VERSION 5.8 ;
BUSBITCHARS "[]" ;
DIVIDERCHAR "/" ;
UNITS
    DATABASE MICRONS 1000 ;
END UNITS

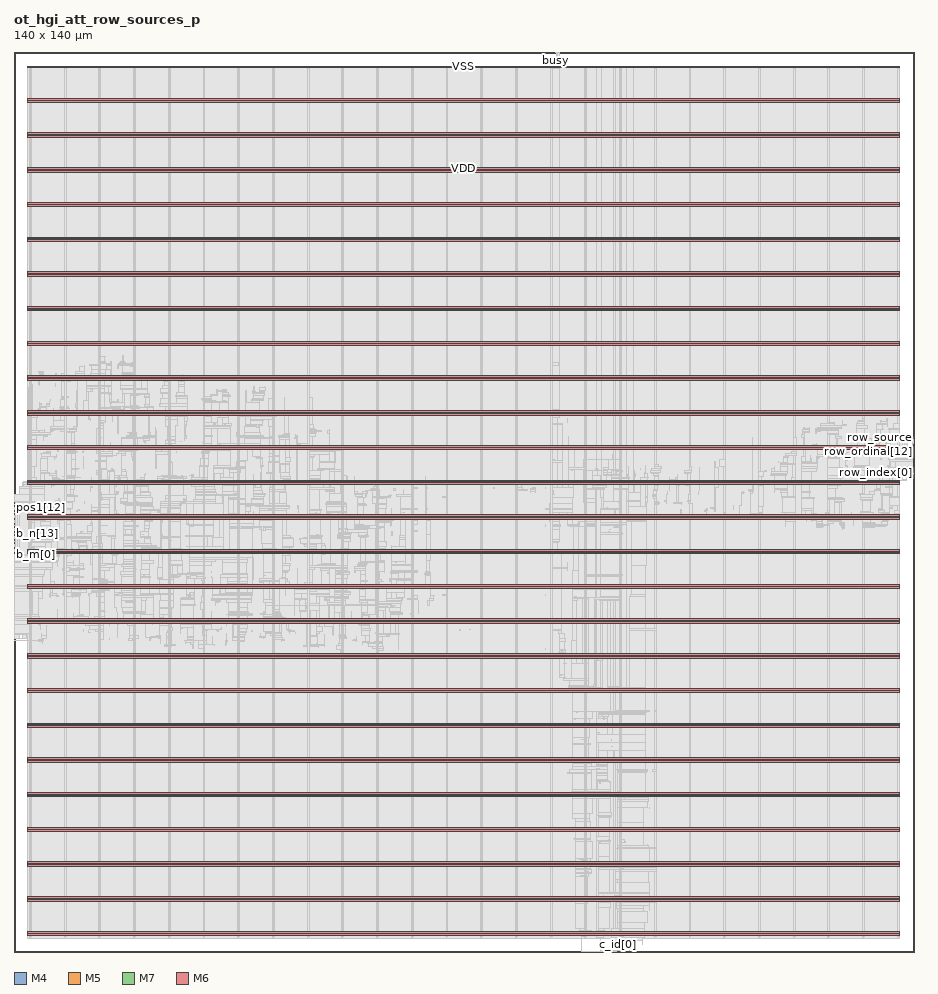
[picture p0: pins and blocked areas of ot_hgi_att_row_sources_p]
MACRO ot_hgi_att_row_sources_p
  FOREIGN ot_hgi_att_row_sources_p 0 0 ;
  CLASS BLOCK ;
  SIZE 140 BY 140 ;
  PIN b_m[0]
    DIRECTION INPUT ;
    USE SIGNAL ;
    PORT
      LAYER M4 ;
        RECT  0 61.776 0.084 61.8 ;
    END
  END b_m[0]
  PIN b_m[10]
    DIRECTION INPUT ;
    USE SIGNAL ;
    PORT
      LAYER M4 ;
        RECT  0 62.736 0.084 62.76 ;
    END
  END b_m[10]
  PIN b_m[11]
    DIRECTION INPUT ;
    USE SIGNAL ;
    PORT
      LAYER M4 ;
        RECT  0 62.832 0.084 62.856 ;
    END
  END b_m[11]
  PIN b_m[12]
    DIRECTION INPUT ;
    USE SIGNAL ;
    PORT
      LAYER M4 ;
        RECT  0 62.928 0.084 62.952 ;
    END
  END b_m[12]
  PIN b_m[13]
    DIRECTION INPUT ;
    USE SIGNAL ;
    PORT
      LAYER M4 ;
        RECT  0 63.024 0.084 63.048 ;
    END
  END b_m[13]
  PIN b_m[14]
    DIRECTION INPUT ;
    USE SIGNAL ;
    PORT
      LAYER M4 ;
        RECT  0 63.12 0.084 63.144 ;
    END
  END b_m[14]
  PIN b_m[15]
    DIRECTION INPUT ;
    USE SIGNAL ;
    PORT
      LAYER M4 ;
        RECT  0 63.216 0.084 63.24 ;
    END
  END b_m[15]
  PIN b_m[16]
    DIRECTION INPUT ;
    USE SIGNAL ;
    PORT
      LAYER M4 ;
        RECT  0 63.312 0.084 63.336 ;
    END
  END b_m[16]
  PIN b_m[17]
    DIRECTION INPUT ;
    USE SIGNAL ;
    PORT
      LAYER M4 ;
        RECT  0 63.408 0.084 63.432 ;
    END
  END b_m[17]
  PIN b_m[18]
    DIRECTION INPUT ;
    USE SIGNAL ;
    PORT
      LAYER M4 ;
        RECT  0 63.504 0.084 63.528 ;
    END
  END b_m[18]
  PIN b_m[19]
    DIRECTION INPUT ;
    USE SIGNAL ;
    PORT
      LAYER M4 ;
        RECT  0 63.6 0.084 63.624 ;
    END
  END b_m[19]
  PIN b_m[1]
    DIRECTION INPUT ;
    USE SIGNAL ;
    PORT
      LAYER M4 ;
        RECT  0 61.872 0.084 61.896 ;
    END
  END b_m[1]
  PIN b_m[20]
    DIRECTION INPUT ;
    USE SIGNAL ;
    PORT
      LAYER M4 ;
        RECT  0 63.696 0.084 63.72 ;
    END
  END b_m[20]
  PIN b_m[2]
    DIRECTION INPUT ;
    USE SIGNAL ;
    PORT
      LAYER M4 ;
        RECT  0 61.968 0.084 61.992 ;
    END
  END b_m[2]
  PIN b_m[3]
    DIRECTION INPUT ;
    USE SIGNAL ;
    PORT
      LAYER M4 ;
        RECT  0 62.064 0.084 62.088 ;
    END
  END b_m[3]
  PIN b_m[4]
    DIRECTION INPUT ;
    USE SIGNAL ;
    PORT
      LAYER M4 ;
        RECT  0 62.16 0.084 62.184 ;
    END
  END b_m[4]
  PIN b_m[5]
    DIRECTION INPUT ;
    USE SIGNAL ;
    PORT
      LAYER M4 ;
        RECT  0 62.256 0.084 62.28 ;
    END
  END b_m[5]
  PIN b_m[6]
    DIRECTION INPUT ;
    USE SIGNAL ;
    PORT
      LAYER M4 ;
        RECT  0 62.352 0.084 62.376 ;
    END
  END b_m[6]
  PIN b_m[7]
    DIRECTION INPUT ;
    USE SIGNAL ;
    PORT
      LAYER M4 ;
        RECT  0 62.448 0.084 62.472 ;
    END
  END b_m[7]
  PIN b_m[8]
    DIRECTION INPUT ;
    USE SIGNAL ;
    PORT
      LAYER M4 ;
        RECT  0 62.544 0.084 62.568 ;
    END
  END b_m[8]
  PIN b_m[9]
    DIRECTION INPUT ;
    USE SIGNAL ;
    PORT
      LAYER M4 ;
        RECT  0 62.64 0.084 62.664 ;
    END
  END b_m[9]
  PIN b_n[0]
    DIRECTION INPUT ;
    USE SIGNAL ;
    PORT
      LAYER M4 ;
        RECT  0 63.792 0.084 63.816 ;
    END
  END b_n[0]
  PIN b_n[10]
    DIRECTION INPUT ;
    USE SIGNAL ;
    PORT
      LAYER M4 ;
        RECT  0 64.752 0.084 64.776 ;
    END
  END b_n[10]
  PIN b_n[11]
    DIRECTION INPUT ;
    USE SIGNAL ;
    PORT
      LAYER M4 ;
        RECT  0 64.848 0.084 64.872 ;
    END
  END b_n[11]
  PIN b_n[12]
    DIRECTION INPUT ;
    USE SIGNAL ;
    PORT
      LAYER M4 ;
        RECT  0 64.944 0.084 64.968 ;
    END
  END b_n[12]
  PIN b_n[13]
    DIRECTION INPUT ;
    USE SIGNAL ;
    PORT
      LAYER M4 ;
        RECT  0 65.04 0.084 65.064 ;
    END
  END b_n[13]
  PIN b_n[14]
    DIRECTION INPUT ;
    USE SIGNAL ;
    PORT
      LAYER M4 ;
        RECT  0 65.136 0.084 65.16 ;
    END
  END b_n[14]
  PIN b_n[15]
    DIRECTION INPUT ;
    USE SIGNAL ;
    PORT
      LAYER M4 ;
        RECT  0 65.232 0.084 65.256 ;
    END
  END b_n[15]
  PIN b_n[16]
    DIRECTION INPUT ;
    USE SIGNAL ;
    PORT
      LAYER M4 ;
        RECT  0 65.328 0.084 65.352 ;
    END
  END b_n[16]
  PIN b_n[17]
    DIRECTION INPUT ;
    USE SIGNAL ;
    PORT
      LAYER M4 ;
        RECT  0 65.424 0.084 65.448 ;
    END
  END b_n[17]
  PIN b_n[18]
    DIRECTION INPUT ;
    USE SIGNAL ;
    PORT
      LAYER M4 ;
        RECT  0 65.52 0.084 65.544 ;
    END
  END b_n[18]
  PIN b_n[19]
    DIRECTION INPUT ;
    USE SIGNAL ;
    PORT
      LAYER M4 ;
        RECT  0 65.616 0.084 65.64 ;
    END
  END b_n[19]
  PIN b_n[1]
    DIRECTION INPUT ;
    USE SIGNAL ;
    PORT
      LAYER M4 ;
        RECT  0 63.888 0.084 63.912 ;
    END
  END b_n[1]
  PIN b_n[20]
    DIRECTION INPUT ;
    USE SIGNAL ;
    PORT
      LAYER M4 ;
        RECT  0 65.712 0.084 65.736 ;
    END
  END b_n[20]
  PIN b_n[2]
    DIRECTION INPUT ;
    USE SIGNAL ;
    PORT
      LAYER M4 ;
        RECT  0 63.984 0.084 64.008 ;
    END
  END b_n[2]
  PIN b_n[3]
    DIRECTION INPUT ;
    USE SIGNAL ;
    PORT
      LAYER M4 ;
        RECT  0 64.08 0.084 64.104 ;
    END
  END b_n[3]
  PIN b_n[4]
    DIRECTION INPUT ;
    USE SIGNAL ;
    PORT
      LAYER M4 ;
        RECT  0 64.176 0.084 64.2 ;
    END
  END b_n[4]
  PIN b_n[5]
    DIRECTION INPUT ;
    USE SIGNAL ;
    PORT
      LAYER M4 ;
        RECT  0 64.272 0.084 64.296 ;
    END
  END b_n[5]
  PIN b_n[6]
    DIRECTION INPUT ;
    USE SIGNAL ;
    PORT
      LAYER M4 ;
        RECT  0 64.368 0.084 64.392 ;
    END
  END b_n[6]
  PIN b_n[7]
    DIRECTION INPUT ;
    USE SIGNAL ;
    PORT
      LAYER M4 ;
        RECT  0 64.464 0.084 64.488 ;
    END
  END b_n[7]
  PIN b_n[8]
    DIRECTION INPUT ;
    USE SIGNAL ;
    PORT
      LAYER M4 ;
        RECT  0 64.56 0.084 64.584 ;
    END
  END b_n[8]
  PIN b_n[9]
    DIRECTION INPUT ;
    USE SIGNAL ;
    PORT
      LAYER M4 ;
        RECT  0 64.656 0.084 64.68 ;
    END
  END b_n[9]
  PIN busy
    DIRECTION OUTPUT ;
    USE SIGNAL ;
    PORT
      LAYER M5 ;
        RECT  84.24 139.916 84.264 140 ;
    END
  END busy
  PIN c_id[0]
    DIRECTION INPUT ;
    USE SIGNAL ;
    PORT
      LAYER M7 ;
        RECT  93.888 0 93.92 0.069 ;
    END
  END c_id[0]
  PIN c_id[10]
    DIRECTION INPUT ;
    USE SIGNAL ;
    PORT
      LAYER M7 ;
        RECT  95.168 0 95.2 0.069 ;
    END
  END c_id[10]
  PIN c_id[11]
    DIRECTION INPUT ;
    USE SIGNAL ;
    PORT
      LAYER M7 ;
        RECT  95.296 0 95.328 0.069 ;
    END
  END c_id[11]
  PIN c_id[12]
    DIRECTION INPUT ;
    USE SIGNAL ;
    PORT
      LAYER M7 ;
        RECT  95.424 0 95.456 0.069 ;
    END
  END c_id[12]
  PIN c_id[13]
    DIRECTION INPUT ;
    USE SIGNAL ;
    PORT
      LAYER M7 ;
        RECT  95.552 0 95.584 0.069 ;
    END
  END c_id[13]
  PIN c_id[14]
    DIRECTION INPUT ;
    USE SIGNAL ;
    PORT
      LAYER M7 ;
        RECT  95.68 0 95.712 0.069 ;
    END
  END c_id[14]
  PIN c_id[15]
    DIRECTION INPUT ;
    USE SIGNAL ;
    PORT
      LAYER M7 ;
        RECT  95.808 0 95.84 0.069 ;
    END
  END c_id[15]
  PIN c_id[16]
    DIRECTION INPUT ;
    USE SIGNAL ;
    PORT
      LAYER M7 ;
        RECT  95.936 0 95.968 0.069 ;
    END
  END c_id[16]
  PIN c_id[17]
    DIRECTION INPUT ;
    USE SIGNAL ;
    PORT
      LAYER M7 ;
        RECT  96.064 0 96.096 0.069 ;
    END
  END c_id[17]
  PIN c_id[18]
    DIRECTION INPUT ;
    USE SIGNAL ;
    PORT
      LAYER M7 ;
        RECT  96.192 0 96.224 0.069 ;
    END
  END c_id[18]
  PIN c_id[19]
    DIRECTION INPUT ;
    USE SIGNAL ;
    PORT
      LAYER M7 ;
        RECT  96.32 0 96.352 0.069 ;
    END
  END c_id[19]
  PIN c_id[1]
    DIRECTION INPUT ;
    USE SIGNAL ;
    PORT
      LAYER M7 ;
        RECT  94.016 0 94.048 0.069 ;
    END
  END c_id[1]
  PIN c_id[20]
    DIRECTION INPUT ;
    USE SIGNAL ;
    PORT
      LAYER M7 ;
        RECT  96.448 0 96.48 0.069 ;
    END
  END c_id[20]
  PIN c_id[21]
    DIRECTION INPUT ;
    USE SIGNAL ;
    PORT
      LAYER M7 ;
        RECT  96.576 0 96.608 0.069 ;
    END
  END c_id[21]
  PIN c_id[22]
    DIRECTION INPUT ;
    USE SIGNAL ;
    PORT
      LAYER M7 ;
        RECT  96.704 0 96.736 0.069 ;
    END
  END c_id[22]
  PIN c_id[23]
    DIRECTION INPUT ;
    USE SIGNAL ;
    PORT
      LAYER M7 ;
        RECT  96.832 0 96.864 0.069 ;
    END
  END c_id[23]
  PIN c_id[24]
    DIRECTION INPUT ;
    USE SIGNAL ;
    PORT
      LAYER M7 ;
        RECT  96.96 0 96.992 0.069 ;
    END
  END c_id[24]
  PIN c_id[25]
    DIRECTION INPUT ;
    USE SIGNAL ;
    PORT
      LAYER M7 ;
        RECT  97.088 0 97.12 0.069 ;
    END
  END c_id[25]
  PIN c_id[26]
    DIRECTION INPUT ;
    USE SIGNAL ;
    PORT
      LAYER M7 ;
        RECT  97.216 0 97.248 0.069 ;
    END
  END c_id[26]
  PIN c_id[27]
    DIRECTION INPUT ;
    USE SIGNAL ;
    PORT
      LAYER M7 ;
        RECT  97.344 0 97.376 0.069 ;
    END
  END c_id[27]
  PIN c_id[28]
    DIRECTION INPUT ;
    USE SIGNAL ;
    PORT
      LAYER M7 ;
        RECT  97.472 0 97.504 0.069 ;
    END
  END c_id[28]
  PIN c_id[29]
    DIRECTION INPUT ;
    USE SIGNAL ;
    PORT
      LAYER M7 ;
        RECT  97.6 0 97.632 0.069 ;
    END
  END c_id[29]
  PIN c_id[2]
    DIRECTION INPUT ;
    USE SIGNAL ;
    PORT
      LAYER M7 ;
        RECT  94.144 0 94.176 0.069 ;
    END
  END c_id[2]
  PIN c_id[30]
    DIRECTION INPUT ;
    USE SIGNAL ;
    PORT
      LAYER M7 ;
        RECT  97.728 0 97.76 0.069 ;
    END
  END c_id[30]
  PIN c_id[31]
    DIRECTION INPUT ;
    USE SIGNAL ;
    PORT
      LAYER M7 ;
        RECT  97.856 0 97.888 0.069 ;
    END
  END c_id[31]
  PIN c_id[3]
    DIRECTION INPUT ;
    USE SIGNAL ;
    PORT
      LAYER M7 ;
        RECT  94.272 0 94.304 0.069 ;
    END
  END c_id[3]
  PIN c_id[4]
    DIRECTION INPUT ;
    USE SIGNAL ;
    PORT
      LAYER M7 ;
        RECT  94.4 0 94.432 0.069 ;
    END
  END c_id[4]
  PIN c_id[5]
    DIRECTION INPUT ;
    USE SIGNAL ;
    PORT
      LAYER M7 ;
        RECT  94.528 0 94.56 0.069 ;
    END
  END c_id[5]
  PIN c_id[6]
    DIRECTION INPUT ;
    USE SIGNAL ;
    PORT
      LAYER M7 ;
        RECT  94.656 0 94.688 0.069 ;
    END
  END c_id[6]
  PIN c_id[7]
    DIRECTION INPUT ;
    USE SIGNAL ;
    PORT
      LAYER M7 ;
        RECT  94.784 0 94.816 0.069 ;
    END
  END c_id[7]
  PIN c_id[8]
    DIRECTION INPUT ;
    USE SIGNAL ;
    PORT
      LAYER M7 ;
        RECT  94.912 0 94.944 0.069 ;
    END
  END c_id[8]
  PIN c_id[9]
    DIRECTION INPUT ;
    USE SIGNAL ;
    PORT
      LAYER M7 ;
        RECT  95.04 0 95.072 0.069 ;
    END
  END c_id[9]
  PIN c_id_r
    DIRECTION OUTPUT ;
    USE SIGNAL ;
    PORT
      LAYER M7 ;
        RECT  97.984 0 98.016 0.069 ;
    END
  END c_id_r
  PIN c_id_v
    DIRECTION INPUT ;
    USE SIGNAL ;
    PORT
      LAYER M7 ;
        RECT  98.112 0 98.144 0.069 ;
    END
  END c_id_v
  PIN c_n[0]
    DIRECTION INPUT ;
    USE SIGNAL ;
    PORT
      LAYER M4 ;
        RECT  0 65.808 0.084 65.832 ;
    END
  END c_n[0]
  PIN c_n[10]
    DIRECTION INPUT ;
    USE SIGNAL ;
    PORT
      LAYER M4 ;
        RECT  0 66.768 0.084 66.792 ;
    END
  END c_n[10]
  PIN c_n[11]
    DIRECTION INPUT ;
    USE SIGNAL ;
    PORT
      LAYER M4 ;
        RECT  0 66.864 0.084 66.888 ;
    END
  END c_n[11]
  PIN c_n[12]
    DIRECTION INPUT ;
    USE SIGNAL ;
    PORT
      LAYER M4 ;
        RECT  0 66.96 0.084 66.984 ;
    END
  END c_n[12]
  PIN c_n[13]
    DIRECTION INPUT ;
    USE SIGNAL ;
    PORT
      LAYER M4 ;
        RECT  0 67.056 0.084 67.08 ;
    END
  END c_n[13]
  PIN c_n[14]
    DIRECTION INPUT ;
    USE SIGNAL ;
    PORT
      LAYER M4 ;
        RECT  0 67.152 0.084 67.176 ;
    END
  END c_n[14]
  PIN c_n[15]
    DIRECTION INPUT ;
    USE SIGNAL ;
    PORT
      LAYER M4 ;
        RECT  0 67.248 0.084 67.272 ;
    END
  END c_n[15]
  PIN c_n[16]
    DIRECTION INPUT ;
    USE SIGNAL ;
    PORT
      LAYER M4 ;
        RECT  0 67.344 0.084 67.368 ;
    END
  END c_n[16]
  PIN c_n[17]
    DIRECTION INPUT ;
    USE SIGNAL ;
    PORT
      LAYER M4 ;
        RECT  0 67.44 0.084 67.464 ;
    END
  END c_n[17]
  PIN c_n[18]
    DIRECTION INPUT ;
    USE SIGNAL ;
    PORT
      LAYER M4 ;
        RECT  0 67.536 0.084 67.56 ;
    END
  END c_n[18]
  PIN c_n[19]
    DIRECTION INPUT ;
    USE SIGNAL ;
    PORT
      LAYER M4 ;
        RECT  0 67.632 0.084 67.656 ;
    END
  END c_n[19]
  PIN c_n[1]
    DIRECTION INPUT ;
    USE SIGNAL ;
    PORT
      LAYER M4 ;
        RECT  0 65.904 0.084 65.928 ;
    END
  END c_n[1]
  PIN c_n[20]
    DIRECTION INPUT ;
    USE SIGNAL ;
    PORT
      LAYER M4 ;
        RECT  0 67.728 0.084 67.752 ;
    END
  END c_n[20]
  PIN c_n[2]
    DIRECTION INPUT ;
    USE SIGNAL ;
    PORT
      LAYER M4 ;
        RECT  0 66 0.084 66.024 ;
    END
  END c_n[2]
  PIN c_n[3]
    DIRECTION INPUT ;
    USE SIGNAL ;
    PORT
      LAYER M4 ;
        RECT  0 66.096 0.084 66.12 ;
    END
  END c_n[3]
  PIN c_n[4]
    DIRECTION INPUT ;
    USE SIGNAL ;
    PORT
      LAYER M4 ;
        RECT  0 66.192 0.084 66.216 ;
    END
  END c_n[4]
  PIN c_n[5]
    DIRECTION INPUT ;
    USE SIGNAL ;
    PORT
      LAYER M4 ;
        RECT  0 66.288 0.084 66.312 ;
    END
  END c_n[5]
  PIN c_n[6]
    DIRECTION INPUT ;
    USE SIGNAL ;
    PORT
      LAYER M4 ;
        RECT  0 66.384 0.084 66.408 ;
    END
  END c_n[6]
  PIN c_n[7]
    DIRECTION INPUT ;
    USE SIGNAL ;
    PORT
      LAYER M4 ;
        RECT  0 66.48 0.084 66.504 ;
    END
  END c_n[7]
  PIN c_n[8]
    DIRECTION INPUT ;
    USE SIGNAL ;
    PORT
      LAYER M4 ;
        RECT  0 66.576 0.084 66.6 ;
    END
  END c_n[8]
  PIN c_n[9]
    DIRECTION INPUT ;
    USE SIGNAL ;
    PORT
      LAYER M4 ;
        RECT  0 66.672 0.084 66.696 ;
    END
  END c_n[9]
  PIN clk
    DIRECTION INPUT ;
    USE SIGNAL ;
    PORT
      LAYER M5 ;
        RECT  84.336 139.916 84.36 140 ;
    END
  END clk
  PIN cmd_r
    DIRECTION OUTPUT ;
    USE SIGNAL ;
    PORT
      LAYER M4 ;
        RECT  0 67.824 0.084 67.848 ;
    END
  END cmd_r
  PIN cmd_v
    DIRECTION INPUT ;
    USE SIGNAL ;
    PORT
      LAYER M4 ;
        RECT  0 67.92 0.084 67.944 ;
    END
  END cmd_v
  PIN done
    DIRECTION OUTPUT ;
    USE SIGNAL ;
    PORT
      LAYER M5 ;
        RECT  84.432 139.916 84.456 140 ;
    END
  END done
  PIN fault
    DIRECTION OUTPUT ;
    USE SIGNAL ;
    PORT
      LAYER M5 ;
        RECT  84.528 139.916 84.552 140 ;
    END
  END fault
  PIN pos1[0]
    DIRECTION INPUT ;
    USE SIGNAL ;
    PORT
      LAYER M4 ;
        RECT  0 68.016 0.084 68.04 ;
    END
  END pos1[0]
  PIN pos1[10]
    DIRECTION INPUT ;
    USE SIGNAL ;
    PORT
      LAYER M4 ;
        RECT  0 68.976 0.084 69 ;
    END
  END pos1[10]
  PIN pos1[11]
    DIRECTION INPUT ;
    USE SIGNAL ;
    PORT
      LAYER M4 ;
        RECT  0 69.072 0.084 69.096 ;
    END
  END pos1[11]
  PIN pos1[12]
    DIRECTION INPUT ;
    USE SIGNAL ;
    PORT
      LAYER M4 ;
        RECT  0 69.168 0.084 69.192 ;
    END
  END pos1[12]
  PIN pos1[13]
    DIRECTION INPUT ;
    USE SIGNAL ;
    PORT
      LAYER M4 ;
        RECT  0 69.264 0.084 69.288 ;
    END
  END pos1[13]
  PIN pos1[14]
    DIRECTION INPUT ;
    USE SIGNAL ;
    PORT
      LAYER M4 ;
        RECT  0 69.36 0.084 69.384 ;
    END
  END pos1[14]
  PIN pos1[15]
    DIRECTION INPUT ;
    USE SIGNAL ;
    PORT
      LAYER M4 ;
        RECT  0 69.456 0.084 69.48 ;
    END
  END pos1[15]
  PIN pos1[16]
    DIRECTION INPUT ;
    USE SIGNAL ;
    PORT
      LAYER M4 ;
        RECT  0 69.552 0.084 69.576 ;
    END
  END pos1[16]
  PIN pos1[17]
    DIRECTION INPUT ;
    USE SIGNAL ;
    PORT
      LAYER M4 ;
        RECT  0 69.648 0.084 69.672 ;
    END
  END pos1[17]
  PIN pos1[18]
    DIRECTION INPUT ;
    USE SIGNAL ;
    PORT
      LAYER M4 ;
        RECT  0 69.744 0.084 69.768 ;
    END
  END pos1[18]
  PIN pos1[19]
    DIRECTION INPUT ;
    USE SIGNAL ;
    PORT
      LAYER M4 ;
        RECT  0 69.84 0.084 69.864 ;
    END
  END pos1[19]
  PIN pos1[1]
    DIRECTION INPUT ;
    USE SIGNAL ;
    PORT
      LAYER M4 ;
        RECT  0 68.112 0.084 68.136 ;
    END
  END pos1[1]
  PIN pos1[20]
    DIRECTION INPUT ;
    USE SIGNAL ;
    PORT
      LAYER M4 ;
        RECT  0 69.936 0.084 69.96 ;
    END
  END pos1[20]
  PIN pos1[2]
    DIRECTION INPUT ;
    USE SIGNAL ;
    PORT
      LAYER M4 ;
        RECT  0 68.208 0.084 68.232 ;
    END
  END pos1[2]
  PIN pos1[3]
    DIRECTION INPUT ;
    USE SIGNAL ;
    PORT
      LAYER M4 ;
        RECT  0 68.304 0.084 68.328 ;
    END
  END pos1[3]
  PIN pos1[4]
    DIRECTION INPUT ;
    USE SIGNAL ;
    PORT
      LAYER M4 ;
        RECT  0 68.4 0.084 68.424 ;
    END
  END pos1[4]
  PIN pos1[5]
    DIRECTION INPUT ;
    USE SIGNAL ;
    PORT
      LAYER M4 ;
        RECT  0 68.496 0.084 68.52 ;
    END
  END pos1[5]
  PIN pos1[6]
    DIRECTION INPUT ;
    USE SIGNAL ;
    PORT
      LAYER M4 ;
        RECT  0 68.592 0.084 68.616 ;
    END
  END pos1[6]
  PIN pos1[7]
    DIRECTION INPUT ;
    USE SIGNAL ;
    PORT
      LAYER M4 ;
        RECT  0 68.688 0.084 68.712 ;
    END
  END pos1[7]
  PIN pos1[8]
    DIRECTION INPUT ;
    USE SIGNAL ;
    PORT
      LAYER M4 ;
        RECT  0 68.784 0.084 68.808 ;
    END
  END pos1[8]
  PIN pos1[9]
    DIRECTION INPUT ;
    USE SIGNAL ;
    PORT
      LAYER M4 ;
        RECT  0 68.88 0.084 68.904 ;
    END
  END pos1[9]
  PIN ring
    DIRECTION INPUT ;
    USE SIGNAL ;
    PORT
      LAYER M4 ;
        RECT  0 70.032 0.084 70.056 ;
    END
  END ring
  PIN row_index[0]
    DIRECTION OUTPUT ;
    USE SIGNAL ;
    PORT
      LAYER M4 ;
        RECT  139.916 74.64 140 74.664 ;
    END
  END row_index[0]
  PIN row_index[10]
    DIRECTION OUTPUT ;
    USE SIGNAL ;
    PORT
      LAYER M4 ;
        RECT  139.916 75.6 140 75.624 ;
    END
  END row_index[10]
  PIN row_index[11]
    DIRECTION OUTPUT ;
    USE SIGNAL ;
    PORT
      LAYER M4 ;
        RECT  139.916 75.696 140 75.72 ;
    END
  END row_index[11]
  PIN row_index[12]
    DIRECTION OUTPUT ;
    USE SIGNAL ;
    PORT
      LAYER M4 ;
        RECT  139.916 75.792 140 75.816 ;
    END
  END row_index[12]
  PIN row_index[13]
    DIRECTION OUTPUT ;
    USE SIGNAL ;
    PORT
      LAYER M4 ;
        RECT  139.916 75.888 140 75.912 ;
    END
  END row_index[13]
  PIN row_index[14]
    DIRECTION OUTPUT ;
    USE SIGNAL ;
    PORT
      LAYER M4 ;
        RECT  139.916 75.984 140 76.008 ;
    END
  END row_index[14]
  PIN row_index[15]
    DIRECTION OUTPUT ;
    USE SIGNAL ;
    PORT
      LAYER M4 ;
        RECT  139.916 76.08 140 76.104 ;
    END
  END row_index[15]
  PIN row_index[16]
    DIRECTION OUTPUT ;
    USE SIGNAL ;
    PORT
      LAYER M4 ;
        RECT  139.916 76.176 140 76.2 ;
    END
  END row_index[16]
  PIN row_index[17]
    DIRECTION OUTPUT ;
    USE SIGNAL ;
    PORT
      LAYER M4 ;
        RECT  139.916 76.272 140 76.296 ;
    END
  END row_index[17]
  PIN row_index[18]
    DIRECTION OUTPUT ;
    USE SIGNAL ;
    PORT
      LAYER M4 ;
        RECT  139.916 76.368 140 76.392 ;
    END
  END row_index[18]
  PIN row_index[19]
    DIRECTION OUTPUT ;
    USE SIGNAL ;
    PORT
      LAYER M4 ;
        RECT  139.916 76.464 140 76.488 ;
    END
  END row_index[19]
  PIN row_index[1]
    DIRECTION OUTPUT ;
    USE SIGNAL ;
    PORT
      LAYER M4 ;
        RECT  139.916 74.736 140 74.76 ;
    END
  END row_index[1]
  PIN row_index[2]
    DIRECTION OUTPUT ;
    USE SIGNAL ;
    PORT
      LAYER M4 ;
        RECT  139.916 74.832 140 74.856 ;
    END
  END row_index[2]
  PIN row_index[3]
    DIRECTION OUTPUT ;
    USE SIGNAL ;
    PORT
      LAYER M4 ;
        RECT  139.916 74.928 140 74.952 ;
    END
  END row_index[3]
  PIN row_index[4]
    DIRECTION OUTPUT ;
    USE SIGNAL ;
    PORT
      LAYER M4 ;
        RECT  139.916 75.024 140 75.048 ;
    END
  END row_index[4]
  PIN row_index[5]
    DIRECTION OUTPUT ;
    USE SIGNAL ;
    PORT
      LAYER M4 ;
        RECT  139.916 75.12 140 75.144 ;
    END
  END row_index[5]
  PIN row_index[6]
    DIRECTION OUTPUT ;
    USE SIGNAL ;
    PORT
      LAYER M4 ;
        RECT  139.916 75.216 140 75.24 ;
    END
  END row_index[6]
  PIN row_index[7]
    DIRECTION OUTPUT ;
    USE SIGNAL ;
    PORT
      LAYER M4 ;
        RECT  139.916 75.312 140 75.336 ;
    END
  END row_index[7]
  PIN row_index[8]
    DIRECTION OUTPUT ;
    USE SIGNAL ;
    PORT
      LAYER M4 ;
        RECT  139.916 75.408 140 75.432 ;
    END
  END row_index[8]
  PIN row_index[9]
    DIRECTION OUTPUT ;
    USE SIGNAL ;
    PORT
      LAYER M4 ;
        RECT  139.916 75.504 140 75.528 ;
    END
  END row_index[9]
  PIN row_last
    DIRECTION OUTPUT ;
    USE SIGNAL ;
    PORT
      LAYER M4 ;
        RECT  139.916 76.56 140 76.584 ;
    END
  END row_last
  PIN row_ordinal[0]
    DIRECTION OUTPUT ;
    USE SIGNAL ;
    PORT
      LAYER M4 ;
        RECT  139.916 76.656 140 76.68 ;
    END
  END row_ordinal[0]
  PIN row_ordinal[10]
    DIRECTION OUTPUT ;
    USE SIGNAL ;
    PORT
      LAYER M4 ;
        RECT  139.916 77.616 140 77.64 ;
    END
  END row_ordinal[10]
  PIN row_ordinal[11]
    DIRECTION OUTPUT ;
    USE SIGNAL ;
    PORT
      LAYER M4 ;
        RECT  139.916 77.712 140 77.736 ;
    END
  END row_ordinal[11]
  PIN row_ordinal[12]
    DIRECTION OUTPUT ;
    USE SIGNAL ;
    PORT
      LAYER M4 ;
        RECT  139.916 77.808 140 77.832 ;
    END
  END row_ordinal[12]
  PIN row_ordinal[13]
    DIRECTION OUTPUT ;
    USE SIGNAL ;
    PORT
      LAYER M4 ;
        RECT  139.916 77.904 140 77.928 ;
    END
  END row_ordinal[13]
  PIN row_ordinal[14]
    DIRECTION OUTPUT ;
    USE SIGNAL ;
    PORT
      LAYER M4 ;
        RECT  139.916 78 140 78.024 ;
    END
  END row_ordinal[14]
  PIN row_ordinal[15]
    DIRECTION OUTPUT ;
    USE SIGNAL ;
    PORT
      LAYER M4 ;
        RECT  139.916 78.096 140 78.12 ;
    END
  END row_ordinal[15]
  PIN row_ordinal[16]
    DIRECTION OUTPUT ;
    USE SIGNAL ;
    PORT
      LAYER M4 ;
        RECT  139.916 78.192 140 78.216 ;
    END
  END row_ordinal[16]
  PIN row_ordinal[17]
    DIRECTION OUTPUT ;
    USE SIGNAL ;
    PORT
      LAYER M4 ;
        RECT  139.916 78.288 140 78.312 ;
    END
  END row_ordinal[17]
  PIN row_ordinal[18]
    DIRECTION OUTPUT ;
    USE SIGNAL ;
    PORT
      LAYER M4 ;
        RECT  139.916 78.384 140 78.408 ;
    END
  END row_ordinal[18]
  PIN row_ordinal[19]
    DIRECTION OUTPUT ;
    USE SIGNAL ;
    PORT
      LAYER M4 ;
        RECT  139.916 78.48 140 78.504 ;
    END
  END row_ordinal[19]
  PIN row_ordinal[1]
    DIRECTION OUTPUT ;
    USE SIGNAL ;
    PORT
      LAYER M4 ;
        RECT  139.916 76.752 140 76.776 ;
    END
  END row_ordinal[1]
  PIN row_ordinal[20]
    DIRECTION OUTPUT ;
    USE SIGNAL ;
    PORT
      LAYER M4 ;
        RECT  139.916 78.576 140 78.6 ;
    END
  END row_ordinal[20]
  PIN row_ordinal[2]
    DIRECTION OUTPUT ;
    USE SIGNAL ;
    PORT
      LAYER M4 ;
        RECT  139.916 76.848 140 76.872 ;
    END
  END row_ordinal[2]
  PIN row_ordinal[3]
    DIRECTION OUTPUT ;
    USE SIGNAL ;
    PORT
      LAYER M4 ;
        RECT  139.916 76.944 140 76.968 ;
    END
  END row_ordinal[3]
  PIN row_ordinal[4]
    DIRECTION OUTPUT ;
    USE SIGNAL ;
    PORT
      LAYER M4 ;
        RECT  139.916 77.04 140 77.064 ;
    END
  END row_ordinal[4]
  PIN row_ordinal[5]
    DIRECTION OUTPUT ;
    USE SIGNAL ;
    PORT
      LAYER M4 ;
        RECT  139.916 77.136 140 77.16 ;
    END
  END row_ordinal[5]
  PIN row_ordinal[6]
    DIRECTION OUTPUT ;
    USE SIGNAL ;
    PORT
      LAYER M4 ;
        RECT  139.916 77.232 140 77.256 ;
    END
  END row_ordinal[6]
  PIN row_ordinal[7]
    DIRECTION OUTPUT ;
    USE SIGNAL ;
    PORT
      LAYER M4 ;
        RECT  139.916 77.328 140 77.352 ;
    END
  END row_ordinal[7]
  PIN row_ordinal[8]
    DIRECTION OUTPUT ;
    USE SIGNAL ;
    PORT
      LAYER M4 ;
        RECT  139.916 77.424 140 77.448 ;
    END
  END row_ordinal[8]
  PIN row_ordinal[9]
    DIRECTION OUTPUT ;
    USE SIGNAL ;
    PORT
      LAYER M4 ;
        RECT  139.916 77.52 140 77.544 ;
    END
  END row_ordinal[9]
  PIN row_r
    DIRECTION INPUT ;
    USE SIGNAL ;
    PORT
      LAYER M4 ;
        RECT  139.916 78.672 140 78.696 ;
    END
  END row_r
  PIN row_source
    DIRECTION OUTPUT ;
    USE SIGNAL ;
    PORT
      LAYER M4 ;
        RECT  139.916 78.768 140 78.792 ;
    END
  END row_source
  PIN row_v
    DIRECTION OUTPUT ;
    USE SIGNAL ;
    PORT
      LAYER M4 ;
        RECT  139.916 78.864 140 78.888 ;
    END
  END row_v
  PIN rst_n
    DIRECTION INPUT ;
    USE SIGNAL ;
    PORT
      LAYER M5 ;
        RECT  84.624 139.916 84.648 140 ;
    END
  END rst_n
  PIN VDD
    DIRECTION INOUT ;
    USE POWER ;
    PORT
      LAYER M6 ;
        RECT  2.16 132.513 137.808 132.801 ;
        RECT  2.16 127.113 137.808 127.401 ;
        RECT  2.16 121.713 137.808 122.001 ;
        RECT  2.16 116.313 137.808 116.601 ;
        RECT  2.16 110.913 137.808 111.201 ;
        RECT  2.16 105.513 137.808 105.801 ;
        RECT  2.16 100.113 137.808 100.401 ;
        RECT  2.16 94.713 137.808 95.001 ;
        RECT  2.16 89.313 137.808 89.601 ;
        RECT  2.16 83.913 137.808 84.201 ;
        RECT  2.16 78.513 137.808 78.801 ;
        RECT  2.16 73.113 137.808 73.401 ;
        RECT  2.16 67.713 137.808 68.001 ;
        RECT  2.16 62.313 137.808 62.601 ;
        RECT  2.16 56.913 137.808 57.201 ;
        RECT  2.16 51.513 137.808 51.801 ;
        RECT  2.16 46.113 137.808 46.401 ;
        RECT  2.16 40.713 137.808 41.001 ;
        RECT  2.16 35.313 137.808 35.601 ;
        RECT  2.16 29.913 137.808 30.201 ;
        RECT  2.16 24.513 137.808 24.801 ;
        RECT  2.16 19.113 137.808 19.401 ;
        RECT  2.16 13.713 137.808 14.001 ;
        RECT  2.16 8.313 137.808 8.601 ;
        RECT  2.16 2.913 137.808 3.201 ;
    END
  END VDD
  PIN VSS
    DIRECTION INOUT ;
    USE GROUND ;
    PORT
      LAYER M6 ;
        RECT  2.16 137.529 137.808 137.817 ;
        RECT  2.16 132.129 137.808 132.417 ;
        RECT  2.16 126.729 137.808 127.017 ;
        RECT  2.16 121.329 137.808 121.617 ;
        RECT  2.16 115.929 137.808 116.217 ;
        RECT  2.16 110.529 137.808 110.817 ;
        RECT  2.16 105.129 137.808 105.417 ;
        RECT  2.16 99.729 137.808 100.017 ;
        RECT  2.16 94.329 137.808 94.617 ;
        RECT  2.16 88.929 137.808 89.217 ;
        RECT  2.16 83.529 137.808 83.817 ;
        RECT  2.16 78.129 137.808 78.417 ;
        RECT  2.16 72.729 137.808 73.017 ;
        RECT  2.16 67.329 137.808 67.617 ;
        RECT  2.16 61.929 137.808 62.217 ;
        RECT  2.16 56.529 137.808 56.817 ;
        RECT  2.16 51.129 137.808 51.417 ;
        RECT  2.16 45.729 137.808 46.017 ;
        RECT  2.16 40.329 137.808 40.617 ;
        RECT  2.16 34.929 137.808 35.217 ;
        RECT  2.16 29.529 137.808 29.817 ;
        RECT  2.16 24.129 137.808 24.417 ;
        RECT  2.16 18.729 137.808 19.017 ;
        RECT  2.16 13.329 137.808 13.617 ;
        RECT  2.16 7.929 137.808 8.217 ;
        RECT  2.16 2.529 137.808 2.817 ;
    END
  END VSS
  OBS
    LAYER RVTN ;
     RECT  2.16 2.16 137.808 2.295 ;
     RECT  2.16 2.565 137.808 2.835 ;
     RECT  2.16 3.105 137.808 3.375 ;
     RECT  2.16 3.645 137.808 3.915 ;
     RECT  2.16 4.185 137.808 4.455 ;
     RECT  2.16 4.725 137.808 4.995 ;
     RECT  2.16 5.265 137.808 5.535 ;
     RECT  2.16 5.805 137.808 6.075 ;
     RECT  2.16 6.345 137.808 6.615 ;
     RECT  2.16 6.885 137.808 7.155 ;
     RECT  2.16 7.425 137.808 7.695 ;
     RECT  2.16 7.965 137.808 8.235 ;
     RECT  2.16 8.505 137.808 8.775 ;
     RECT  2.16 9.045 137.808 9.315 ;
     RECT  2.16 9.585 137.808 9.855 ;
     RECT  2.16 10.125 137.808 10.395 ;
     RECT  2.16 10.665 137.808 10.935 ;
     RECT  2.16 11.205 137.808 11.475 ;
     RECT  2.16 11.745 137.808 12.015 ;
     RECT  2.16 12.285 137.808 12.555 ;
     RECT  2.16 12.825 137.808 13.095 ;
     RECT  2.16 13.365 137.808 13.635 ;
     RECT  2.16 13.905 137.808 14.175 ;
     RECT  2.16 14.445 137.808 14.715 ;
     RECT  2.16 14.985 137.808 15.255 ;
     RECT  2.16 15.525 137.808 15.795 ;
     RECT  2.16 16.065 137.808 16.335 ;
     RECT  2.16 16.605 137.808 16.875 ;
     RECT  2.16 17.145 137.808 17.415 ;
     RECT  2.16 17.685 137.808 17.955 ;
     RECT  2.16 18.225 137.808 18.495 ;
     RECT  2.16 18.765 137.808 19.035 ;
     RECT  2.16 19.305 137.808 19.575 ;
     RECT  2.16 19.845 137.808 20.115 ;
     RECT  2.16 20.385 137.808 20.655 ;
     RECT  2.16 20.925 137.808 21.195 ;
     RECT  2.16 21.465 137.808 21.735 ;
     RECT  2.16 22.005 137.808 22.275 ;
     RECT  2.16 22.545 137.808 22.815 ;
     RECT  2.16 23.085 137.808 23.355 ;
     RECT  2.16 23.625 137.808 23.895 ;
     RECT  2.16 24.165 137.808 24.435 ;
     RECT  2.16 24.705 137.808 24.975 ;
     RECT  2.16 25.245 137.808 25.515 ;
     RECT  2.16 25.785 137.808 26.055 ;
     RECT  2.16 26.325 137.808 26.595 ;
     RECT  2.16 26.865 137.808 27.135 ;
     RECT  2.16 27.405 137.808 27.675 ;
     RECT  2.16 27.945 137.808 28.215 ;
     RECT  2.16 28.485 137.808 28.755 ;
     RECT  2.16 29.025 137.808 29.295 ;
     RECT  2.16 29.565 137.808 29.835 ;
     RECT  2.16 30.105 137.808 30.375 ;
     RECT  2.16 30.645 137.808 30.915 ;
     RECT  2.16 31.185 137.808 31.455 ;
     RECT  2.16 31.725 137.808 31.995 ;
     RECT  2.16 32.265 137.808 32.535 ;
     RECT  2.16 32.805 137.808 33.075 ;
     RECT  2.16 33.345 137.808 33.615 ;
     RECT  2.16 33.885 137.808 34.155 ;
     RECT  2.16 34.425 137.808 34.695 ;
     RECT  2.16 34.965 137.808 35.235 ;
     RECT  2.16 35.505 137.808 35.775 ;
     RECT  2.16 36.045 137.808 36.315 ;
     RECT  2.16 36.585 137.808 36.855 ;
     RECT  2.16 37.125 137.808 37.395 ;
     RECT  2.16 37.665 137.808 37.935 ;
     RECT  2.16 38.205 137.808 38.475 ;
     RECT  2.16 38.745 137.808 39.015 ;
     RECT  2.16 39.285 137.808 39.555 ;
     RECT  2.16 39.825 137.808 40.095 ;
     RECT  2.16 40.365 137.808 40.635 ;
     RECT  2.16 40.905 137.808 41.175 ;
     RECT  2.16 41.445 137.808 41.715 ;
     RECT  2.16 41.985 137.808 42.255 ;
     RECT  2.16 42.525 137.808 42.795 ;
     RECT  2.16 43.065 137.808 43.335 ;
     RECT  2.16 43.605 137.808 43.875 ;
     RECT  2.16 44.145 137.808 44.415 ;
     RECT  2.16 44.685 137.808 44.955 ;
     RECT  2.16 45.225 137.808 45.495 ;
     RECT  2.16 45.765 137.808 46.035 ;
     RECT  2.16 46.305 137.808 46.575 ;
     RECT  2.16 46.845 137.808 47.115 ;
     RECT  2.16 47.385 137.808 47.655 ;
     RECT  2.16 47.925 137.808 48.195 ;
     RECT  2.16 48.465 137.808 48.735 ;
     RECT  2.16 49.005 137.808 49.275 ;
     RECT  2.16 49.545 137.808 49.815 ;
     RECT  2.16 50.085 137.808 50.355 ;
     RECT  2.16 50.625 137.808 50.895 ;
     RECT  2.16 51.165 137.808 51.435 ;
     RECT  2.16 51.705 137.808 51.975 ;
     RECT  2.16 52.245 137.808 52.515 ;
     RECT  2.16 52.785 137.808 53.055 ;
     RECT  2.16 53.325 137.808 53.595 ;
     RECT  2.16 53.865 137.808 54.135 ;
     RECT  2.16 54.405 137.808 54.675 ;
     RECT  2.16 54.945 137.808 55.215 ;
     RECT  2.16 55.485 137.808 55.755 ;
     RECT  2.16 56.025 137.808 56.295 ;
     RECT  2.16 56.565 137.808 56.835 ;
     RECT  2.16 57.105 137.808 57.375 ;
     RECT  2.16 57.645 137.808 57.915 ;
     RECT  2.16 58.185 137.808 58.455 ;
     RECT  2.16 58.725 137.808 58.995 ;
     RECT  2.16 59.265 137.808 59.535 ;
     RECT  2.16 59.805 137.808 60.075 ;
     RECT  2.16 60.345 137.808 60.615 ;
     RECT  2.16 60.885 137.808 61.155 ;
     RECT  2.16 61.425 137.808 61.695 ;
     RECT  2.16 61.965 137.808 62.235 ;
     RECT  2.16 62.505 137.808 62.775 ;
     RECT  2.16 63.045 137.808 63.315 ;
     RECT  2.16 63.585 137.808 63.855 ;
     RECT  2.16 64.125 137.808 64.395 ;
     RECT  2.16 64.665 137.808 64.935 ;
     RECT  2.16 65.205 137.808 65.475 ;
     RECT  2.16 65.745 137.808 66.015 ;
     RECT  2.16 66.285 137.808 66.555 ;
     RECT  2.16 66.825 137.808 67.095 ;
     RECT  2.16 67.365 137.808 67.635 ;
     RECT  2.16 67.905 137.808 68.175 ;
     RECT  2.16 68.445 137.808 68.715 ;
     RECT  2.16 68.985 137.808 69.255 ;
     RECT  2.16 69.525 137.808 69.795 ;
     RECT  2.16 70.065 137.808 70.335 ;
     RECT  2.16 70.605 137.808 70.875 ;
     RECT  2.16 71.145 137.808 71.415 ;
     RECT  2.16 71.685 137.808 71.955 ;
     RECT  2.16 72.225 137.808 72.495 ;
     RECT  2.16 72.765 137.808 73.035 ;
     RECT  2.16 73.305 137.808 73.575 ;
     RECT  2.16 73.845 137.808 74.115 ;
     RECT  2.16 74.385 137.808 74.655 ;
     RECT  2.16 74.925 137.808 75.195 ;
     RECT  2.16 75.465 137.808 75.735 ;
     RECT  2.16 76.005 137.808 76.275 ;
     RECT  2.16 76.545 137.808 76.815 ;
     RECT  2.16 77.085 137.808 77.355 ;
     RECT  2.16 77.625 137.808 77.895 ;
     RECT  2.16 78.165 137.808 78.435 ;
     RECT  2.16 78.705 137.808 78.975 ;
     RECT  2.16 79.245 137.808 79.515 ;
     RECT  2.16 79.785 137.808 80.055 ;
     RECT  2.16 80.325 137.808 80.595 ;
     RECT  2.16 80.865 137.808 81.135 ;
     RECT  2.16 81.405 137.808 81.675 ;
     RECT  2.16 81.945 137.808 82.215 ;
     RECT  2.16 82.485 137.808 82.755 ;
     RECT  2.16 83.025 137.808 83.295 ;
     RECT  2.16 83.565 137.808 83.835 ;
     RECT  2.16 84.105 137.808 84.375 ;
     RECT  2.16 84.645 137.808 84.915 ;
     RECT  2.16 85.185 137.808 85.455 ;
     RECT  2.16 85.725 137.808 85.995 ;
     RECT  2.16 86.265 137.808 86.535 ;
     RECT  2.16 86.805 137.808 87.075 ;
     RECT  2.16 87.345 137.808 87.615 ;
     RECT  2.16 87.885 137.808 88.155 ;
     RECT  2.16 88.425 137.808 88.695 ;
     RECT  2.16 88.965 137.808 89.235 ;
     RECT  2.16 89.505 137.808 89.775 ;
     RECT  2.16 90.045 137.808 90.315 ;
     RECT  2.16 90.585 137.808 90.855 ;
     RECT  2.16 91.125 137.808 91.395 ;
     RECT  2.16 91.665 137.808 91.935 ;
     RECT  2.16 92.205 137.808 92.475 ;
     RECT  2.16 92.745 137.808 93.015 ;
     RECT  2.16 93.285 137.808 93.555 ;
     RECT  2.16 93.825 137.808 94.095 ;
     RECT  2.16 94.365 137.808 94.635 ;
     RECT  2.16 94.905 137.808 95.175 ;
     RECT  2.16 95.445 137.808 95.715 ;
     RECT  2.16 95.985 137.808 96.255 ;
     RECT  2.16 96.525 137.808 96.795 ;
     RECT  2.16 97.065 137.808 97.335 ;
     RECT  2.16 97.605 137.808 97.875 ;
     RECT  2.16 98.145 137.808 98.415 ;
     RECT  2.16 98.685 137.808 98.955 ;
     RECT  2.16 99.225 137.808 99.495 ;
     RECT  2.16 99.765 137.808 100.035 ;
     RECT  2.16 100.305 137.808 100.575 ;
     RECT  2.16 100.845 137.808 101.115 ;
     RECT  2.16 101.385 137.808 101.655 ;
     RECT  2.16 101.925 137.808 102.195 ;
     RECT  2.16 102.465 137.808 102.735 ;
     RECT  2.16 103.005 137.808 103.275 ;
     RECT  2.16 103.545 137.808 103.815 ;
     RECT  2.16 104.085 137.808 104.355 ;
     RECT  2.16 104.625 137.808 104.895 ;
     RECT  2.16 105.165 137.808 105.435 ;
     RECT  2.16 105.705 137.808 105.975 ;
     RECT  2.16 106.245 137.808 106.515 ;
     RECT  2.16 106.785 137.808 107.055 ;
     RECT  2.16 107.325 137.808 107.595 ;
     RECT  2.16 107.865 137.808 108.135 ;
     RECT  2.16 108.405 137.808 108.675 ;
     RECT  2.16 108.945 137.808 109.215 ;
     RECT  2.16 109.485 137.808 109.755 ;
     RECT  2.16 110.025 137.808 110.295 ;
     RECT  2.16 110.565 137.808 110.835 ;
     RECT  2.16 111.105 137.808 111.375 ;
     RECT  2.16 111.645 137.808 111.915 ;
     RECT  2.16 112.185 137.808 112.455 ;
     RECT  2.16 112.725 137.808 112.995 ;
     RECT  2.16 113.265 137.808 113.535 ;
     RECT  2.16 113.805 137.808 114.075 ;
     RECT  2.16 114.345 137.808 114.615 ;
     RECT  2.16 114.885 137.808 115.155 ;
     RECT  2.16 115.425 137.808 115.695 ;
     RECT  2.16 115.965 137.808 116.235 ;
     RECT  2.16 116.505 137.808 116.775 ;
     RECT  2.16 117.045 137.808 117.315 ;
     RECT  2.16 117.585 137.808 117.855 ;
     RECT  2.16 118.125 137.808 118.395 ;
     RECT  2.16 118.665 137.808 118.935 ;
     RECT  2.16 119.205 137.808 119.475 ;
     RECT  2.16 119.745 137.808 120.015 ;
     RECT  2.16 120.285 137.808 120.555 ;
     RECT  2.16 120.825 137.808 121.095 ;
     RECT  2.16 121.365 137.808 121.635 ;
     RECT  2.16 121.905 137.808 122.175 ;
     RECT  2.16 122.445 137.808 122.715 ;
     RECT  2.16 122.985 137.808 123.255 ;
     RECT  2.16 123.525 137.808 123.795 ;
     RECT  2.16 124.065 137.808 124.335 ;
     RECT  2.16 124.605 137.808 124.875 ;
     RECT  2.16 125.145 137.808 125.415 ;
     RECT  2.16 125.685 137.808 125.955 ;
     RECT  2.16 126.225 137.808 126.495 ;
     RECT  2.16 126.765 137.808 127.035 ;
     RECT  2.16 127.305 137.808 127.575 ;
     RECT  2.16 127.845 137.808 128.115 ;
     RECT  2.16 128.385 137.808 128.655 ;
     RECT  2.16 128.925 137.808 129.195 ;
     RECT  2.16 129.465 137.808 129.735 ;
     RECT  2.16 130.005 137.808 130.275 ;
     RECT  2.16 130.545 137.808 130.815 ;
     RECT  2.16 131.085 137.808 131.355 ;
     RECT  2.16 131.625 137.808 131.895 ;
     RECT  2.16 132.165 137.808 132.435 ;
     RECT  2.16 132.705 137.808 132.975 ;
     RECT  2.16 133.245 137.808 133.515 ;
     RECT  2.16 133.785 137.808 134.055 ;
     RECT  2.16 134.325 137.808 134.595 ;
     RECT  2.16 134.865 137.808 135.135 ;
     RECT  2.16 135.405 137.808 135.675 ;
     RECT  2.16 135.945 137.808 136.215 ;
     RECT  2.16 136.485 137.808 136.755 ;
     RECT  2.16 137.025 137.808 137.295 ;
     RECT  2.16 137.565 137.808 137.7 ;
    LAYER RVTP ;
     RECT  2.16 2.295 137.808 2.565 ;
     RECT  2.16 2.835 137.808 3.105 ;
     RECT  2.16 3.375 137.808 3.645 ;
     RECT  2.16 3.915 137.808 4.185 ;
     RECT  2.16 4.455 137.808 4.725 ;
     RECT  2.16 4.995 137.808 5.265 ;
     RECT  2.16 5.535 137.808 5.805 ;
     RECT  2.16 6.075 137.808 6.345 ;
     RECT  2.16 6.615 137.808 6.885 ;
     RECT  2.16 7.155 137.808 7.425 ;
     RECT  2.16 7.695 137.808 7.965 ;
     RECT  2.16 8.235 137.808 8.505 ;
     RECT  2.16 8.775 137.808 9.045 ;
     RECT  2.16 9.315 137.808 9.585 ;
     RECT  2.16 9.855 137.808 10.125 ;
     RECT  2.16 10.395 137.808 10.665 ;
     RECT  2.16 10.935 137.808 11.205 ;
     RECT  2.16 11.475 137.808 11.745 ;
     RECT  2.16 12.015 137.808 12.285 ;
     RECT  2.16 12.555 137.808 12.825 ;
     RECT  2.16 13.095 137.808 13.365 ;
     RECT  2.16 13.635 137.808 13.905 ;
     RECT  2.16 14.175 137.808 14.445 ;
     RECT  2.16 14.715 137.808 14.985 ;
     RECT  2.16 15.255 137.808 15.525 ;
     RECT  2.16 15.795 137.808 16.065 ;
     RECT  2.16 16.335 137.808 16.605 ;
     RECT  2.16 16.875 137.808 17.145 ;
     RECT  2.16 17.415 137.808 17.685 ;
     RECT  2.16 17.955 137.808 18.225 ;
     RECT  2.16 18.495 137.808 18.765 ;
     RECT  2.16 19.035 137.808 19.305 ;
     RECT  2.16 19.575 137.808 19.845 ;
     RECT  2.16 20.115 137.808 20.385 ;
     RECT  2.16 20.655 137.808 20.925 ;
     RECT  2.16 21.195 137.808 21.465 ;
     RECT  2.16 21.735 137.808 22.005 ;
     RECT  2.16 22.275 137.808 22.545 ;
     RECT  2.16 22.815 137.808 23.085 ;
     RECT  2.16 23.355 137.808 23.625 ;
     RECT  2.16 23.895 137.808 24.165 ;
     RECT  2.16 24.435 137.808 24.705 ;
     RECT  2.16 24.975 137.808 25.245 ;
     RECT  2.16 25.515 137.808 25.785 ;
     RECT  2.16 26.055 137.808 26.325 ;
     RECT  2.16 26.595 137.808 26.865 ;
     RECT  2.16 27.135 137.808 27.405 ;
     RECT  2.16 27.675 137.808 27.945 ;
     RECT  2.16 28.215 137.808 28.485 ;
     RECT  2.16 28.755 137.808 29.025 ;
     RECT  2.16 29.295 137.808 29.565 ;
     RECT  2.16 29.835 137.808 30.105 ;
     RECT  2.16 30.375 137.808 30.645 ;
     RECT  2.16 30.915 137.808 31.185 ;
     RECT  2.16 31.455 137.808 31.725 ;
     RECT  2.16 31.995 137.808 32.265 ;
     RECT  2.16 32.535 137.808 32.805 ;
     RECT  2.16 33.075 137.808 33.345 ;
     RECT  2.16 33.615 137.808 33.885 ;
     RECT  2.16 34.155 137.808 34.425 ;
     RECT  2.16 34.695 137.808 34.965 ;
     RECT  2.16 35.235 137.808 35.505 ;
     RECT  2.16 35.775 137.808 36.045 ;
     RECT  2.16 36.315 137.808 36.585 ;
     RECT  2.16 36.855 137.808 37.125 ;
     RECT  2.16 37.395 137.808 37.665 ;
     RECT  2.16 37.935 137.808 38.205 ;
     RECT  2.16 38.475 137.808 38.745 ;
     RECT  2.16 39.015 137.808 39.285 ;
     RECT  2.16 39.555 137.808 39.825 ;
     RECT  2.16 40.095 137.808 40.365 ;
     RECT  2.16 40.635 137.808 40.905 ;
     RECT  2.16 41.175 137.808 41.445 ;
     RECT  2.16 41.715 137.808 41.985 ;
     RECT  2.16 42.255 137.808 42.525 ;
     RECT  2.16 42.795 137.808 43.065 ;
     RECT  2.16 43.335 137.808 43.605 ;
     RECT  2.16 43.875 137.808 44.145 ;
     RECT  2.16 44.415 137.808 44.685 ;
     RECT  2.16 44.955 137.808 45.225 ;
     RECT  2.16 45.495 137.808 45.765 ;
     RECT  2.16 46.035 137.808 46.305 ;
     RECT  2.16 46.575 137.808 46.845 ;
     RECT  2.16 47.115 137.808 47.385 ;
     RECT  2.16 47.655 137.808 47.925 ;
     RECT  2.16 48.195 137.808 48.465 ;
     RECT  2.16 48.735 137.808 49.005 ;
     RECT  2.16 49.275 137.808 49.545 ;
     RECT  2.16 49.815 137.808 50.085 ;
     RECT  2.16 50.355 137.808 50.625 ;
     RECT  2.16 50.895 137.808 51.165 ;
     RECT  2.16 51.435 137.808 51.705 ;
     RECT  2.16 51.975 137.808 52.245 ;
     RECT  2.16 52.515 137.808 52.785 ;
     RECT  2.16 53.055 137.808 53.325 ;
     RECT  2.16 53.595 137.808 53.865 ;
     RECT  2.16 54.135 137.808 54.405 ;
     RECT  2.16 54.675 137.808 54.945 ;
     RECT  2.16 55.215 137.808 55.485 ;
     RECT  2.16 55.755 137.808 56.025 ;
     RECT  2.16 56.295 137.808 56.565 ;
     RECT  2.16 56.835 137.808 57.105 ;
     RECT  2.16 57.375 137.808 57.645 ;
     RECT  2.16 57.915 137.808 58.185 ;
     RECT  2.16 58.455 137.808 58.725 ;
     RECT  2.16 58.995 137.808 59.265 ;
     RECT  2.16 59.535 137.808 59.805 ;
     RECT  2.16 60.075 137.808 60.345 ;
     RECT  2.16 60.615 137.808 60.885 ;
     RECT  2.16 61.155 137.808 61.425 ;
     RECT  2.16 61.695 137.808 61.965 ;
     RECT  2.16 62.235 137.808 62.505 ;
     RECT  2.16 62.775 137.808 63.045 ;
     RECT  2.16 63.315 137.808 63.585 ;
     RECT  2.16 63.855 137.808 64.125 ;
     RECT  2.16 64.395 137.808 64.665 ;
     RECT  2.16 64.935 137.808 65.205 ;
     RECT  2.16 65.475 137.808 65.745 ;
     RECT  2.16 66.015 137.808 66.285 ;
     RECT  2.16 66.555 137.808 66.825 ;
     RECT  2.16 67.095 137.808 67.365 ;
     RECT  2.16 67.635 137.808 67.905 ;
     RECT  2.16 68.175 137.808 68.445 ;
     RECT  2.16 68.715 137.808 68.985 ;
     RECT  2.16 69.255 137.808 69.525 ;
     RECT  2.16 69.795 137.808 70.065 ;
     RECT  2.16 70.335 137.808 70.605 ;
     RECT  2.16 70.875 137.808 71.145 ;
     RECT  2.16 71.415 137.808 71.685 ;
     RECT  2.16 71.955 137.808 72.225 ;
     RECT  2.16 72.495 137.808 72.765 ;
     RECT  2.16 73.035 137.808 73.305 ;
     RECT  2.16 73.575 137.808 73.845 ;
     RECT  2.16 74.115 137.808 74.385 ;
     RECT  2.16 74.655 137.808 74.925 ;
     RECT  2.16 75.195 137.808 75.465 ;
     RECT  2.16 75.735 137.808 76.005 ;
     RECT  2.16 76.275 137.808 76.545 ;
     RECT  2.16 76.815 137.808 77.085 ;
     RECT  2.16 77.355 137.808 77.625 ;
     RECT  2.16 77.895 137.808 78.165 ;
     RECT  2.16 78.435 137.808 78.705 ;
     RECT  2.16 78.975 137.808 79.245 ;
     RECT  2.16 79.515 137.808 79.785 ;
     RECT  2.16 80.055 137.808 80.325 ;
     RECT  2.16 80.595 137.808 80.865 ;
     RECT  2.16 81.135 137.808 81.405 ;
     RECT  2.16 81.675 137.808 81.945 ;
     RECT  2.16 82.215 137.808 82.485 ;
     RECT  2.16 82.755 137.808 83.025 ;
     RECT  2.16 83.295 137.808 83.565 ;
     RECT  2.16 83.835 137.808 84.105 ;
     RECT  2.16 84.375 137.808 84.645 ;
     RECT  2.16 84.915 137.808 85.185 ;
     RECT  2.16 85.455 137.808 85.725 ;
     RECT  2.16 85.995 137.808 86.265 ;
     RECT  2.16 86.535 137.808 86.805 ;
     RECT  2.16 87.075 137.808 87.345 ;
     RECT  2.16 87.615 137.808 87.885 ;
     RECT  2.16 88.155 137.808 88.425 ;
     RECT  2.16 88.695 137.808 88.965 ;
     RECT  2.16 89.235 137.808 89.505 ;
     RECT  2.16 89.775 137.808 90.045 ;
     RECT  2.16 90.315 137.808 90.585 ;
     RECT  2.16 90.855 137.808 91.125 ;
     RECT  2.16 91.395 137.808 91.665 ;
     RECT  2.16 91.935 137.808 92.205 ;
     RECT  2.16 92.475 137.808 92.745 ;
     RECT  2.16 93.015 137.808 93.285 ;
     RECT  2.16 93.555 137.808 93.825 ;
     RECT  2.16 94.095 137.808 94.365 ;
     RECT  2.16 94.635 137.808 94.905 ;
     RECT  2.16 95.175 137.808 95.445 ;
     RECT  2.16 95.715 137.808 95.985 ;
     RECT  2.16 96.255 137.808 96.525 ;
     RECT  2.16 96.795 137.808 97.065 ;
     RECT  2.16 97.335 137.808 97.605 ;
     RECT  2.16 97.875 137.808 98.145 ;
     RECT  2.16 98.415 137.808 98.685 ;
     RECT  2.16 98.955 137.808 99.225 ;
     RECT  2.16 99.495 137.808 99.765 ;
     RECT  2.16 100.035 137.808 100.305 ;
     RECT  2.16 100.575 137.808 100.845 ;
     RECT  2.16 101.115 137.808 101.385 ;
     RECT  2.16 101.655 137.808 101.925 ;
     RECT  2.16 102.195 137.808 102.465 ;
     RECT  2.16 102.735 137.808 103.005 ;
     RECT  2.16 103.275 137.808 103.545 ;
     RECT  2.16 103.815 137.808 104.085 ;
     RECT  2.16 104.355 137.808 104.625 ;
     RECT  2.16 104.895 137.808 105.165 ;
     RECT  2.16 105.435 137.808 105.705 ;
     RECT  2.16 105.975 137.808 106.245 ;
     RECT  2.16 106.515 137.808 106.785 ;
     RECT  2.16 107.055 137.808 107.325 ;
     RECT  2.16 107.595 137.808 107.865 ;
     RECT  2.16 108.135 137.808 108.405 ;
     RECT  2.16 108.675 137.808 108.945 ;
     RECT  2.16 109.215 137.808 109.485 ;
     RECT  2.16 109.755 137.808 110.025 ;
     RECT  2.16 110.295 137.808 110.565 ;
     RECT  2.16 110.835 137.808 111.105 ;
     RECT  2.16 111.375 137.808 111.645 ;
     RECT  2.16 111.915 137.808 112.185 ;
     RECT  2.16 112.455 137.808 112.725 ;
     RECT  2.16 112.995 137.808 113.265 ;
     RECT  2.16 113.535 137.808 113.805 ;
     RECT  2.16 114.075 137.808 114.345 ;
     RECT  2.16 114.615 137.808 114.885 ;
     RECT  2.16 115.155 137.808 115.425 ;
     RECT  2.16 115.695 137.808 115.965 ;
     RECT  2.16 116.235 137.808 116.505 ;
     RECT  2.16 116.775 137.808 117.045 ;
     RECT  2.16 117.315 137.808 117.585 ;
     RECT  2.16 117.855 137.808 118.125 ;
     RECT  2.16 118.395 137.808 118.665 ;
     RECT  2.16 118.935 137.808 119.205 ;
     RECT  2.16 119.475 137.808 119.745 ;
     RECT  2.16 120.015 137.808 120.285 ;
     RECT  2.16 120.555 137.808 120.825 ;
     RECT  2.16 121.095 137.808 121.365 ;
     RECT  2.16 121.635 137.808 121.905 ;
     RECT  2.16 122.175 137.808 122.445 ;
     RECT  2.16 122.715 137.808 122.985 ;
     RECT  2.16 123.255 137.808 123.525 ;
     RECT  2.16 123.795 137.808 124.065 ;
     RECT  2.16 124.335 137.808 124.605 ;
     RECT  2.16 124.875 137.808 125.145 ;
     RECT  2.16 125.415 137.808 125.685 ;
     RECT  2.16 125.955 137.808 126.225 ;
     RECT  2.16 126.495 137.808 126.765 ;
     RECT  2.16 127.035 137.808 127.305 ;
     RECT  2.16 127.575 137.808 127.845 ;
     RECT  2.16 128.115 137.808 128.385 ;
     RECT  2.16 128.655 137.808 128.925 ;
     RECT  2.16 129.195 137.808 129.465 ;
     RECT  2.16 129.735 137.808 130.005 ;
     RECT  2.16 130.275 137.808 130.545 ;
     RECT  2.16 130.815 137.808 131.085 ;
     RECT  2.16 131.355 137.808 131.625 ;
     RECT  2.16 131.895 137.808 132.165 ;
     RECT  2.16 132.435 137.808 132.705 ;
     RECT  2.16 132.975 137.808 133.245 ;
     RECT  2.16 133.515 137.808 133.785 ;
     RECT  2.16 134.055 137.808 134.325 ;
     RECT  2.16 134.595 137.808 134.865 ;
     RECT  2.16 135.135 137.808 135.405 ;
     RECT  2.16 135.675 137.808 135.945 ;
     RECT  2.16 136.215 137.808 136.485 ;
     RECT  2.16 136.755 137.808 137.025 ;
     RECT  2.16 137.295 137.808 137.565 ;
    LAYER M1 ;
     RECT  2.16 2.151 137.808 137.709 ;
    LAYER M2 ;
     RECT  0.031 63.63 0.067 63.648 ;
     RECT  0.031 68.184 0.067 68.202 ;
     RECT  0.067 68.184 0.103 68.778 ;
     RECT  0.031 58.77 0.131 58.788 ;
     RECT  0.067 64.98 0.167 64.998 ;
     RECT  0.103 52.29 0.175 52.308 ;
     RECT  0.175 52.29 0.211 52.578 ;
     RECT  0.139 71.19 0.211 71.208 ;
     RECT  0.103 68.184 0.247 69.318 ;
     RECT  0.211 71.154 0.283 71.208 ;
     RECT  0.211 66.024 0.391 66.042 ;
     RECT  0.283 70.812 0.535 71.208 ;
     RECT  0.067 63.63 0.571 63.882 ;
     RECT  0.391 66.024 0.571 66.159 ;
     RECT  0.247 68.112 0.571 69.318 ;
     RECT  0.535 70.38 0.571 71.208 ;
     RECT  0.139 48.744 0.823 48.762 ;
     RECT  0.823 72 0.895 72.018 ;
     RECT  0.571 63.63 1.147 64.224 ;
     RECT  0.571 65.142 1.147 66.78 ;
     RECT  0.571 68.112 1.147 71.208 ;
     RECT  0.823 48.744 1.399 48.798 ;
     RECT  0.895 72 1.399 72.45 ;
     RECT  1.399 72 1.471 73.062 ;
     RECT  1.147 67.842 1.723 71.208 ;
     RECT  1.399 48.744 1.975 49.338 ;
     RECT  1.723 62.01 2.011 62.028 ;
     RECT  1.147 63.09 2.011 66.78 ;
     RECT  1.723 67.806 2.047 71.208 ;
     RECT  1.471 72 2.047 73.26 ;
     RECT  1.975 48.744 2.16 49.5 ;
     RECT  0.031 50.904 2.16 50.922 ;
     RECT  0.211 51.912 2.16 52.578 ;
     RECT  0.067 54.45 2.16 54.468 ;
     RECT  0.247 57.96 2.16 57.978 ;
     RECT  2.011 62.01 2.16 66.78 ;
     RECT  2.047 67.806 2.16 73.26 ;
     RECT  2.16 2.151 90.607 137.709 ;
     RECT  90.607 2.106 91.319 137.709 ;
     RECT  91.319 2.151 93.235 137.709 ;
     RECT  93.235 2.106 93.631 137.709 ;
     RECT  93.631 2.07 94.379 137.709 ;
     RECT  94.379 2.106 94.523 137.709 ;
     RECT  94.523 2.151 95.323 137.709 ;
     RECT  95.323 2.106 96.431 137.709 ;
     RECT  96.431 2.151 137.808 137.709 ;
     RECT  137.808 73.386 138.227 79.704 ;
     RECT  138.227 74.466 138.551 79.704 ;
     RECT  138.551 74.466 138.623 77.994 ;
     RECT  138.227 73.386 138.803 73.494 ;
     RECT  138.803 73.386 138.875 73.404 ;
     RECT  138.551 78.876 139.055 79.704 ;
     RECT  138.623 74.466 139.127 77.184 ;
     RECT  138.623 77.976 139.127 77.994 ;
     RECT  139.127 75.546 139.163 75.798 ;
     RECT  139.127 76.554 139.199 77.184 ;
     RECT  139.163 75.78 139.235 75.798 ;
     RECT  139.199 77.166 139.271 77.184 ;
     RECT  139.055 79.416 139.847 79.704 ;
     RECT  139.127 74.466 139.855 74.484 ;
     RECT  139.847 79.416 139.919 79.434 ;
     RECT  139.855 74.466 139.955 74.682 ;
    LAYER M3 ;
     RECT  94.176 0.091 94.194 0.139 ;
     RECT  91.188 0.187 91.206 0.523 ;
     RECT  95.724 0.139 95.742 0.571 ;
     RECT  95.292 0.571 95.742 1.147 ;
     RECT  96.552 0.091 96.57 1.147 ;
     RECT  94.104 0.139 94.194 1.723 ;
     RECT  93.168 1.723 93.186 1.771 ;
     RECT  94.104 1.723 94.518 1.771 ;
     RECT  95.292 1.147 96.57 1.771 ;
     RECT  97.812 1.147 97.83 1.771 ;
     RECT  91.188 0.523 91.242 2.101 ;
     RECT  88.308 0.043 88.326 2.143 ;
     RECT  90.612 2.101 91.314 2.191 ;
     RECT  93.168 1.771 97.83 2.191 ;
     RECT  92.88 2.191 97.83 2.263 ;
     RECT  2.415 2.143 2.505 2.413 ;
     RECT  7.815 2.143 7.905 2.413 ;
     RECT  13.215 2.143 13.305 2.413 ;
     RECT  18.615 2.143 18.705 2.413 ;
     RECT  24.015 2.143 24.105 2.413 ;
     RECT  29.415 2.143 29.505 2.413 ;
     RECT  34.815 2.143 34.905 2.413 ;
     RECT  40.215 2.143 40.305 2.413 ;
     RECT  45.615 2.143 45.705 2.413 ;
     RECT  51.015 2.143 51.105 2.413 ;
     RECT  56.415 2.143 56.505 2.413 ;
     RECT  61.815 2.143 61.905 2.413 ;
     RECT  67.215 2.143 67.305 2.413 ;
     RECT  72.615 2.143 72.705 2.413 ;
     RECT  78.015 2.143 78.105 2.413 ;
     RECT  83.415 2.143 83.505 2.413 ;
     RECT  88.308 2.143 88.905 2.413 ;
     RECT  99.615 2.143 99.705 2.413 ;
     RECT  105.015 2.143 105.105 2.413 ;
     RECT  110.415 2.143 110.505 2.413 ;
     RECT  115.815 2.143 115.905 2.413 ;
     RECT  121.215 2.143 121.305 2.413 ;
     RECT  126.615 2.143 126.705 2.413 ;
     RECT  132.015 2.143 132.105 2.413 ;
     RECT  137.415 2.143 137.505 2.413 ;
     RECT  90.612 2.191 91.674 2.569 ;
     RECT  88.308 2.413 89.097 3.037 ;
     RECT  88.056 3.037 89.097 3.109 ;
     RECT  88.056 3.109 89.766 3.299 ;
     RECT  88.056 3.299 89.154 3.335 ;
     RECT  90.612 2.569 91.782 3.371 ;
     RECT  88.056 3.335 89.097 3.379 ;
     RECT  92.88 2.263 98.154 3.605 ;
     RECT  92.88 3.605 92.898 3.641 ;
     RECT  90.9 3.371 91.782 3.685 ;
     RECT  87.984 3.379 89.097 3.721 ;
     RECT  90.9 3.685 92.106 3.721 ;
     RECT  93.924 3.605 98.154 4.531 ;
     RECT  93.924 4.531 98.586 6.305 ;
     RECT  93.924 6.305 97.866 6.691 ;
     RECT  90.9 3.721 92.646 6.853 ;
     RECT  93.672 6.691 97.866 7.231 ;
     RECT  98.784 6.421 98.802 7.231 ;
     RECT  87.3 3.721 89.097 7.591 ;
     RECT  90.9 6.853 92.754 7.763 ;
     RECT  93.672 7.231 98.802 7.771 ;
     RECT  99.615 2.413 99.897 7.771 ;
     RECT  93.672 7.771 99.897 8.311 ;
     RECT  90.936 7.763 92.754 8.437 ;
     RECT  93.6 8.311 99.897 8.437 ;
     RECT  90.936 8.437 99.897 8.501 ;
     RECT  90.936 8.501 98.874 8.537 ;
     RECT  90.936 8.537 98.802 9.085 ;
     RECT  90.9 9.085 98.802 9.239 ;
     RECT  90.9 9.239 92.754 9.275 ;
     RECT  93.492 9.239 98.802 10.859 ;
     RECT  87.3 7.591 89.19 11.713 ;
     RECT  87.3 11.713 89.37 12.217 ;
     RECT  87.3 12.217 89.838 12.317 ;
     RECT  93.492 10.859 98.73 12.475 ;
     RECT  99.615 8.501 99.897 12.475 ;
     RECT  87.3 12.317 89.766 12.785 ;
     RECT  90.9 9.275 92.646 12.901 ;
     RECT  93.492 12.475 99.897 12.901 ;
     RECT  87.3 12.785 89.694 12.929 ;
     RECT  90.9 12.901 99.897 13.127 ;
     RECT  93.492 13.127 99.897 13.937 ;
     RECT  93.924 13.937 99.897 13.973 ;
     RECT  87.3 12.929 89.658 14.521 ;
     RECT  90.9 13.127 92.646 14.909 ;
     RECT  93.924 13.973 98.802 16.123 ;
     RECT  93.744 16.123 98.802 16.141 ;
     RECT  99.615 13.973 99.897 16.141 ;
     RECT  93.744 16.141 99.897 16.169 ;
     RECT  93.924 16.169 99.897 16.259 ;
     RECT  93.924 16.259 98.766 16.295 ;
     RECT  93.924 16.295 98.658 16.565 ;
     RECT  93.924 16.565 98.622 16.637 ;
     RECT  98.604 16.637 98.622 16.673 ;
     RECT  90.936 14.909 92.646 16.951 ;
     RECT  87.3 14.521 90.054 17.213 ;
     RECT  90.9 16.951 92.646 17.221 ;
     RECT  87.3 17.213 89.802 17.249 ;
     RECT  90.9 17.221 92.718 17.311 ;
     RECT  90.612 17.311 92.718 17.339 ;
     RECT  87.3 17.249 89.622 17.491 ;
     RECT  87.192 17.491 89.622 17.581 ;
     RECT  87.048 17.581 89.622 17.645 ;
     RECT  90.612 17.339 92.646 17.915 ;
     RECT  93.924 16.637 97.866 20.191 ;
     RECT  87.3 17.645 89.622 20.345 ;
     RECT  87.3 20.345 89.586 20.731 ;
     RECT  90.9 17.915 92.646 20.965 ;
     RECT  90.9 20.965 92.718 21.001 ;
     RECT  90.9 21.001 92.898 21.211 ;
     RECT  90.864 21.211 92.898 21.263 ;
     RECT  86.904 20.731 89.586 21.469 ;
     RECT  90.936 21.263 92.898 21.659 ;
     RECT  98.82 22.351 98.838 22.469 ;
     RECT  93.816 20.191 97.866 22.477 ;
     RECT  93.816 22.477 98.514 23.359 ;
     RECT  93.816 23.359 98.622 23.431 ;
     RECT  93.816 23.431 98.73 23.666 ;
     RECT  86.904 21.469 90.054 23.827 ;
     RECT  90.936 21.659 92.718 23.827 ;
     RECT  93.816 23.666 98.694 24.089 ;
     RECT  86.904 23.827 92.718 24.169 ;
     RECT  93.816 24.089 98.478 24.503 ;
     RECT  85.968 24.205 85.986 24.511 ;
     RECT  86.904 24.169 92.79 24.511 ;
     RECT  85.968 24.511 92.79 24.539 ;
     RECT  86.652 24.539 92.79 24.935 ;
     RECT  86.904 24.935 92.79 25.277 ;
     RECT  90.756 25.277 92.79 26.519 ;
     RECT  90.756 26.519 92.43 26.627 ;
     RECT  90.756 26.627 92.394 26.797 ;
     RECT  90.648 26.797 92.394 27.481 ;
     RECT  90.576 27.481 92.394 27.707 ;
     RECT  86.904 25.277 89.766 27.751 ;
     RECT  86.328 27.751 89.766 27.835 ;
     RECT  86.184 27.835 89.766 27.875 ;
     RECT  93.816 24.503 98.262 27.877 ;
     RECT  93.816 27.877 98.334 27.979 ;
     RECT  90.576 27.707 92.358 27.985 ;
     RECT  93.816 27.979 98.37 28.021 ;
     RECT  99.615 16.259 99.897 28.021 ;
     RECT  93.816 28.021 98.586 28.211 ;
     RECT  93.816 28.211 98.514 28.363 ;
     RECT  93.744 28.363 98.514 28.409 ;
     RECT  99.324 28.021 99.897 28.409 ;
     RECT  86.436 27.875 89.766 28.417 ;
     RECT  90.54 27.985 92.358 28.417 ;
     RECT  86.436 28.417 92.358 28.445 ;
     RECT  93.924 28.409 98.37 28.445 ;
     RECT  86.904 28.445 92.358 28.859 ;
     RECT  90.648 28.859 92.358 28.949 ;
     RECT  90.684 28.949 92.358 29.057 ;
     RECT  90.684 29.057 92.322 29.219 ;
     RECT  86.904 28.859 89.766 29.327 ;
     RECT  93.924 28.445 98.262 29.461 ;
     RECT  90.972 29.219 92.322 31.351 ;
     RECT  93.384 29.461 98.262 31.351 ;
     RECT  86.904 29.327 89.37 32.233 ;
     RECT  86.904 32.233 89.406 32.305 ;
     RECT  86.904 32.305 89.586 32.341 ;
     RECT  86.904 32.341 89.658 32.459 ;
     RECT  86.904 32.459 89.586 32.495 ;
     RECT  90.972 31.351 98.262 32.539 ;
     RECT  86.904 32.495 89.442 33.349 ;
     RECT  90.648 32.539 98.262 33.809 ;
     RECT  90.648 33.809 92.322 36.275 ;
     RECT  86.904 33.349 89.478 36.391 ;
     RECT  90.936 36.275 92.322 36.661 ;
     RECT  90.936 36.661 92.43 36.931 ;
     RECT  93.168 33.809 98.262 36.931 ;
     RECT  90.936 36.931 98.262 37.129 ;
     RECT  90.936 37.129 98.298 37.201 ;
     RECT  86.904 36.391 90.054 37.363 ;
     RECT  90.936 37.201 98.406 37.363 ;
     RECT  86.904 37.363 98.406 37.391 ;
     RECT  93.528 37.391 98.406 37.435 ;
     RECT  99.615 28.409 99.897 37.471 ;
     RECT  93.528 37.435 98.802 37.589 ;
     RECT  99.576 37.471 99.897 37.589 ;
     RECT  93.528 37.589 98.658 37.625 ;
     RECT  93.528 37.625 98.262 40.441 ;
     RECT  86.904 37.391 92.79 40.559 ;
     RECT  93.528 40.441 98.298 40.631 ;
     RECT  92.304 40.559 92.79 40.711 ;
     RECT  93.528 40.631 98.262 40.711 ;
     RECT  86.904 40.559 91.566 41.135 ;
     RECT  92.304 40.711 98.262 41.135 ;
     RECT  86.904 41.135 90.378 41.143 ;
     RECT  92.304 41.135 94.662 41.213 ;
     RECT  86.328 41.143 90.378 41.215 ;
     RECT  86.256 41.215 90.378 41.369 ;
     RECT  92.304 41.213 94.554 41.369 ;
     RECT  86.256 41.369 89.406 41.441 ;
     RECT  90.144 41.369 90.378 41.549 ;
     RECT  85.5 42.223 85.518 42.295 ;
     RECT  86.364 41.441 89.406 42.295 ;
     RECT  85.5 42.295 89.406 42.521 ;
     RECT  85.5 42.521 85.842 42.715 ;
     RECT  84.852 42.715 85.842 42.719 ;
     RECT  84.852 42.719 85.698 42.755 ;
     RECT  84.888 42.755 85.698 43.133 ;
     RECT  86.796 42.521 89.406 44.879 ;
     RECT  90.36 41.549 90.378 45.355 ;
     RECT  91.188 41.135 91.566 45.355 ;
     RECT  90.36 45.355 91.566 45.689 ;
     RECT  51.015 2.413 51.297 46.471 ;
     RECT  84.888 43.133 85.662 46.501 ;
     RECT  50.904 46.471 51.297 46.645 ;
     RECT  84.816 46.501 85.662 46.651 ;
     RECT  84.816 46.651 85.77 46.849 ;
     RECT  56.415 2.413 56.697 46.921 ;
     RECT  84.816 46.849 85.842 47.039 ;
     RECT  50.76 46.645 51.297 47.047 ;
     RECT  29.415 2.413 29.697 47.191 ;
     RECT  56.415 46.921 57.474 47.191 ;
     RECT  82.656 47.047 82.674 47.219 ;
     RECT  45.615 2.413 45.897 47.461 ;
     RECT  47.34 47.419 47.358 47.461 ;
     RECT  55.836 47.191 57.474 47.461 ;
     RECT  45.615 47.461 46.026 47.515 ;
     RECT  47.016 47.461 47.43 47.551 ;
     RECT  55.152 47.461 57.474 47.579 ;
     RECT  24.015 2.413 24.297 47.587 ;
     RECT  45.072 47.515 46.026 47.587 ;
     RECT  46.8 47.551 47.43 47.587 ;
     RECT  45.072 47.587 47.43 47.615 ;
     RECT  50.184 47.047 51.297 47.615 ;
     RECT  45.504 47.615 47.43 47.659 ;
     RECT  48.276 47.461 48.294 47.659 ;
     RECT  23.364 47.587 24.426 47.731 ;
     RECT  45.504 47.659 48.294 47.759 ;
     RECT  32.94 47.731 32.958 47.821 ;
     RECT  28.692 47.191 29.697 47.834 ;
     RECT  31.176 47.695 31.194 47.848 ;
     RECT  23.364 47.731 25.146 47.849 ;
     RECT  31.032 47.848 31.194 47.849 ;
     RECT  27.756 47.191 27.954 47.857 ;
     RECT  23.688 47.849 25.146 47.885 ;
     RECT  31.032 47.849 31.05 47.885 ;
     RECT  45.504 47.759 47.286 47.885 ;
     RECT  27.648 47.857 27.954 47.893 ;
     RECT  47.016 47.885 47.286 47.957 ;
     RECT  45.504 47.885 46.098 47.981 ;
     RECT  50.472 47.615 51.297 47.993 ;
     RECT  32.94 47.821 33.066 48.001 ;
     RECT  55.152 47.579 57.366 48.001 ;
     RECT  47.196 47.957 47.286 48.029 ;
     RECT  55.008 48.001 57.366 48.119 ;
     RECT  26.676 47.965 26.694 48.127 ;
     RECT  27.468 47.893 27.954 48.127 ;
     RECT  54.144 47.893 54.162 48.199 ;
     RECT  55.008 48.119 55.242 48.199 ;
     RECT  54.144 48.199 55.242 48.227 ;
     RECT  56.016 48.119 57.294 48.227 ;
     RECT  34.815 2.413 35.097 48.235 ;
     RECT  4.428 47.929 4.446 48.271 ;
     RECT  22.824 47.929 22.842 48.299 ;
     RECT  32.94 48.001 33.102 48.361 ;
     RECT  84.816 47.039 85.662 48.361 ;
     RECT  53.244 48.361 53.262 48.379 ;
     RECT  86.796 44.879 87.57 48.389 ;
     RECT  3.852 48.271 4.446 48.397 ;
     RECT  26.676 48.127 27.954 48.397 ;
     RECT  28.692 47.834 29.934 48.397 ;
     RECT  41.58 48.271 41.598 48.397 ;
     RECT  52.74 48.379 53.262 48.425 ;
     RECT  34.056 48.397 34.074 48.433 ;
     RECT  34.815 48.235 35.802 48.433 ;
     RECT  26.496 48.397 29.934 48.461 ;
     RECT  32.94 48.361 33.138 48.461 ;
     RECT  45.504 47.981 46.062 48.469 ;
     RECT  26.496 48.461 27.99 48.497 ;
     RECT  17.784 48.469 17.802 48.505 ;
     RECT  18.615 2.413 18.897 48.505 ;
     RECT  21.06 48.469 21.078 48.505 ;
     RECT  32.94 48.461 33.102 48.533 ;
     RECT  40.215 2.413 40.497 48.541 ;
     RECT  41.58 48.397 42.066 48.541 ;
     RECT  3.852 48.397 4.554 48.659 ;
     RECT  25.704 48.619 25.722 48.659 ;
     RECT  26.964 48.497 27.99 48.659 ;
     RECT  40.215 48.541 42.066 48.659 ;
     RECT  52.884 48.425 53.262 48.659 ;
     RECT  13.215 2.413 13.497 48.667 ;
     RECT  17.784 48.505 18.897 48.695 ;
     RECT  84.816 48.361 85.734 48.695 ;
     RECT  22.788 48.469 22.806 48.731 ;
     RECT  50.616 47.993 51.297 48.739 ;
     RECT  0.144 48.739 0.162 48.775 ;
     RECT  4.32 48.659 4.554 48.811 ;
     RECT  18 48.695 18.897 48.811 ;
     RECT  21.06 48.505 21.294 48.811 ;
     RECT  14.832 48.541 14.85 48.839 ;
     RECT  38.772 48.703 38.79 48.901 ;
     RECT  26.964 48.659 27.918 48.929 ;
     RECT  40.215 48.659 41.778 48.929 ;
     RECT  50.616 48.739 51.786 48.929 ;
     RECT  21.06 48.811 21.366 48.937 ;
     RECT  34.056 48.433 35.802 48.937 ;
     RECT  38.376 48.901 39.186 48.937 ;
     RECT  20.988 48.937 21.474 48.973 ;
     RECT  22.536 48.811 22.734 48.973 ;
     RECT  20.448 48.973 22.734 48.989 ;
     RECT  26.964 48.929 27.882 49.001 ;
     RECT  30.888 48.001 30.906 49.001 ;
     RECT  50.616 48.929 51.75 49.001 ;
     RECT  53.244 48.659 53.262 49.001 ;
     RECT  20.448 48.989 20.466 49.009 ;
     RECT  23.688 47.885 24.426 49.009 ;
     RECT  50.616 49.001 51.642 49.009 ;
     RECT  21.276 48.989 22.734 49.037 ;
     RECT  38.16 48.937 39.186 49.037 ;
     RECT  38.16 49.037 38.394 49.073 ;
     RECT  45.432 48.469 46.062 49.081 ;
     RECT  47.268 48.029 47.286 49.081 ;
     RECT  56.415 48.227 57.294 49.081 ;
     RECT  58.356 49.009 58.374 49.081 ;
     RECT  59.832 47.047 59.85 49.081 ;
     RECT  21.924 49.037 22.734 49.109 ;
     RECT  34.056 48.937 35.874 49.109 ;
     RECT  50.58 49.009 51.642 49.195 ;
     RECT  4.32 48.811 5.13 49.199 ;
     RECT  20.412 49.009 20.466 49.199 ;
     RECT  22.104 49.109 22.734 49.199 ;
     RECT  29.415 48.461 29.934 49.207 ;
     RECT  22.608 49.199 22.734 49.235 ;
     RECT  50.508 49.195 51.642 49.235 ;
     RECT  40.215 48.929 41.598 49.243 ;
     RECT  54.684 48.227 55.242 49.243 ;
     RECT  18 48.811 19.422 49.271 ;
     RECT  45.432 49.081 47.286 49.307 ;
     RECT  0.144 48.775 0.846 49.315 ;
     RECT  56.415 49.081 58.374 49.315 ;
     RECT  48.276 47.759 48.294 49.343 ;
     RECT  50.616 49.235 51.642 49.343 ;
     RECT  49.644 49.279 49.662 49.351 ;
     RECT  56.415 49.315 58.554 49.351 ;
     RECT  59.796 49.081 59.85 49.351 ;
     RECT  34.815 49.109 35.874 49.441 ;
     RECT  4.32 49.199 4.338 49.469 ;
     RECT  49.5 49.351 49.734 49.469 ;
     RECT  56.415 49.351 59.922 49.469 ;
     RECT  0.144 49.315 1.422 49.477 ;
     RECT  2.415 2.413 2.697 49.477 ;
     RECT  38.304 49.073 38.394 49.505 ;
     RECT  47.016 49.307 47.286 49.513 ;
     RECT  38.376 49.505 38.394 49.541 ;
     RECT  84.816 48.695 85.662 49.541 ;
     RECT  39.132 49.037 39.186 49.549 ;
     RECT  39.96 49.243 41.598 49.549 ;
     RECT  33.084 48.533 33.102 49.577 ;
     RECT  59.292 49.469 59.922 49.577 ;
     RECT  56.415 49.469 58.554 49.579 ;
     RECT  56.304 49.579 58.554 49.613 ;
     RECT  84.816 49.541 85.194 49.621 ;
     RECT  23.688 49.009 24.534 49.649 ;
     RECT  56.304 49.613 56.697 49.649 ;
     RECT  34.815 49.441 35.946 49.711 ;
     RECT  39.132 49.549 41.598 49.739 ;
     RECT  43.812 49.621 43.83 49.739 ;
     RECT  39.132 49.739 40.497 49.783 ;
     RECT  42.912 49.621 42.93 49.783 ;
     RECT  42.696 49.783 42.93 49.855 ;
     RECT  13.215 48.667 13.95 49.891 ;
     RECT  23.832 49.649 24.534 49.891 ;
     RECT  34.815 49.711 36.09 49.891 ;
     RECT  47.016 49.513 47.502 49.891 ;
     RECT  54.108 49.243 55.242 49.963 ;
     RECT  95.796 41.135 98.262 49.963 ;
     RECT  99.615 37.589 99.897 49.963 ;
     RECT  29.304 49.207 29.934 49.981 ;
     RECT  23.832 49.891 24.57 50.008 ;
     RECT  22.608 49.235 22.662 50.009 ;
     RECT  37.008 49.783 37.026 50.009 ;
     RECT  42.696 49.855 43.614 50.009 ;
     RECT  31.716 49.855 31.734 50.017 ;
     RECT  42.696 50.009 43.074 50.017 ;
     RECT  11.592 49.627 11.61 50.045 ;
     RECT  23.832 50.008 24.642 50.045 ;
     RECT  84.708 49.621 85.194 50.059 ;
     RECT  10.836 49.891 10.854 50.117 ;
     RECT  12.672 49.891 13.95 50.125 ;
     RECT  42.552 50.017 43.074 50.125 ;
     RECT  83.415 2.413 83.697 50.125 ;
     RECT  84.492 50.059 85.194 50.125 ;
     RECT  42.444 50.125 43.074 50.141 ;
     RECT  69.372 49.981 69.39 50.141 ;
     RECT  42.444 50.141 42.93 50.153 ;
     RECT  70.92 50.107 70.938 50.153 ;
     RECT  29.304 49.981 30.078 50.161 ;
     RECT  31.464 50.017 31.734 50.161 ;
     RECT  29.304 50.161 32.274 50.189 ;
     RECT  42.444 50.153 42.714 50.189 ;
     RECT  54.108 49.963 55.386 50.279 ;
     RECT  32.184 50.189 32.274 50.299 ;
     RECT  32.184 50.299 32.31 50.333 ;
     RECT  95.796 49.963 99.897 50.333 ;
     RECT  32.22 50.333 32.31 50.351 ;
     RECT  34.056 49.109 34.074 50.359 ;
     RECT  34.815 49.891 36.162 50.359 ;
     RECT  25.884 49.621 25.902 50.389 ;
     RECT  25.884 50.389 26.118 50.431 ;
     RECT  26.964 49.001 27.846 50.431 ;
     RECT  32.22 50.351 32.238 50.459 ;
     RECT  24.015 50.045 24.642 50.549 ;
     RECT  47.016 49.891 47.934 50.557 ;
     RECT  49.5 49.469 49.662 50.593 ;
     RECT  47.016 50.557 48.006 50.657 ;
     RECT  48.996 50.593 49.662 50.701 ;
     RECT  54.108 50.279 55.242 50.779 ;
     RECT  34.02 50.359 34.074 50.791 ;
     RECT  56.34 49.649 56.697 50.791 ;
     RECT  5.112 49.199 5.13 50.819 ;
     RECT  50.688 49.343 51.642 50.819 ;
     RECT  11.736 50.125 13.95 50.827 ;
     RECT  18 49.271 18.897 50.827 ;
     RECT  22.644 50.009 22.662 50.827 ;
     RECT  24.015 50.549 24.57 50.827 ;
     RECT  4.068 50.089 4.086 50.863 ;
     RECT  0.144 49.477 2.697 50.899 ;
     RECT  25.884 50.431 27.846 50.899 ;
     RECT  33.948 50.791 34.074 50.899 ;
     RECT  34.815 50.359 36.306 50.899 ;
     RECT  53.712 50.779 55.242 50.899 ;
     RECT  25.884 50.899 28.53 50.923 ;
     RECT  29.304 50.189 30.798 50.923 ;
     RECT  3.96 50.863 4.086 50.935 ;
     RECT  14.868 50.863 14.886 50.963 ;
     RECT  16.092 48.937 16.11 51.019 ;
     RECT  33.948 50.899 36.306 51.061 ;
     RECT  25.884 50.923 30.798 51.089 ;
     RECT  53.568 50.899 55.242 51.089 ;
     RECT  57.492 49.613 58.554 51.089 ;
     RECT  10.224 51.097 10.242 51.133 ;
     RECT  11.052 50.827 13.95 51.133 ;
     RECT  33.084 50.827 33.102 51.133 ;
     RECT  33.912 51.061 36.306 51.133 ;
     RECT  28.8 51.089 29.754 51.161 ;
     RECT  3.816 50.935 4.086 51.205 ;
     RECT  16.092 51.019 16.218 51.241 ;
     RECT  41.328 49.739 41.598 51.241 ;
     RECT  59.292 49.577 59.814 51.241 ;
     RECT  22.644 50.827 24.57 51.269 ;
     RECT  33.084 51.133 36.306 51.269 ;
     RECT  20.448 49.199 20.466 51.331 ;
     RECT  21.564 50.899 21.582 51.331 ;
     RECT  53.568 51.089 54.27 51.359 ;
     RECT  10.224 51.133 13.95 51.367 ;
     RECT  9.648 51.367 13.95 51.431 ;
     RECT  48.276 50.701 49.662 51.431 ;
     RECT  50.688 50.819 51.606 51.431 ;
     RECT  17.712 50.827 18.897 51.439 ;
     RECT  21.564 51.331 21.69 51.439 ;
     RECT  45.432 49.307 46.134 51.439 ;
     RECT  47.016 50.657 47.502 51.439 ;
     RECT  48.528 51.431 49.662 51.439 ;
     RECT  59.292 51.241 59.886 51.439 ;
     RECT  16.092 51.241 16.398 51.451 ;
     RECT  20.448 51.331 20.61 51.475 ;
     RECT  0.036 50.899 2.697 51.511 ;
     RECT  3.816 51.205 4.446 51.511 ;
     RECT  7.815 2.413 8.097 51.511 ;
     RECT  20.448 51.475 20.682 51.511 ;
     RECT  21.456 51.439 21.69 51.511 ;
     RECT  17.712 51.439 18.954 51.539 ;
     RECT  45.036 51.439 47.502 51.539 ;
     RECT  48.528 51.439 49.734 51.539 ;
     RECT  59.292 51.439 59.958 51.539 ;
     RECT  58.536 51.089 58.554 51.601 ;
     RECT  59.292 51.539 59.886 51.601 ;
     RECT  48.528 51.539 49.122 51.629 ;
     RECT  52.776 51.403 52.794 51.629 ;
     RECT  16.056 51.451 16.398 51.637 ;
     RECT  20.448 51.511 21.69 51.637 ;
     RECT  41.328 51.241 41.706 51.637 ;
     RECT  42.444 50.189 42.642 51.637 ;
     RECT  20.268 51.637 21.69 51.673 ;
     RECT  45.036 51.539 46.17 51.673 ;
     RECT  15.984 51.637 16.398 51.677 ;
     RECT  19.656 51.673 21.69 51.691 ;
     RECT  6.84 51.133 6.858 51.701 ;
     RECT  12.348 51.431 13.95 51.701 ;
     RECT  29.304 51.161 29.754 51.701 ;
     RECT  12.528 51.701 13.95 51.709 ;
     RECT  19.656 51.691 21.726 51.737 ;
     RECT  41.328 51.637 42.822 51.737 ;
     RECT  17.712 51.539 18.897 51.745 ;
     RECT  16.056 51.677 16.146 51.773 ;
     RECT  16.056 51.773 16.11 51.809 ;
     RECT  19.656 51.737 21.654 51.809 ;
     RECT  38.772 49.783 40.497 51.871 ;
     RECT  41.328 51.737 42.21 51.871 ;
     RECT  0.036 51.511 4.446 51.899 ;
     RECT  7.815 51.511 8.73 51.899 ;
     RECT  9.648 51.431 11.574 51.943 ;
     RECT  38.772 51.871 42.21 51.971 ;
     RECT  22.644 51.269 23.166 52.051 ;
     RECT  7.815 51.899 8.154 52.079 ;
     RECT  0.036 51.899 3.978 52.169 ;
     RECT  9.18 51.943 11.574 52.169 ;
     RECT  12.528 51.709 14.13 52.169 ;
     RECT  11.592 52.171 11.61 52.211 ;
     RECT  9.18 52.169 10.854 52.241 ;
     RECT  38.772 51.971 41.706 52.241 ;
     RECT  9.936 52.241 10.854 52.313 ;
     RECT  54.108 51.359 54.27 52.321 ;
     RECT  55.08 51.089 55.242 52.321 ;
     RECT  33.336 51.269 36.306 52.411 ;
     RECT  0.036 52.169 3.834 52.439 ;
     RECT  10.152 52.313 10.854 52.439 ;
     RECT  38.772 52.241 41.562 52.445 ;
     RECT  33.336 52.411 37.062 52.447 ;
     RECT  43.596 52.411 43.614 52.447 ;
     RECT  54.108 52.321 55.242 52.447 ;
     RECT  56.34 50.791 56.754 52.447 ;
     RECT  58.536 51.601 59.886 52.447 ;
     RECT  38.772 52.445 41.454 52.483 ;
     RECT  54.108 52.447 56.754 52.493 ;
     RECT  22.644 52.051 23.202 52.519 ;
     RECT  24.015 51.269 24.57 52.519 ;
     RECT  58.536 52.447 60.318 52.519 ;
     RECT  19.728 51.809 21.654 52.547 ;
     RECT  33.084 52.447 37.062 52.547 ;
     RECT  54.108 52.493 55.242 52.547 ;
     RECT  33.408 52.547 37.062 52.583 ;
     RECT  38.376 52.483 41.454 52.583 ;
     RECT  17.1 51.745 18.897 52.591 ;
     RECT  19.728 52.547 20.502 52.591 ;
     RECT  58.536 52.519 60.426 52.591 ;
     RECT  38.52 52.583 41.454 52.619 ;
     RECT  9.18 52.241 9.198 52.709 ;
     RECT  33.408 52.583 36.702 52.709 ;
     RECT  54.108 52.547 55.062 52.744 ;
     RECT  16.056 51.809 16.074 52.745 ;
     RECT  38.772 52.619 41.454 52.745 ;
     RECT  17.1 52.591 20.502 52.753 ;
     RECT  49.86 51.601 49.878 52.753 ;
     RECT  50.688 51.431 51.39 52.753 ;
     RECT  58.536 52.591 60.462 52.753 ;
     RECT  54.036 52.744 55.062 52.781 ;
     RECT  58.5 52.753 60.462 52.781 ;
     RECT  33.408 52.709 36.486 52.853 ;
     RECT  16.812 52.753 20.502 52.889 ;
     RECT  30.78 51.089 30.798 52.889 ;
     RECT  33.408 52.853 36.45 52.889 ;
     RECT  52.452 51.709 52.47 52.889 ;
     RECT  13.176 52.169 14.13 52.939 ;
     RECT  33.408 52.889 36.378 52.979 ;
     RECT  38.772 52.745 41.31 52.979 ;
     RECT  43.596 52.447 43.686 52.979 ;
     RECT  13.176 52.939 14.202 53.015 ;
     RECT  19.836 52.889 20.502 53.015 ;
     RECT  44.568 51.673 46.17 53.023 ;
     RECT  58.5 52.781 60.138 53.023 ;
     RECT  44.46 53.023 46.17 53.051 ;
     RECT  56.232 52.493 56.754 53.059 ;
     RECT  57.492 51.089 57.726 53.059 ;
     RECT  13.176 53.015 14.13 53.095 ;
     RECT  45.288 53.051 46.17 53.131 ;
     RECT  47.016 51.539 47.502 53.131 ;
     RECT  6.804 51.943 6.822 53.249 ;
     RECT  39.168 52.979 41.31 53.285 ;
     RECT  29.304 51.701 29.697 53.293 ;
     RECT  22.644 52.519 24.57 53.401 ;
     RECT  16.812 52.889 18.897 53.527 ;
     RECT  22.644 53.401 24.606 53.599 ;
     RECT  56.232 53.059 57.726 53.599 ;
     RECT  58.464 53.023 60.138 53.599 ;
     RECT  15.948 52.951 15.966 53.635 ;
     RECT  15.624 53.635 15.966 53.663 ;
     RECT  39.168 53.285 40.497 53.851 ;
     RECT  25.884 51.089 27.918 53.905 ;
     RECT  48.996 51.629 49.122 53.941 ;
     RECT  49.86 52.753 51.39 53.941 ;
     RECT  64.62 53.905 64.638 53.941 ;
     RECT  48.744 53.941 49.122 54.043 ;
     RECT  49.86 53.941 51.426 54.043 ;
     RECT  25.884 53.905 28.17 54.059 ;
     RECT  56.232 53.599 60.138 54.139 ;
     RECT  45.288 53.131 47.502 54.239 ;
     RECT  33.408 52.979 36.342 54.301 ;
     RECT  13.104 53.095 14.13 54.329 ;
     RECT  48.744 54.043 51.426 54.329 ;
     RECT  54.108 52.781 55.062 54.337 ;
     RECT  31.356 53.941 31.374 54.373 ;
     RECT  33.408 54.301 36.882 54.373 ;
     RECT  29.088 53.293 29.697 54.401 ;
     RECT  31.356 54.373 31.698 54.409 ;
     RECT  39.06 53.851 40.497 54.409 ;
     RECT  31.356 54.409 31.842 54.481 ;
     RECT  56.232 54.139 60.282 54.571 ;
     RECT  56.232 54.571 60.354 54.599 ;
     RECT  19.836 53.015 20.466 54.607 ;
     RECT  64.332 53.941 64.638 54.643 ;
     RECT  64.332 54.643 65.322 54.679 ;
     RECT  62.964 52.591 62.982 54.707 ;
     RECT  16.776 53.527 18.897 54.715 ;
     RECT  48.744 54.329 49.122 54.715 ;
     RECT  49.86 54.329 51.426 54.715 ;
     RECT  53.748 54.337 55.062 54.715 ;
     RECT  56.232 54.599 56.754 54.715 ;
     RECT  86.868 48.389 87.57 54.715 ;
     RECT  91.188 45.689 91.566 54.715 ;
     RECT  92.304 41.369 92.79 54.715 ;
     RECT  93.528 41.369 94.554 54.715 ;
     RECT  22.644 53.599 24.786 54.743 ;
     RECT  64.26 54.679 65.322 54.749 ;
     RECT  31.356 54.481 32.166 54.751 ;
     RECT  44.46 53.051 44.478 54.751 ;
     RECT  57.96 54.599 60.354 54.751 ;
     RECT  91.152 54.715 91.566 54.751 ;
     RECT  92.304 54.715 94.554 54.751 ;
     RECT  33.084 54.373 36.882 54.841 ;
     RECT  61.815 2.413 62.097 54.841 ;
     RECT  90.36 45.689 90.378 54.841 ;
     RECT  91.152 54.751 94.554 54.841 ;
     RECT  30.744 54.751 32.166 54.877 ;
     RECT  32.904 54.841 36.882 54.877 ;
     RECT  43.596 52.979 43.614 54.877 ;
     RECT  44.46 54.751 44.55 54.877 ;
     RECT  45.288 54.239 45.954 54.877 ;
     RECT  25.884 54.059 28.062 54.905 ;
     RECT  38.844 54.409 40.497 54.905 ;
     RECT  53.748 54.715 56.754 54.905 ;
     RECT  48.348 54.715 49.122 54.907 ;
     RECT  49.86 54.715 51.498 54.913 ;
     RECT  86.868 54.715 87.606 54.913 ;
     RECT  88.416 44.879 89.406 54.913 ;
     RECT  43.596 54.877 45.954 54.941 ;
     RECT  49.86 54.913 52.038 54.949 ;
     RECT  30.672 54.877 36.882 54.977 ;
     RECT  64.584 54.749 65.322 54.977 ;
     RECT  3.816 52.439 3.834 54.985 ;
     RECT  25.956 54.905 28.062 55.013 ;
     RECT  57.96 54.751 60.462 55.013 ;
     RECT  61.236 54.841 62.73 55.013 ;
     RECT  30.852 54.977 36.882 55.049 ;
     RECT  16.74 54.715 18.897 55.111 ;
     RECT  19.836 54.607 20.574 55.111 ;
     RECT  59.544 55.013 60.462 55.111 ;
     RECT  26.1 55.013 28.062 55.139 ;
     RECT  90.36 54.841 94.554 55.139 ;
     RECT  16.74 55.111 20.574 55.147 ;
     RECT  21.636 52.547 21.654 55.147 ;
     RECT  86.868 54.913 89.406 55.147 ;
     RECT  90.36 55.139 90.378 55.147 ;
     RECT  91.152 55.139 94.554 55.175 ;
     RECT  48.276 54.907 49.122 55.183 ;
     RECT  49.86 54.949 52.11 55.183 ;
     RECT  5.688 55.183 5.706 55.243 ;
     RECT  9.108 55.111 9.126 55.243 ;
     RECT  29.16 54.401 29.697 55.247 ;
     RECT  91.224 55.175 94.554 55.247 ;
     RECT  95.796 50.333 98.262 55.247 ;
     RECT  47.016 54.239 47.502 55.255 ;
     RECT  48.276 55.183 52.11 55.255 ;
     RECT  47.016 55.255 52.11 55.283 ;
     RECT  53.748 54.905 54.63 55.283 ;
     RECT  8.928 55.243 9.126 55.291 ;
     RECT  10.152 52.439 10.17 55.291 ;
     RECT  13.215 54.329 14.13 55.339 ;
     RECT  5.544 55.243 5.706 55.381 ;
     RECT  6.66 55.291 6.858 55.381 ;
     RECT  64.728 54.977 65.322 55.381 ;
     RECT  5.544 55.381 6.858 55.409 ;
     RECT  61.815 55.013 62.73 55.409 ;
     RECT  16.74 55.147 21.654 55.417 ;
     RECT  67.215 2.413 67.497 55.417 ;
     RECT  7.815 52.079 8.097 55.453 ;
     RECT  8.928 55.291 10.17 55.453 ;
     RECT  15.624 53.663 15.642 55.483 ;
     RECT  16.416 55.417 21.654 55.483 ;
     RECT  7.815 55.453 10.17 55.489 ;
     RECT  11.772 52.321 11.79 55.489 ;
     RECT  30.924 55.049 36.882 55.489 ;
     RECT  15.624 55.483 21.654 55.517 ;
     RECT  64.728 55.381 65.394 55.517 ;
     RECT  7.815 55.489 10.314 55.525 ;
     RECT  11.628 55.489 11.79 55.525 ;
     RECT  26.784 55.139 28.062 55.553 ;
     RECT  95.904 55.247 98.262 55.553 ;
     RECT  7.74 55.525 10.314 55.561 ;
     RECT  45.615 54.941 45.954 55.561 ;
     RECT  47.016 55.283 49.122 55.561 ;
     RECT  49.86 55.283 52.11 55.561 ;
     RECT  30.924 55.489 37.026 55.589 ;
     RECT  64.728 55.517 64.782 55.589 ;
     RECT  66.708 55.417 67.497 55.589 ;
     RECT  82.656 55.489 82.674 55.589 ;
     RECT  19.728 55.517 21.654 55.651 ;
     RECT  22.716 54.743 24.786 55.651 ;
     RECT  15.624 55.517 18.897 55.679 ;
     RECT  5.544 55.409 6.678 55.715 ;
     RECT  7.488 55.561 10.314 55.715 ;
     RECT  31.896 55.589 37.026 55.715 ;
     RECT  11.556 55.525 11.79 55.723 ;
     RECT  5.544 55.715 6.21 55.751 ;
     RECT  7.74 55.715 10.314 55.751 ;
     RECT  43.596 54.941 44.766 55.759 ;
     RECT  45.615 55.561 49.122 55.759 ;
     RECT  8.82 55.751 10.314 55.787 ;
     RECT  11.556 55.723 12.006 55.823 ;
     RECT  19.728 55.651 24.786 55.823 ;
     RECT  32.904 55.715 37.026 55.831 ;
     RECT  15.66 55.679 18.897 55.859 ;
     RECT  32.904 55.831 37.134 55.859 ;
     RECT  11.988 55.823 12.006 55.921 ;
     RECT  12.78 55.339 14.13 55.921 ;
     RECT  49.86 55.561 52.326 55.921 ;
     RECT  57.96 55.013 58.698 55.921 ;
     RECT  59.544 55.111 60.75 55.921 ;
     RECT  16.488 55.859 18.897 55.949 ;
     RECT  8.928 55.787 10.314 55.957 ;
     RECT  0.036 52.439 2.898 56.065 ;
     RECT  3.816 54.985 4.446 56.065 ;
     RECT  11.988 55.921 14.13 56.129 ;
     RECT  49.86 55.921 52.398 56.129 ;
     RECT  49.86 56.129 51.858 56.219 ;
     RECT  12.204 56.129 14.13 56.227 ;
     RECT  12.204 56.227 14.814 56.255 ;
     RECT  16.668 55.949 18.897 56.291 ;
     RECT  31.896 55.715 32.166 56.291 ;
     RECT  86.868 55.147 90.378 56.327 ;
     RECT  8.928 55.957 11.25 56.363 ;
     RECT  13.215 56.255 14.814 56.363 ;
     RECT  43.596 55.759 49.122 56.381 ;
     RECT  53.748 55.283 53.766 56.461 ;
     RECT  54.612 55.283 54.63 56.461 ;
     RECT  88.524 56.327 90.378 56.461 ;
     RECT  91.26 55.247 94.554 56.461 ;
     RECT  8.928 56.363 10.854 56.489 ;
     RECT  53.748 56.461 54.738 56.489 ;
     RECT  64.728 55.589 64.746 56.497 ;
     RECT  8.928 56.489 10.746 56.561 ;
     RECT  43.596 56.381 46.458 56.561 ;
     RECT  57.96 55.921 60.75 56.561 ;
     RECT  88.524 56.461 94.554 56.561 ;
     RECT  0.036 56.065 4.446 56.605 ;
     RECT  5.652 55.751 6.066 56.605 ;
     RECT  42.264 55.525 42.282 56.605 ;
     RECT  53.964 56.489 54.738 56.633 ;
     RECT  56.232 54.905 56.754 56.641 ;
     RECT  8.928 56.561 10.53 56.759 ;
     RECT  32.904 55.859 36.342 56.759 ;
     RECT  61.815 55.409 62.097 56.767 ;
     RECT  9.288 56.759 10.422 56.795 ;
     RECT  44.136 56.561 46.458 56.795 ;
     RECT  0.036 56.605 6.066 56.875 ;
     RECT  47.268 56.381 49.122 56.939 ;
     RECT  49.86 56.219 51.75 56.939 ;
     RECT  86.868 56.327 87.75 57.001 ;
     RECT  0.036 56.875 6.246 57.029 ;
     RECT  58.68 56.561 60.75 57.101 ;
     RECT  86.652 57.001 87.75 57.101 ;
     RECT  19.728 55.823 21.042 57.145 ;
     RECT  61.815 56.767 62.73 57.173 ;
     RECT  88.524 56.561 90.378 57.173 ;
     RECT  13.215 56.363 14.13 57.271 ;
     RECT  33.156 56.759 36.342 57.379 ;
     RECT  13.215 57.271 14.598 57.451 ;
     RECT  15.66 55.859 15.678 57.451 ;
     RECT  45.18 56.795 46.458 57.479 ;
     RECT  38.844 54.905 38.862 57.541 ;
     RECT  5.652 57.029 6.246 57.569 ;
     RECT  13.215 57.451 15.678 57.569 ;
     RECT  42.264 56.605 42.786 57.569 ;
     RECT  38.196 57.541 38.862 57.577 ;
     RECT  39.672 54.905 40.497 57.577 ;
     RECT  53.964 56.633 54.63 57.577 ;
     RECT  56.232 56.641 56.898 57.577 ;
     RECT  33.156 57.379 36.378 57.605 ;
     RECT  56.232 57.577 57.51 57.629 ;
     RECT  56.232 57.629 57.186 57.649 ;
     RECT  58.68 57.101 58.698 57.649 ;
     RECT  38.196 57.577 40.497 57.685 ;
     RECT  41.292 53.285 41.31 57.685 ;
     RECT  13.215 57.569 14.598 57.721 ;
     RECT  58.464 57.649 58.698 57.721 ;
     RECT  59.544 57.101 60.75 57.811 ;
     RECT  61.815 57.173 62.097 57.811 ;
     RECT  38.196 57.685 41.31 57.839 ;
     RECT  53.964 57.577 54.954 57.839 ;
     RECT  29.304 55.247 29.697 57.847 ;
     RECT  13.176 57.721 14.598 57.875 ;
     RECT  56.196 57.649 57.186 57.875 ;
     RECT  37.116 55.859 37.134 57.883 ;
     RECT  13.176 57.875 14.058 57.911 ;
     RECT  22.572 55.823 24.786 57.919 ;
     RECT  22.536 57.919 24.786 57.947 ;
     RECT  58.428 57.721 58.698 57.955 ;
     RECT  59.544 57.811 62.097 57.955 ;
     RECT  42.264 57.569 42.606 57.983 ;
     RECT  12.204 56.255 12.222 57.991 ;
     RECT  13.176 57.911 14.022 57.991 ;
     RECT  22.536 57.947 23.094 57.991 ;
     RECT  56.232 57.875 57.186 58.019 ;
     RECT  41.292 57.839 41.31 58.081 ;
     RECT  42.264 57.983 42.534 58.081 ;
     RECT  50.04 56.939 51.75 58.081 ;
     RECT  22.428 57.991 23.094 58.123 ;
     RECT  29.124 57.847 29.697 58.123 ;
     RECT  12.204 57.991 14.022 58.145 ;
     RECT  38.196 57.839 40.497 58.145 ;
     RECT  41.292 58.081 42.534 58.145 ;
     RECT  56.232 58.019 56.898 58.145 ;
     RECT  58.428 57.955 62.097 58.145 ;
     RECT  22.392 58.123 23.094 58.171 ;
     RECT  9.288 56.795 10.206 58.189 ;
     RECT  26.856 55.553 28.026 58.189 ;
     RECT  30.924 55.589 30.942 58.189 ;
     RECT  22.284 58.171 23.094 58.217 ;
     RECT  29.124 58.123 29.754 58.219 ;
     RECT  32.148 56.291 32.166 58.225 ;
     RECT  33.156 57.605 36.342 58.225 ;
     RECT  30.78 58.189 30.942 58.253 ;
     RECT  41.544 58.145 42.282 58.253 ;
     RECT  19.728 57.145 21.114 58.261 ;
     RECT  24.012 57.947 24.786 58.261 ;
     RECT  29.124 58.219 29.79 58.289 ;
     RECT  30.78 58.253 30.87 58.289 ;
     RECT  9.288 58.189 10.854 58.379 ;
     RECT  24.012 58.261 25.65 58.387 ;
     RECT  26.856 58.189 28.35 58.387 ;
     RECT  29.124 58.289 29.697 58.387 ;
     RECT  88.668 57.173 90.378 58.387 ;
     RECT  91.26 56.561 94.554 58.387 ;
     RECT  0.036 57.029 4.41 58.423 ;
     RECT  16.776 56.291 18.897 58.423 ;
     RECT  24.012 58.387 25.794 58.423 ;
     RECT  14.832 58.351 14.85 58.451 ;
     RECT  19.728 58.261 21.222 58.451 ;
     RECT  30.78 58.289 30.798 58.451 ;
     RECT  7.74 55.751 8.097 58.495 ;
     RECT  9.288 58.379 10.206 58.495 ;
     RECT  64.008 56.497 64.746 58.495 ;
     RECT  24.012 58.423 25.83 58.531 ;
     RECT  88.668 58.387 94.554 58.621 ;
     RECT  16.776 58.423 18.954 58.649 ;
     RECT  24.012 58.531 25.902 58.649 ;
     RECT  0.036 58.423 4.662 58.657 ;
     RECT  24.012 58.649 24.606 58.685 ;
     RECT  16.776 58.649 18.897 58.693 ;
     RECT  25.38 58.649 25.902 58.693 ;
     RECT  26.856 58.387 29.697 58.693 ;
     RECT  50.04 58.081 51.858 58.693 ;
     RECT  64.008 58.495 64.782 58.693 ;
     RECT  19.728 58.451 21.078 58.702 ;
     RECT  32.148 58.225 36.342 58.721 ;
     RECT  88.668 58.621 94.626 58.721 ;
     RECT  53.964 57.839 54.702 58.757 ;
     RECT  0.036 58.657 4.806 58.793 ;
     RECT  50.04 58.693 51.93 58.795 ;
     RECT  50.04 58.795 52.11 58.801 ;
     RECT  32.4 58.721 36.27 58.829 ;
     RECT  25.38 58.693 29.697 58.919 ;
     RECT  50.04 58.801 52.254 58.919 ;
     RECT  63.828 58.693 64.782 58.919 ;
     RECT  58.68 58.145 59.886 58.927 ;
     RECT  41.724 58.253 42.282 58.963 ;
     RECT  27 58.919 29.697 58.991 ;
     RECT  38.772 58.145 40.497 59.063 ;
     RECT  58.644 58.927 59.886 59.071 ;
     RECT  60.732 58.145 62.097 59.071 ;
     RECT  64.008 58.919 64.782 59.099 ;
     RECT  16.524 58.693 18.897 59.189 ;
     RECT  64.008 59.099 64.566 59.189 ;
     RECT  41.724 58.963 42.534 59.197 ;
     RECT  56.232 58.145 56.79 59.197 ;
     RECT  57.636 59.035 57.654 59.197 ;
     RECT  50.04 58.919 52.146 59.225 ;
     RECT  58.644 59.071 62.802 59.225 ;
     RECT  30.744 59.071 30.762 59.261 ;
     RECT  47.772 56.939 49.122 59.269 ;
     RECT  53.028 59.071 53.118 59.269 ;
     RECT  53.964 58.757 54.63 59.269 ;
     RECT  50.04 59.225 51.93 59.297 ;
     RECT  86.868 57.101 87.75 59.297 ;
     RECT  7.74 58.495 10.206 59.341 ;
     RECT  13.215 58.145 14.022 59.341 ;
     RECT  41.724 59.197 42.714 59.341 ;
     RECT  58.716 59.225 62.802 59.369 ;
     RECT  19.728 58.702 21.042 59.459 ;
     RECT  7.524 59.341 10.206 59.467 ;
     RECT  7.524 59.467 10.926 59.495 ;
     RECT  19.8 59.459 21.042 59.495 ;
     RECT  5.652 57.569 5.67 59.503 ;
     RECT  45.615 57.479 46.458 59.539 ;
     RECT  0.072 58.793 4.806 59.563 ;
     RECT  5.544 59.503 5.67 59.563 ;
     RECT  0.072 59.563 5.67 59.575 ;
     RECT  7.596 59.495 10.926 59.603 ;
     RECT  44.136 56.795 44.154 59.603 ;
     RECT  17.028 59.189 18.897 59.611 ;
     RECT  47.664 59.269 49.122 59.611 ;
     RECT  50.04 59.297 51.858 59.611 ;
     RECT  53.028 59.269 54.63 59.611 ;
     RECT  83.415 50.125 85.194 59.701 ;
     RECT  86.04 59.269 86.058 59.701 ;
     RECT  83.415 59.701 86.058 59.741 ;
     RECT  0.072 59.575 6.03 59.837 ;
     RECT  13.215 59.341 14.85 59.845 ;
     RECT  15.66 57.569 15.678 59.845 ;
     RECT  45.615 59.539 46.818 59.845 ;
     RECT  47.664 59.611 51.858 59.845 ;
     RECT  22.392 58.217 23.094 59.873 ;
     RECT  53.028 59.611 54.702 59.909 ;
     RECT  17.028 59.611 18.954 59.971 ;
     RECT  16.668 59.971 18.954 59.999 ;
     RECT  45.615 59.845 51.858 60.071 ;
     RECT  24.015 58.685 24.606 60.079 ;
     RECT  25.38 58.919 26.19 60.079 ;
     RECT  27.252 58.991 29.697 60.151 ;
     RECT  30.708 60.079 30.726 60.151 ;
     RECT  41.724 59.341 42.786 60.151 ;
     RECT  53.388 59.909 54.702 60.151 ;
     RECT  58.716 59.369 62.097 60.151 ;
     RECT  96.12 55.553 98.262 60.151 ;
     RECT  7.74 59.603 10.854 60.179 ;
     RECT  45.615 60.071 51.822 60.179 ;
     RECT  12.24 58.145 12.258 60.241 ;
     RECT  13.215 59.845 15.678 60.241 ;
     RECT  47.268 60.179 50.022 60.269 ;
     RECT  58.68 60.151 62.097 60.269 ;
     RECT  13.215 60.241 15.93 60.277 ;
     RECT  13.104 60.277 15.93 60.283 ;
     RECT  16.668 59.999 18.897 60.283 ;
     RECT  13.104 60.283 18.897 60.305 ;
     RECT  14.832 60.305 18.897 60.317 ;
     RECT  15.192 60.317 18.897 60.341 ;
     RECT  53.388 60.151 54.882 60.341 ;
     RECT  24.015 60.079 26.19 60.349 ;
     RECT  15.192 60.341 15.93 60.377 ;
     RECT  41.724 60.151 42.966 60.377 ;
     RECT  47.808 60.269 50.022 60.377 ;
     RECT  10.188 60.179 10.854 60.413 ;
     RECT  13.104 60.305 14.058 60.413 ;
     RECT  15.228 60.377 15.93 60.413 ;
     RECT  16.848 60.341 18.897 60.413 ;
     RECT  47.808 60.377 49.302 60.413 ;
     RECT  53.604 60.341 54.882 60.421 ;
     RECT  19.908 59.495 21.042 60.427 ;
     RECT  48.924 60.413 49.302 60.449 ;
     RECT  7.74 60.179 9.306 60.539 ;
     RECT  53.604 60.421 55.062 60.539 ;
     RECT  32.4 58.829 36.234 60.547 ;
     RECT  86.04 59.741 86.058 60.611 ;
     RECT  53.964 60.539 55.062 60.619 ;
     RECT  56.232 59.197 57.654 60.619 ;
     RECT  0.072 59.837 5.958 60.655 ;
     RECT  6.696 60.043 6.714 60.655 ;
     RECT  53.964 60.619 57.654 60.683 ;
     RECT  17.064 60.413 18.897 60.781 ;
     RECT  27.252 60.151 30.726 60.781 ;
     RECT  0.072 60.655 6.714 60.809 ;
     RECT  58.68 60.269 60.858 60.809 ;
     RECT  9.288 60.539 9.306 60.845 ;
     RECT  19.908 60.427 21.654 60.845 ;
     RECT  5.652 60.809 6.714 60.853 ;
     RECT  64.188 59.189 64.566 60.889 ;
     RECT  23.976 60.349 26.19 60.953 ;
     RECT  56.232 60.683 57.654 60.953 ;
     RECT  17.064 60.781 18.954 60.989 ;
     RECT  27.252 60.781 31.374 61.087 ;
     RECT  32.4 60.547 36.27 61.087 ;
     RECT  13.104 60.413 13.806 61.349 ;
     RECT  37.116 57.883 37.242 61.349 ;
     RECT  27.252 61.087 36.27 61.393 ;
     RECT  37.116 61.349 37.134 61.393 ;
     RECT  5.652 60.853 6.858 61.465 ;
     RECT  7.74 60.539 8.097 61.465 ;
     RECT  43.056 60.889 43.074 61.619 ;
     RECT  0.072 60.809 4.914 61.735 ;
     RECT  5.652 61.465 7.002 61.735 ;
     RECT  7.74 61.465 8.37 61.735 ;
     RECT  15.372 60.413 15.93 61.735 ;
     RECT  41.724 60.377 42.282 61.735 ;
     RECT  15.372 61.735 16.002 61.771 ;
     RECT  47.808 60.413 47.898 61.771 ;
     RECT  15.228 61.771 16.002 61.867 ;
     RECT  0.072 61.735 7.002 61.889 ;
     RECT  0.072 61.889 5.922 61.925 ;
     RECT  15.228 61.867 16.182 61.969 ;
     RECT  0.072 61.925 5.814 61.997 ;
     RECT  6.696 61.889 7.002 61.997 ;
     RECT  83.415 59.741 85.194 61.997 ;
     RECT  83.415 61.997 84.906 62.033 ;
     RECT  14.832 61.969 16.182 62.041 ;
     RECT  17.064 60.989 18.897 62.041 ;
     RECT  38.808 59.063 40.497 62.041 ;
     RECT  13.215 61.349 13.806 62.131 ;
     RECT  19.908 60.845 21.042 62.131 ;
     RECT  38.808 62.041 40.77 62.131 ;
     RECT  50.94 60.179 51.822 62.131 ;
     RECT  10.188 60.413 10.242 62.155 ;
     RECT  13.215 62.131 13.878 62.155 ;
     RECT  14.832 62.041 18.897 62.155 ;
     RECT  13.215 62.155 18.897 62.159 ;
     RECT  19.908 62.131 21.294 62.167 ;
     RECT  15.228 62.159 16.182 62.195 ;
     RECT  27.252 61.393 37.134 62.195 ;
     RECT  7.74 61.735 8.982 62.231 ;
     RECT  8.964 62.231 8.982 62.311 ;
     RECT  9.9 62.155 10.242 62.311 ;
     RECT  50.904 62.131 51.822 62.311 ;
     RECT  56.232 60.953 57.078 62.311 ;
     RECT  0.072 61.997 4.95 62.381 ;
     RECT  56.232 62.311 57.186 62.401 ;
     RECT  8.964 62.311 10.242 62.429 ;
     RECT  11.916 60.241 12.258 62.429 ;
     RECT  33.336 62.195 37.134 62.429 ;
     RECT  50.904 62.311 52.002 62.437 ;
     RECT  9.9 62.429 10.242 62.465 ;
     RECT  13.215 62.159 14.49 62.537 ;
     RECT  50.796 62.437 52.002 62.537 ;
     RECT  56.232 62.401 57.654 62.545 ;
     RECT  13.215 62.537 13.914 62.573 ;
     RECT  50.796 62.537 51.966 62.573 ;
     RECT  22.5 59.873 23.094 62.609 ;
     RECT  55.584 62.545 57.654 62.621 ;
     RECT  8.964 62.429 9.126 62.699 ;
     RECT  23.976 60.953 26.118 62.699 ;
     RECT  50.832 62.573 51.966 62.699 ;
     RECT  6.84 61.997 7.002 62.707 ;
     RECT  7.74 62.231 8.097 62.707 ;
     RECT  13.215 62.573 13.698 62.707 ;
     RECT  45.615 60.179 46.458 62.731 ;
     RECT  56.232 62.621 57.654 62.731 ;
     RECT  8.964 62.699 9.018 62.735 ;
     RECT  38.592 62.131 40.77 62.735 ;
     RECT  6.84 62.707 8.097 62.743 ;
     RECT  19.908 62.167 21.366 62.779 ;
     RECT  22.5 62.609 22.878 62.779 ;
     RECT  6.804 62.743 8.097 62.843 ;
     RECT  41.724 61.735 42.858 62.941 ;
     RECT  19.908 62.779 22.878 62.969 ;
     RECT  27.252 62.195 32.562 63.013 ;
     RECT  17.064 62.159 18.897 63.049 ;
     RECT  19.908 62.969 22.122 63.049 ;
     RECT  1.152 62.381 4.95 63.053 ;
     RECT  17.064 63.049 22.122 63.077 ;
     RECT  26.784 63.013 32.562 63.113 ;
     RECT  10.008 62.465 10.242 63.121 ;
     RECT  11.34 62.731 11.502 63.121 ;
     RECT  12.24 62.429 12.258 63.121 ;
     RECT  13.104 62.707 13.698 63.121 ;
     RECT  41.724 62.941 43.362 63.121 ;
     RECT  45.615 62.731 47.034 63.121 ;
     RECT  56.232 62.731 57.762 63.121 ;
     RECT  26.784 63.113 30.114 63.149 ;
     RECT  58.716 60.809 60.858 63.149 ;
     RECT  10.008 63.121 11.502 63.239 ;
     RECT  58.716 63.149 58.734 63.239 ;
     RECT  17.064 63.077 21.978 63.245 ;
     RECT  47.808 61.771 48.438 63.311 ;
     RECT  45.18 63.121 47.034 63.355 ;
     RECT  0.072 62.381 0.414 63.403 ;
     RECT  1.152 63.053 1.17 63.403 ;
     RECT  45 63.355 47.034 63.481 ;
     RECT  12.24 63.121 13.698 63.509 ;
     RECT  17.064 63.245 21.366 63.509 ;
     RECT  12.24 63.509 13.662 63.545 ;
     RECT  17.064 63.509 21.294 63.545 ;
     RECT  38.592 62.735 40.497 63.553 ;
     RECT  44.604 63.481 47.034 63.553 ;
     RECT  47.808 63.311 48.258 63.553 ;
     RECT  44.604 63.553 48.258 63.581 ;
     RECT  0.072 63.403 1.17 63.625 ;
     RECT  2.016 63.053 4.95 63.625 ;
     RECT  5.796 61.997 5.814 63.625 ;
     RECT  83.415 62.033 84.546 63.625 ;
     RECT  10.008 63.239 11.214 63.661 ;
     RECT  56.232 63.121 57.978 63.779 ;
     RECT  56.232 63.779 57.834 63.815 ;
     RECT  8.964 62.735 8.982 63.823 ;
     RECT  9.72 63.661 11.214 63.823 ;
     RECT  2.016 63.625 5.814 63.883 ;
     RECT  50.904 62.699 51.966 63.895 ;
     RECT  83.415 63.625 84.762 63.931 ;
     RECT  8.964 63.823 11.214 64.021 ;
     RECT  11.988 63.625 12.006 64.021 ;
     RECT  17.064 63.545 19.422 64.049 ;
     RECT  83.415 63.931 84.798 64.093 ;
     RECT  2.016 63.883 6.066 64.129 ;
     RECT  6.84 62.843 8.097 64.129 ;
     RECT  44.604 63.581 44.622 64.201 ;
     RECT  59.94 63.149 60.858 64.201 ;
     RECT  2.016 64.129 8.097 64.291 ;
     RECT  8.964 64.021 12.006 64.291 ;
     RECT  50.904 63.895 52.29 64.291 ;
     RECT  22.86 62.969 22.878 64.315 ;
     RECT  15.228 62.195 15.678 64.327 ;
     RECT  44.46 64.201 44.622 64.327 ;
     RECT  45.615 63.581 47.826 64.327 ;
     RECT  41.724 63.121 43.506 64.391 ;
     RECT  44.46 64.327 47.826 64.391 ;
     RECT  20.304 63.545 21.294 64.399 ;
     RECT  22.86 64.315 23.166 64.399 ;
     RECT  30.852 63.113 32.562 64.427 ;
     RECT  41.724 64.391 43.254 64.427 ;
     RECT  20.232 64.399 21.294 64.435 ;
     RECT  45.036 64.391 47.826 64.463 ;
     RECT  22.824 64.399 23.166 64.471 ;
     RECT  23.976 62.699 25.974 64.471 ;
     RECT  50.328 64.291 52.29 64.471 ;
     RECT  53.964 60.683 54.702 64.471 ;
     RECT  2.016 64.291 12.006 64.499 ;
     RECT  59.94 64.201 60.966 64.499 ;
     RECT  15.228 64.327 15.822 64.561 ;
     RECT  53.964 64.471 54.774 64.561 ;
     RECT  2.016 64.499 7.074 64.589 ;
     RECT  7.815 64.499 12.006 64.589 ;
     RECT  22.824 64.471 25.974 64.589 ;
     RECT  50.256 64.471 52.29 64.589 ;
     RECT  0.036 63.625 1.17 64.625 ;
     RECT  2.016 64.589 6.03 64.625 ;
     RECT  6.768 64.589 7.074 64.625 ;
     RECT  12.888 63.545 13.662 64.625 ;
     RECT  50.328 64.589 52.29 64.625 ;
     RECT  22.824 64.589 23.238 64.633 ;
     RECT  27.252 63.149 30.114 64.633 ;
     RECT  30.852 64.427 31.05 64.633 ;
     RECT  19.728 64.435 21.294 64.661 ;
     RECT  22.716 64.633 23.238 64.661 ;
     RECT  15.084 64.561 15.822 64.669 ;
     RECT  45.615 64.463 47.826 64.705 ;
     RECT  2.016 64.625 5.634 64.733 ;
     RECT  6.84 64.625 7.074 64.733 ;
     RECT  22.716 64.661 23.094 64.733 ;
     RECT  26.712 64.633 31.05 64.733 ;
     RECT  59.94 64.499 60.858 64.733 ;
     RECT  13.215 64.625 13.662 64.741 ;
     RECT  14.508 64.669 15.822 64.741 ;
     RECT  53.568 64.561 55.134 64.741 ;
     RECT  41.724 64.427 43.074 64.769 ;
     RECT  53.568 64.741 55.206 64.781 ;
     RECT  2.016 64.733 3.474 64.859 ;
     RECT  17.064 64.049 18.954 64.859 ;
     RECT  45.615 64.705 47.97 64.859 ;
     RECT  50.364 64.625 52.29 64.931 ;
     RECT  17.064 64.859 18.897 64.967 ;
     RECT  22.752 64.733 23.094 64.967 ;
     RECT  64.188 60.889 64.854 64.975 ;
     RECT  91.26 58.721 94.554 64.975 ;
     RECT  50.472 64.931 52.29 65.011 ;
     RECT  50.472 65.011 52.398 65.101 ;
     RECT  9.792 64.589 12.006 65.129 ;
     RECT  9.792 65.129 10.566 65.165 ;
     RECT  50.472 65.101 52.434 65.165 ;
     RECT  58.788 64.741 58.806 65.209 ;
     RECT  91.26 64.975 94.626 65.209 ;
     RECT  50.508 65.165 52.434 65.281 ;
     RECT  53.568 64.781 55.062 65.281 ;
     RECT  58.68 65.209 58.806 65.309 ;
     RECT  91.26 65.209 94.662 65.309 ;
     RECT  11.376 65.129 12.006 65.371 ;
     RECT  10.404 65.165 10.566 65.399 ;
     RECT  58.788 65.309 58.806 65.399 ;
     RECT  61.815 60.269 62.097 65.407 ;
     RECT  19.728 64.661 20.898 65.435 ;
     RECT  10.404 65.399 10.422 65.453 ;
     RECT  2.016 64.859 3.366 65.471 ;
     RECT  0.036 64.625 1.134 65.507 ;
     RECT  61.815 65.407 62.73 65.507 ;
     RECT  50.508 65.281 55.062 65.669 ;
     RECT  22.752 64.967 22.95 65.677 ;
     RECT  38.556 63.553 40.497 65.677 ;
     RECT  50.508 65.669 52.002 65.741 ;
     RECT  17.064 64.967 17.298 65.785 ;
     RECT  18.252 64.967 18.897 65.785 ;
     RECT  22.716 65.677 22.95 65.813 ;
     RECT  4.248 64.733 5.634 65.821 ;
     RECT  20.376 65.435 20.898 65.821 ;
     RECT  22.752 65.813 22.95 65.821 ;
     RECT  128.88 65.785 128.898 65.821 ;
     RECT  53.028 65.669 55.062 65.899 ;
     RECT  33.588 62.429 37.134 65.911 ;
     RECT  50.508 65.741 51.894 65.939 ;
     RECT  33.588 65.911 37.314 65.983 ;
     RECT  38.232 65.677 40.497 65.983 ;
     RECT  128.88 65.821 129.258 66.019 ;
     RECT  128.844 66.019 129.258 66.055 ;
     RECT  132.015 2.413 132.297 66.085 ;
     RECT  53.028 65.899 55.458 66.091 ;
     RECT  56.232 63.815 57.654 66.091 ;
     RECT  124.776 66.043 124.794 66.091 ;
     RECT  132.015 66.085 132.966 66.091 ;
     RECT  33.588 65.983 40.497 66.128 ;
     RECT  17.064 65.785 18.897 66.181 ;
     RECT  83.415 64.093 84.906 66.181 ;
     RECT  87.048 59.297 87.75 66.181 ;
     RECT  88.668 58.721 90.378 66.181 ;
     RECT  38.124 66.128 40.497 66.209 ;
     RECT  86.472 66.181 87.75 66.217 ;
     RECT  88.668 66.181 90.486 66.217 ;
     RECT  132.015 66.091 133.902 66.217 ;
     RECT  53.028 66.091 57.654 66.245 ;
     RECT  124.776 66.091 125.694 66.253 ;
     RECT  128.736 66.055 129.258 66.253 ;
     RECT  132.015 66.217 134.55 66.253 ;
     RECT  135.324 66.181 135.342 66.253 ;
     RECT  11.376 65.371 12.186 66.281 ;
     RECT  17.064 66.181 19.35 66.281 ;
     RECT  20.376 65.821 21.114 66.289 ;
     RECT  58.608 66.181 58.626 66.289 ;
     RECT  91.26 65.309 94.554 66.289 ;
     RECT  124.776 66.253 125.874 66.289 ;
     RECT  126.615 2.413 126.897 66.289 ;
     RECT  128.7 66.253 129.258 66.289 ;
     RECT  83.415 66.181 84.978 66.317 ;
     RECT  4.248 65.821 5.706 66.325 ;
     RECT  86.364 66.217 90.486 66.325 ;
     RECT  132.015 66.253 135.63 66.325 ;
     RECT  53.028 66.245 55.458 66.353 ;
     RECT  27.252 64.733 31.05 66.361 ;
     RECT  55.44 66.353 55.458 66.365 ;
     RECT  0.036 65.507 0.63 66.379 ;
     RECT  17.064 66.281 19.206 66.389 ;
     RECT  86.148 66.325 90.486 66.451 ;
     RECT  91.26 66.289 94.662 66.451 ;
     RECT  7.815 64.589 8.982 66.479 ;
     RECT  53.028 66.353 54.378 66.479 ;
     RECT  132.015 66.325 135.81 66.479 ;
     RECT  27.144 66.361 31.05 66.487 ;
     RECT  61.815 65.507 62.097 66.487 ;
     RECT  53.028 66.479 54.342 66.515 ;
     RECT  86.076 66.451 90.486 66.515 ;
     RECT  128.628 66.289 129.258 66.523 ;
     RECT  26.784 66.487 31.05 66.551 ;
     RECT  82.656 66.181 82.674 66.551 ;
     RECT  83.415 66.317 84.942 66.551 ;
     RECT  124.776 66.289 126.897 66.551 ;
     RECT  124.776 66.551 125.802 66.587 ;
     RECT  132.015 66.479 134.01 66.587 ;
     RECT  7.056 64.733 7.074 66.595 ;
     RECT  128.484 66.523 129.258 66.595 ;
     RECT  11.844 66.281 12.186 66.623 ;
     RECT  87.732 66.515 90.414 66.623 ;
     RECT  26.784 66.551 27.162 66.659 ;
     RECT  0.036 66.379 0.954 66.667 ;
     RECT  33.588 66.128 37.314 66.721 ;
     RECT  126.615 66.551 126.897 66.721 ;
     RECT  11.988 66.623 12.186 66.785 ;
     RECT  91.26 66.451 95.346 66.785 ;
     RECT  132.015 66.587 133.902 66.785 ;
     RECT  22.752 65.821 23.022 66.829 ;
     RECT  56.232 66.245 57.654 66.829 ;
     RECT  58.608 66.289 58.698 66.829 ;
     RECT  128.34 66.595 129.258 66.857 ;
     RECT  0.036 66.667 1.026 66.859 ;
     RECT  2.016 65.471 3.186 66.859 ;
     RECT  20.34 66.289 21.114 66.901 ;
     RECT  56.232 66.829 58.698 66.901 ;
     RECT  95.328 66.785 95.346 66.901 ;
     RECT  96.12 60.151 98.37 66.901 ;
     RECT  120.024 66.217 120.042 66.901 ;
     RECT  121.215 2.413 121.497 66.901 ;
     RECT  126.615 66.721 127.53 66.901 ;
     RECT  128.34 66.857 128.79 66.901 ;
     RECT  17.064 66.389 18.897 66.929 ;
     RECT  87.84 66.623 90.414 66.941 ;
     RECT  119.988 66.901 121.497 66.941 ;
     RECT  83.415 66.551 84.798 66.991 ;
     RECT  4.176 66.325 5.706 67.019 ;
     RECT  88.056 66.941 90.414 67.019 ;
     RECT  124.776 66.587 125.694 67.019 ;
     RECT  134.964 66.479 135.81 67.019 ;
     RECT  22.752 66.829 23.166 67.027 ;
     RECT  24.015 64.589 25.974 67.027 ;
     RECT  20.34 66.901 21.582 67.055 ;
     RECT  95.328 66.901 98.37 67.055 ;
     RECT  0.036 66.859 3.186 67.063 ;
     RECT  4.176 67.019 4.95 67.063 ;
     RECT  6.804 66.595 7.074 67.063 ;
     RECT  7.815 66.479 8.766 67.063 ;
     RECT  124.776 67.019 124.902 67.063 ;
     RECT  56.232 66.901 58.734 67.091 ;
     RECT  64.116 64.975 64.854 67.091 ;
     RECT  38.196 66.209 40.497 67.099 ;
     RECT  123.984 66.991 124.002 67.099 ;
     RECT  124.74 67.063 124.902 67.099 ;
     RECT  56.232 67.091 57.87 67.127 ;
     RECT  130.536 66.289 130.554 67.127 ;
     RECT  22.716 67.027 23.166 67.163 ;
     RECT  58.716 67.091 58.734 67.171 ;
     RECT  135.144 67.019 135.81 67.171 ;
     RECT  38.124 67.099 40.497 67.199 ;
     RECT  58.716 67.171 59.022 67.199 ;
     RECT  61.815 66.487 62.73 67.199 ;
     RECT  126.615 66.901 128.79 67.199 ;
     RECT  13.215 64.741 15.822 67.243 ;
     RECT  59.004 67.199 59.022 67.261 ;
     RECT  0.036 67.063 4.95 67.289 ;
     RECT  126.615 67.199 127.71 67.289 ;
     RECT  132.015 66.785 133.218 67.291 ;
     RECT  5.688 67.019 5.706 67.325 ;
     RECT  59.004 67.261 59.094 67.333 ;
     RECT  31.896 64.427 32.562 67.339 ;
     RECT  0.036 67.289 4.734 67.361 ;
     RECT  127.62 67.289 127.71 67.361 ;
     RECT  31.896 67.339 32.67 67.369 ;
     RECT  41.724 64.769 42.462 67.369 ;
     RECT  126.615 67.289 126.897 67.369 ;
     RECT  125.676 67.019 125.694 67.397 ;
     RECT  22.752 67.163 23.166 67.405 ;
     RECT  23.976 67.027 25.974 67.405 ;
     RECT  122.436 67.369 122.454 67.405 ;
     RECT  123.228 66.955 123.246 67.405 ;
     RECT  123.984 67.099 124.902 67.405 ;
     RECT  26.82 66.659 27.162 67.441 ;
     RECT  27.972 66.551 31.05 67.441 ;
     RECT  31.788 67.369 32.67 67.441 ;
     RECT  38.232 67.199 40.497 67.441 ;
     RECT  41.436 67.369 42.462 67.441 ;
     RECT  88.668 67.019 90.414 67.441 ;
     RECT  91.26 66.785 94.554 67.441 ;
     RECT  33.516 66.721 37.314 67.469 ;
     RECT  6.804 67.063 8.766 67.531 ;
     RECT  27.972 67.441 32.67 67.531 ;
     RECT  53.028 66.515 53.694 67.531 ;
     RECT  54.72 67.441 54.738 67.531 ;
     RECT  131.904 67.291 133.218 67.531 ;
     RECT  0.036 67.361 4.194 67.559 ;
     RECT  88.668 67.441 94.554 67.559 ;
     RECT  6.804 67.531 9.27 67.567 ;
     RECT  11.988 66.785 12.114 67.603 ;
     RECT  13.215 67.243 16.434 67.603 ;
     RECT  26.784 67.441 27.162 67.603 ;
     RECT  27.972 67.531 32.742 67.603 ;
     RECT  26.784 67.603 32.742 67.627 ;
     RECT  33.516 67.469 35.097 67.627 ;
     RECT  53.028 67.531 54.738 67.631 ;
     RECT  20.34 67.055 21.114 67.639 ;
     RECT  105.015 2.413 105.297 67.669 ;
     RECT  26.784 67.627 35.097 67.703 ;
     RECT  38.232 67.441 42.462 67.711 ;
     RECT  105.015 67.669 105.678 67.711 ;
     RECT  27.972 67.703 35.097 67.739 ;
     RECT  53.388 67.631 54.738 67.739 ;
     RECT  45.615 64.859 47.646 67.801 ;
     RECT  3.96 67.559 4.194 67.829 ;
     RECT  38.232 67.711 42.534 67.829 ;
     RECT  105.015 67.711 105.822 67.829 ;
     RECT  122.436 67.405 124.902 67.829 ;
     RECT  60.048 64.733 60.858 67.837 ;
     RECT  61.815 67.199 62.097 67.837 ;
     RECT  106.596 67.711 106.614 67.865 ;
     RECT  6.804 67.567 9.414 67.873 ;
     RECT  10.8 67.405 10.818 67.873 ;
     RECT  10.8 67.873 10.854 67.909 ;
     RECT  45.072 67.801 47.646 67.909 ;
     RECT  115.815 2.413 116.097 67.909 ;
     RECT  91.26 67.559 94.554 67.945 ;
     RECT  114.588 67.909 114.606 67.945 ;
     RECT  6.804 67.873 9.486 67.973 ;
     RECT  91.26 67.945 94.698 67.973 ;
     RECT  11.988 67.603 16.434 67.981 ;
     RECT  17.28 66.929 18.897 67.981 ;
     RECT  59.004 67.333 59.31 67.981 ;
     RECT  64.116 67.091 64.242 67.981 ;
     RECT  6.804 67.973 8.766 68.009 ;
     RECT  10.728 67.909 10.854 68.009 ;
     RECT  11.988 67.981 18.897 68.009 ;
     RECT  26.784 67.703 27.162 68.009 ;
     RECT  115.815 67.909 116.478 68.009 ;
     RECT  49.284 60.449 49.302 68.071 ;
     RECT  131.688 67.531 133.218 68.071 ;
     RECT  10.728 68.009 10.818 68.099 ;
     RECT  15.66 68.009 18.897 68.099 ;
     RECT  45 67.909 47.646 68.099 ;
     RECT  58.68 67.981 59.31 68.099 ;
     RECT  94.215 67.973 94.698 68.099 ;
     RECT  106.776 67.945 106.794 68.099 ;
     RECT  15.66 68.099 16.182 68.135 ;
     RECT  114.588 67.945 114.894 68.143 ;
     RECT  114.588 68.143 115.038 68.203 ;
     RECT  115.815 68.009 116.406 68.203 ;
     RECT  0.036 67.559 3.186 68.207 ;
     RECT  58.68 68.099 58.734 68.207 ;
     RECT  124.056 67.829 124.902 68.207 ;
     RECT  4.068 67.829 4.194 68.215 ;
     RECT  19.692 67.639 21.114 68.215 ;
     RECT  48.672 68.071 49.302 68.215 ;
     RECT  114.588 68.203 116.406 68.243 ;
     RECT  126.54 67.369 126.897 68.245 ;
     RECT  17.28 68.099 18.897 68.251 ;
     RECT  110.415 2.413 110.697 68.251 ;
     RECT  135.144 67.171 136.098 68.251 ;
     RECT  137.415 2.413 137.697 68.251 ;
     RECT  22.752 67.405 25.974 68.279 ;
     RECT  33.336 67.739 35.097 68.279 ;
     RECT  114.588 68.243 114.894 68.279 ;
     RECT  120.024 66.941 121.497 68.299 ;
     RECT  50.508 65.939 51.75 68.341 ;
     RECT  83.376 66.991 84.798 68.341 ;
     RECT  86.076 66.515 86.922 68.341 ;
     RECT  134.964 68.251 136.242 68.341 ;
     RECT  4.068 68.215 4.518 68.369 ;
     RECT  110.415 68.251 110.754 68.369 ;
     RECT  115.776 68.243 116.406 68.369 ;
     RECT  119.448 68.299 121.497 68.369 ;
     RECT  130.32 68.143 130.338 68.369 ;
     RECT  131.688 68.071 133.722 68.369 ;
     RECT  22.752 68.279 22.842 68.377 ;
     RECT  126.18 68.245 126.897 68.381 ;
     RECT  134.532 68.341 136.242 68.405 ;
     RECT  48.6 68.215 49.302 68.413 ;
     RECT  50.184 68.341 51.75 68.413 ;
     RECT  107.748 68.143 107.766 68.449 ;
     RECT  37.296 67.469 37.314 68.477 ;
     RECT  48.6 68.413 51.75 68.477 ;
     RECT  131.688 68.369 133.218 68.477 ;
     RECT  36.036 67.469 36.414 68.485 ;
     RECT  109.08 68.449 109.098 68.485 ;
     RECT  6.804 68.009 6.93 68.521 ;
     RECT  22.356 68.377 22.842 68.521 ;
     RECT  107.424 68.449 107.766 68.635 ;
     RECT  9.792 68.521 9.81 68.639 ;
     RECT  15.66 68.135 15.93 68.639 ;
     RECT  126.54 68.381 126.897 68.639 ;
     RECT  134.532 68.405 135.342 68.639 ;
     RECT  122.436 67.829 123.102 68.647 ;
     RECT  124.056 68.207 124.398 68.647 ;
     RECT  137.016 68.251 137.697 68.675 ;
     RECT  6.768 68.521 6.93 68.683 ;
     RECT  22.32 68.521 22.842 68.683 ;
     RECT  38.232 67.829 42.462 68.683 ;
     RECT  45.615 68.099 47.646 68.683 ;
     RECT  108.9 68.485 109.098 68.683 ;
     RECT  107.424 68.635 107.946 68.711 ;
     RECT  94.215 68.099 94.554 68.747 ;
     RECT  19.692 68.215 21.222 68.755 ;
     RECT  22.248 68.683 22.842 68.755 ;
     RECT  0.072 68.207 3.186 68.783 ;
     RECT  6.732 68.683 6.93 68.783 ;
     RECT  45.615 68.683 47.862 68.783 ;
     RECT  103.752 67.801 103.77 68.783 ;
     RECT  0.108 68.783 3.186 68.791 ;
     RECT  4.068 68.369 4.23 68.791 ;
     RECT  5.904 68.683 5.922 68.791 ;
     RECT  6.732 68.783 6.894 68.791 ;
     RECT  15.66 68.639 15.822 68.791 ;
     RECT  60.048 67.837 62.097 68.791 ;
     RECT  64.08 67.981 64.242 68.791 ;
     RECT  91.26 67.973 93.474 68.791 ;
     RECT  94.215 68.747 94.497 68.791 ;
     RECT  108.9 68.683 109.134 68.791 ;
     RECT  5.904 68.791 6.894 68.819 ;
     RECT  10.08 68.647 10.17 68.819 ;
     RECT  107.496 68.711 107.946 68.819 ;
     RECT  108.864 68.791 109.134 68.819 ;
     RECT  134.532 68.639 135.234 68.861 ;
     RECT  7.815 68.009 8.766 68.881 ;
     RECT  83.376 68.341 86.922 68.881 ;
     RECT  10.152 68.819 10.17 68.909 ;
     RECT  19.692 68.755 22.842 68.909 ;
     RECT  122.436 68.647 124.398 68.915 ;
     RECT  5.904 68.819 6.858 68.917 ;
     RECT  15.624 68.791 15.822 68.945 ;
     RECT  91.26 68.791 94.497 68.945 ;
     RECT  107.748 68.819 107.946 68.945 ;
     RECT  134.532 68.861 135.162 68.945 ;
     RECT  7.815 68.881 8.838 68.953 ;
     RECT  108.864 68.819 109.062 68.953 ;
     RECT  15.624 68.945 15.75 68.981 ;
     RECT  58.716 68.207 58.734 68.981 ;
     RECT  60.048 68.791 62.73 68.981 ;
     RECT  82.656 68.881 86.922 68.981 ;
     RECT  5.832 68.917 6.858 68.989 ;
     RECT  64.08 68.791 64.386 69.017 ;
     RECT  38.124 68.683 42.462 69.025 ;
     RECT  64.08 69.017 64.242 69.053 ;
     RECT  23.868 68.279 25.974 69.061 ;
     RECT  44.208 68.341 44.226 69.061 ;
     RECT  56.232 67.127 57.762 69.061 ;
     RECT  136.116 68.405 136.242 69.061 ;
     RECT  22.824 68.909 22.842 69.151 ;
     RECT  23.832 69.061 25.974 69.151 ;
     RECT  5.652 68.989 6.858 69.179 ;
     RECT  6.084 69.179 6.858 69.215 ;
     RECT  11.988 68.009 14.886 69.215 ;
     RECT  108.324 68.953 109.062 69.215 ;
     RECT  136.116 69.061 136.602 69.215 ;
     RECT  48.6 68.477 51.714 69.223 ;
     RECT  44.136 69.061 44.226 69.259 ;
     RECT  95.544 67.055 98.37 69.287 ;
     RECT  36.036 68.485 36.738 69.295 ;
     RECT  38.124 69.025 42.786 69.295 ;
     RECT  0.108 68.791 4.23 69.323 ;
     RECT  19.692 68.909 21.726 69.323 ;
     RECT  0.144 69.323 4.23 69.331 ;
     RECT  115.815 68.369 116.406 69.331 ;
     RECT  112.86 68.251 112.878 69.421 ;
     RECT  11.988 69.215 12.042 69.449 ;
     RECT  37.584 69.295 42.786 69.449 ;
     RECT  44.028 69.259 44.226 69.449 ;
     RECT  112.86 69.421 113.238 69.449 ;
     RECT  44.136 69.449 44.226 69.485 ;
     RECT  111.852 68.791 111.87 69.485 ;
     RECT  136.152 69.215 136.602 69.485 ;
     RECT  17.28 68.251 18.954 69.493 ;
     RECT  19.692 69.323 21.618 69.493 ;
     RECT  22.824 69.151 25.974 69.493 ;
     RECT  36.036 69.295 36.81 69.493 ;
     RECT  37.584 69.449 42.462 69.493 ;
     RECT  136.224 69.485 136.602 69.493 ;
     RECT  137.415 68.675 137.697 69.493 ;
     RECT  15.66 68.981 15.75 69.521 ;
     RECT  36.036 69.493 42.462 69.521 ;
     RECT  44.208 69.485 44.226 69.521 ;
     RECT  53.388 67.739 54.414 69.529 ;
     RECT  13.068 69.215 14.886 69.557 ;
     RECT  17.28 69.493 21.618 69.565 ;
     RECT  13.104 69.557 14.886 69.593 ;
     RECT  99.615 50.333 99.897 69.595 ;
     RECT  34.815 68.279 35.097 69.601 ;
     RECT  36.036 69.521 38.826 69.601 ;
     RECT  48.6 69.223 51.75 69.601 ;
     RECT  12.024 69.449 12.042 69.629 ;
     RECT  53.388 69.529 54.81 69.629 ;
     RECT  56.232 69.061 58.014 69.629 ;
     RECT  22.824 69.493 26.046 69.691 ;
     RECT  26.784 68.009 26.802 69.691 ;
     RECT  103.788 69.595 103.806 69.691 ;
     RECT  27.972 67.739 32.562 69.719 ;
     RECT  34.815 69.601 38.826 69.719 ;
     RECT  48.492 69.601 51.75 69.719 ;
     RECT  53.388 69.629 54.738 69.719 ;
     RECT  83.376 68.981 86.922 69.719 ;
     RECT  0.144 69.331 4.59 69.727 ;
     RECT  102.672 69.691 102.69 69.727 ;
     RECT  103.608 69.691 103.806 69.727 ;
     RECT  39.816 69.521 42.462 69.755 ;
     RECT  56.232 69.629 57.942 69.763 ;
     RECT  105.015 67.829 105.606 69.791 ;
     RECT  17.1 69.565 21.618 69.799 ;
     RECT  22.824 69.691 26.802 69.799 ;
     RECT  27.972 69.719 31.374 69.799 ;
     RECT  105.015 69.791 105.297 69.799 ;
     RECT  48.564 69.719 51.714 69.827 ;
     RECT  99.615 69.595 100.278 69.829 ;
     RECT  48.564 69.827 51.642 69.863 ;
     RECT  102.6 69.727 103.806 69.863 ;
     RECT  6.516 69.215 6.858 69.871 ;
     RECT  7.815 68.953 9.054 69.871 ;
     RECT  10.944 69.763 10.962 69.871 ;
     RECT  98.208 69.287 98.37 69.871 ;
     RECT  99.615 69.829 100.35 69.871 ;
     RECT  103.104 69.863 103.806 69.871 ;
     RECT  101.484 69.763 101.502 69.961 ;
     RECT  10.908 69.871 10.962 69.989 ;
     RECT  16.524 69.799 21.618 69.989 ;
     RECT  99.615 69.871 100.422 69.989 ;
     RECT  103.104 69.871 103.95 69.989 ;
     RECT  88.668 67.559 90.414 69.997 ;
     RECT  127.62 67.361 127.638 69.997 ;
     RECT  128.484 67.199 128.79 69.997 ;
     RECT  6.516 69.871 9.054 70.025 ;
     RECT  91.692 68.945 94.497 70.025 ;
     RECT  99.615 69.989 100.278 70.025 ;
     RECT  22.824 69.799 31.374 70.061 ;
     RECT  95.544 69.287 97.398 70.069 ;
     RECT  101.484 69.961 101.574 70.069 ;
     RECT  127.62 69.997 128.79 70.069 ;
     RECT  0.144 69.727 5.13 70.097 ;
     RECT  10.944 69.989 10.962 70.097 ;
     RECT  16.524 69.989 17.694 70.097 ;
     RECT  22.824 70.061 31.302 70.097 ;
     RECT  48.564 69.863 51.297 70.097 ;
     RECT  92.988 70.025 94.497 70.097 ;
     RECT  127.62 70.069 128.934 70.105 ;
     RECT  7.815 70.025 9.054 70.141 ;
     RECT  95.472 70.069 97.398 70.141 ;
     RECT  101.34 70.069 101.574 70.141 ;
     RECT  104.904 69.799 105.297 70.141 ;
     RECT  6.516 70.025 7.074 70.261 ;
     RECT  132.015 68.477 133.218 70.267 ;
     RECT  95.4 70.141 97.398 70.295 ;
     RECT  101.232 70.141 101.574 70.295 ;
     RECT  104.724 70.141 105.297 70.295 ;
     RECT  6.408 70.261 7.074 70.301 ;
     RECT  131.868 70.267 133.218 70.303 ;
     RECT  27.972 70.097 31.302 70.403 ;
     RECT  126.615 68.639 126.897 70.405 ;
     RECT  127.62 70.105 129.15 70.405 ;
     RECT  33.336 68.279 34.074 70.411 ;
     RECT  34.815 69.719 36.054 70.411 ;
     RECT  36.9 69.719 38.826 70.411 ;
     RECT  131.868 70.303 133.506 70.411 ;
     RECT  13.104 69.593 14.85 70.439 ;
     RECT  6.876 70.301 7.074 70.529 ;
     RECT  33.336 70.411 36.054 70.529 ;
     RECT  36.9 70.411 38.862 70.529 ;
     RECT  126.615 70.405 129.15 70.529 ;
     RECT  6.876 70.529 6.894 70.565 ;
     RECT  16.524 70.097 17.586 70.565 ;
     RECT  88.596 69.997 90.414 70.565 ;
     RECT  122.436 68.915 124.362 70.573 ;
     RECT  35.928 70.529 36.054 70.601 ;
     RECT  99.615 70.025 99.897 70.609 ;
     RECT  13.14 70.439 14.85 70.645 ;
     RECT  15.66 69.521 15.714 70.645 ;
     RECT  91.692 70.025 91.71 70.645 ;
     RECT  33.336 70.529 35.154 70.673 ;
     RECT  122.436 70.573 124.542 70.673 ;
     RECT  126.615 70.529 128.898 70.673 ;
     RECT  53.388 69.719 54.414 70.681 ;
     RECT  55.8 69.763 57.942 70.681 ;
     RECT  67.215 55.589 67.497 70.681 ;
     RECT  83.415 69.719 86.922 70.681 ;
     RECT  98.208 69.871 98.478 70.681 ;
     RECT  131.724 70.411 133.506 70.681 ;
     RECT  136.224 69.493 137.697 70.681 ;
     RECT  18.615 69.989 21.618 70.709 ;
     RECT  55.8 70.681 58.05 70.747 ;
     RECT  119.52 68.369 121.497 70.771 ;
     RECT  55.8 70.747 58.59 70.799 ;
     RECT  66.708 70.681 67.497 70.799 ;
     RECT  98.208 70.681 98.586 70.799 ;
     RECT  119.376 70.771 121.497 70.799 ;
     RECT  58.032 70.799 58.59 70.835 ;
     RECT  136.224 70.681 137.754 70.835 ;
     RECT  99.54 70.609 99.897 70.843 ;
     RECT  55.8 70.799 57.042 70.871 ;
     RECT  60.048 68.981 62.097 70.879 ;
     RECT  53.388 70.681 54.702 70.891 ;
     RECT  7.815 70.141 9.486 70.915 ;
     RECT  37.296 70.529 38.862 70.915 ;
     RECT  53.388 70.891 54.846 70.915 ;
     RECT  64.08 69.053 64.206 70.915 ;
     RECT  23.544 70.097 26.802 70.943 ;
     RECT  28.188 70.403 31.302 70.951 ;
     RECT  32.364 69.719 32.562 70.951 ;
     RECT  33.336 70.673 35.097 70.951 ;
     RECT  58.212 70.835 58.59 70.951 ;
     RECT  134.964 68.945 135.162 70.951 ;
     RECT  136.224 70.835 136.602 70.951 ;
     RECT  23.544 70.943 26.334 70.979 ;
     RECT  58.212 70.951 58.734 70.979 ;
     RECT  99.288 70.843 99.897 70.979 ;
     RECT  7.815 70.915 9.954 71.069 ;
     RECT  18.615 70.709 21.222 71.069 ;
     RECT  58.572 70.979 58.734 71.069 ;
     RECT  7.815 71.069 9.306 71.105 ;
     RECT  28.188 70.951 35.097 71.105 ;
     RECT  58.572 71.069 58.59 71.105 ;
     RECT  99.36 70.979 99.897 71.105 ;
     RECT  101.556 70.295 101.574 71.105 ;
     RECT  104.904 70.295 105.297 71.105 ;
     RECT  59.544 70.879 62.097 71.141 ;
     RECT  131.688 70.681 133.506 71.149 ;
     RECT  13.14 70.645 15.714 71.177 ;
     RECT  131.58 71.149 133.506 71.177 ;
     RECT  53.136 70.915 54.846 71.179 ;
     RECT  37.296 70.915 38.934 71.185 ;
     RECT  0.144 70.097 4.806 71.213 ;
     RECT  28.188 71.105 31.518 71.213 ;
     RECT  60.048 71.141 60.534 71.213 ;
     RECT  15.66 71.177 15.714 71.221 ;
     RECT  53.136 71.179 54.882 71.221 ;
     RECT  133.128 71.177 133.506 71.221 ;
     RECT  134.964 70.951 136.602 71.221 ;
     RECT  49.104 70.097 51.297 71.249 ;
     RECT  131.58 71.177 132.297 71.249 ;
     RECT  53.028 71.221 54.882 71.275 ;
     RECT  113.22 69.449 113.238 71.311 ;
     RECT  16.956 70.565 17.586 71.339 ;
     RECT  134.784 71.221 136.602 71.339 ;
     RECT  114.588 68.279 114.606 71.347 ;
     RECT  53.028 71.275 54.918 71.357 ;
     RECT  37.296 71.185 39.078 71.375 ;
     RECT  134.784 71.339 135.378 71.375 ;
     RECT  15.66 71.221 16.038 71.383 ;
     RECT  17.1 71.339 17.586 71.383 ;
     RECT  18.615 71.069 18.897 71.383 ;
     RECT  19.62 71.069 21.222 71.411 ;
     RECT  28.188 71.213 31.446 71.411 ;
     RECT  113.22 71.311 113.454 71.455 ;
     RECT  119.376 70.799 120.33 71.455 ;
     RECT  41.292 69.755 42.462 71.483 ;
     RECT  95.544 70.295 97.398 71.483 ;
     RECT  64.008 70.915 64.206 71.491 ;
     RECT  122.436 70.673 123.714 71.491 ;
     RECT  113.148 71.455 113.598 71.501 ;
     RECT  17.1 71.383 18.897 71.519 ;
     RECT  41.292 71.483 42.282 71.581 ;
     RECT  53.028 71.357 53.37 71.581 ;
     RECT  80.316 71.491 80.334 71.581 ;
     RECT  81.072 71.455 81.09 71.581 ;
     RECT  114.588 71.347 114.858 71.581 ;
     RECT  15.66 71.383 16.182 71.609 ;
     RECT  17.244 71.519 18.897 71.609 ;
     RECT  19.62 71.411 21.006 71.609 ;
     RECT  52.956 71.581 53.37 71.609 ;
     RECT  54.18 71.357 54.918 71.609 ;
     RECT  113.328 71.501 113.526 71.609 ;
     RECT  122.436 71.491 123.93 71.609 ;
     RECT  15.66 71.609 16.038 71.645 ;
     RECT  28.188 71.411 31.41 71.645 ;
     RECT  32.4 71.105 35.097 71.645 ;
     RECT  101.7 71.221 101.718 71.645 ;
     RECT  106.452 71.221 106.47 71.645 ;
     RECT  113.328 71.609 113.346 71.645 ;
     RECT  133.128 71.221 133.866 71.645 ;
     RECT  39.816 69.755 40.497 71.653 ;
     RECT  41.22 71.581 42.282 71.653 ;
     RECT  49.104 71.249 49.878 71.653 ;
     RECT  80.316 71.581 81.09 71.659 ;
     RECT  114.588 71.581 115.074 71.689 ;
     RECT  37.296 71.375 38.682 71.717 ;
     RECT  54.72 71.609 54.918 71.753 ;
     RECT  48.492 71.653 49.878 71.761 ;
     RECT  78.015 2.413 78.297 71.761 ;
     RECT  114.408 71.689 115.074 71.761 ;
     RECT  119.268 71.455 120.33 71.761 ;
     RECT  133.848 71.645 133.866 71.761 ;
     RECT  134.784 71.375 134.802 71.761 ;
     RECT  54.9 71.753 54.918 71.803 ;
     RECT  55.8 70.871 56.862 71.803 ;
     RECT  54.9 71.803 56.862 71.837 ;
     RECT  78.015 71.761 78.966 71.851 ;
     RECT  99.54 71.105 99.897 71.851 ;
     RECT  39.816 71.653 42.282 71.879 ;
     RECT  60.516 71.213 60.534 71.879 ;
     RECT  80.316 71.659 81.162 71.887 ;
     RECT  88.596 70.565 90.378 71.887 ;
     RECT  91.224 70.645 91.71 71.887 ;
     RECT  78.015 71.851 79.29 71.888 ;
     RECT  99.54 71.851 100.026 71.915 ;
     RECT  114.3 71.761 115.074 71.915 ;
     RECT  133.848 71.761 134.802 71.915 ;
     RECT  8.82 71.105 9.306 71.923 ;
     RECT  55.548 71.837 56.862 71.933 ;
     RECT  55.62 71.933 56.862 71.951 ;
     RECT  45.615 68.783 47.574 71.959 ;
     RECT  48.456 71.761 49.878 71.959 ;
     RECT  28.188 71.645 31.302 71.987 ;
     RECT  93.312 70.097 94.497 71.995 ;
     RECT  95.544 71.483 95.562 71.995 ;
     RECT  118.224 71.491 118.242 71.995 ;
     RECT  119.16 71.761 120.33 71.995 ;
     RECT  0.828 71.213 4.806 72.023 ;
     RECT  55.62 71.951 56.697 72.023 ;
     RECT  59.004 71.851 59.274 72.023 ;
     RECT  88.596 71.887 91.782 72.023 ;
     RECT  61.815 71.141 62.097 72.031 ;
     RECT  63.972 71.491 64.206 72.031 ;
     RECT  93.312 71.995 95.562 72.031 ;
     RECT  59.004 72.023 59.094 72.059 ;
     RECT  80.28 71.887 81.162 72.059 ;
     RECT  118.224 71.995 120.33 72.121 ;
     RECT  126.615 70.673 127.782 72.121 ;
     RECT  59.076 72.059 59.094 72.149 ;
     RECT  80.388 72.059 81.162 72.149 ;
     RECT  134.1 71.915 134.802 72.149 ;
     RECT  80.676 72.149 81.162 72.157 ;
     RECT  61.815 72.031 62.73 72.185 ;
     RECT  63.972 72.031 64.35 72.185 ;
     RECT  80.676 72.157 81.198 72.185 ;
     RECT  109.008 69.215 109.062 72.185 ;
     RECT  11.844 71.581 11.862 72.193 ;
     RECT  37.296 71.717 38.43 72.221 ;
     RECT  39.816 71.879 40.497 72.221 ;
     RECT  45.615 71.959 49.878 72.221 ;
     RECT  49.104 72.221 49.878 72.257 ;
     RECT  74.664 72.031 74.682 72.257 ;
     RECT  78.015 71.888 79.074 72.257 ;
     RECT  80.748 72.185 81.198 72.257 ;
     RECT  63.972 72.185 64.278 72.293 ;
     RECT  82.656 72.031 82.674 72.293 ;
     RECT  83.415 70.681 87.066 72.293 ;
     RECT  90.036 72.023 91.782 72.301 ;
     RECT  109.044 72.185 109.062 72.301 ;
     RECT  136.152 71.339 136.602 72.301 ;
     RECT  6.804 72.193 6.822 72.329 ;
     RECT  80.748 72.257 80.946 72.329 ;
     RECT  83.415 72.293 85.266 72.329 ;
     RECT  86.076 72.293 87.066 72.329 ;
     RECT  15.66 71.645 15.678 72.391 ;
     RECT  18.615 71.609 18.897 72.391 ;
     RECT  19.62 71.609 20.934 72.391 ;
     RECT  0.9 72.023 4.806 72.455 ;
     RECT  11.844 72.193 12.15 72.455 ;
     RECT  55.872 72.023 56.697 72.455 ;
     RECT  135.612 72.301 136.602 72.455 ;
     RECT  28.188 71.987 31.266 72.463 ;
     RECT  37.296 72.221 37.602 72.491 ;
     RECT  105.015 71.105 105.297 72.499 ;
     RECT  18.615 72.391 20.934 72.527 ;
     RECT  115.815 69.331 116.622 72.527 ;
     RECT  90.036 72.301 92.106 72.563 ;
     RECT  5.796 72.265 5.814 72.571 ;
     RECT  32.4 71.645 34.074 72.571 ;
     RECT  34.815 71.645 35.097 72.571 ;
     RECT  99.615 71.915 100.026 72.571 ;
     RECT  103.104 69.989 103.338 72.571 ;
     RECT  126.615 72.121 128.034 72.571 ;
     RECT  37.296 72.491 37.422 72.599 ;
     RECT  45.615 72.221 48.114 72.661 ;
     RECT  45.108 72.661 48.114 72.689 ;
     RECT  103.104 72.571 103.446 72.689 ;
     RECT  1.404 72.455 4.806 72.725 ;
     RECT  56.232 72.455 56.697 72.725 ;
     RECT  114.84 71.915 115.074 72.725 ;
     RECT  67.215 70.799 67.497 72.733 ;
     RECT  42.084 71.879 42.282 72.769 ;
     RECT  104.4 72.499 105.297 72.769 ;
     RECT  45.108 72.689 47.574 72.797 ;
     RECT  78.015 72.257 78.894 72.797 ;
     RECT  27.612 72.463 31.266 72.805 ;
     RECT  96.552 71.483 97.398 72.805 ;
     RECT  98.208 70.799 98.478 72.805 ;
     RECT  101.916 71.761 101.934 72.805 ;
     RECT  32.4 72.571 35.097 72.833 ;
     RECT  43.92 72.661 43.938 72.841 ;
     RECT  104.364 72.769 105.297 72.841 ;
     RECT  115.815 72.527 116.097 72.841 ;
     RECT  118.224 72.121 120.366 72.841 ;
     RECT  121.215 70.799 121.497 72.841 ;
     RECT  122.436 71.609 123.786 72.841 ;
     RECT  15.66 72.391 15.93 72.931 ;
     RECT  32.4 72.833 34.074 72.931 ;
     RECT  134.208 72.149 134.802 72.931 ;
     RECT  45.18 72.797 47.574 72.959 ;
     RECT  66.744 72.733 67.497 72.959 ;
     RECT  17.244 71.609 17.586 72.967 ;
     RECT  52.956 71.609 52.974 72.967 ;
     RECT  1.404 72.725 3.438 72.995 ;
     RECT  5.796 72.571 6.282 72.995 ;
     RECT  92.088 72.563 92.106 72.995 ;
     RECT  104.256 72.841 105.297 72.995 ;
     RECT  134.208 72.931 135.27 72.995 ;
     RECT  63.972 72.293 64.206 73.031 ;
     RECT  96.552 72.805 98.478 73.031 ;
     RECT  13.215 71.177 14.778 73.039 ;
     RECT  50.796 71.249 51.297 73.039 ;
     RECT  1.404 72.995 1.494 73.067 ;
     RECT  50.796 73.039 51.354 73.067 ;
     RECT  49.104 72.257 49.302 73.075 ;
     RECT  63.972 73.031 64.026 73.103 ;
     RECT  15.66 72.931 16.002 73.111 ;
     RECT  17.1 72.967 17.586 73.111 ;
     RECT  24.015 70.979 26.334 73.111 ;
     RECT  50.94 73.067 51.354 73.111 ;
     RECT  86.184 72.329 87.066 73.111 ;
     RECT  93.204 72.031 95.562 73.111 ;
     RECT  101.916 72.805 102.006 73.111 ;
     RECT  52.956 72.967 53.046 73.139 ;
     RECT  7.815 71.105 8.097 73.201 ;
     RECT  8.82 71.923 9.342 73.201 ;
     RECT  101.916 73.111 102.114 73.201 ;
     RECT  18.615 72.527 20.826 73.229 ;
     RECT  27.504 72.805 31.266 73.229 ;
     RECT  118.224 72.841 121.497 73.229 ;
     RECT  97.38 73.031 98.478 73.237 ;
     RECT  1.476 73.067 1.494 73.265 ;
     RECT  92.196 73.111 95.562 73.265 ;
     RECT  115.632 72.841 116.097 73.265 ;
     RECT  134.64 72.995 135.27 73.265 ;
     RECT  103.104 72.689 103.338 73.301 ;
     RECT  6.012 72.995 6.282 73.309 ;
     RECT  50.94 73.111 51.39 73.309 ;
     RECT  23.508 73.111 26.334 73.345 ;
     RECT  6.012 73.309 6.93 73.381 ;
     RECT  22.248 73.003 22.266 73.381 ;
     RECT  23.364 73.345 26.334 73.381 ;
     RECT  42.084 72.769 42.858 73.381 ;
     RECT  50.94 73.309 51.498 73.381 ;
     RECT  101.916 73.201 102.222 73.381 ;
     RECT  103.104 73.301 103.194 73.381 ;
     RECT  115.815 73.265 116.097 73.381 ;
     RECT  122.436 72.841 123.894 73.381 ;
     RECT  13.215 73.039 14.85 73.471 ;
     RECT  41.976 73.381 42.858 73.471 ;
     RECT  45.615 72.959 47.574 73.471 ;
     RECT  138.852 73.381 138.87 73.471 ;
     RECT  6.012 73.381 6.966 73.483 ;
     RECT  13.104 73.471 14.85 73.499 ;
     RECT  101.916 73.381 103.194 73.499 ;
     RECT  101.916 73.499 102.006 73.522 ;
     RECT  14.436 73.499 14.85 73.535 ;
     RECT  18.615 73.229 20.358 73.535 ;
     RECT  27.504 73.229 30.114 73.571 ;
     RECT  22.248 73.381 26.334 73.615 ;
     RECT  41.976 73.471 43.038 73.615 ;
     RECT  6.012 73.483 7.002 73.643 ;
     RECT  7.815 73.201 9.342 73.651 ;
     RECT  45.615 73.471 47.61 73.651 ;
     RECT  92.988 73.265 95.562 73.651 ;
     RECT  126.615 72.571 128.502 73.651 ;
     RECT  7.815 73.651 9.414 73.741 ;
     RECT  132.015 71.249 132.297 73.741 ;
     RECT  6.012 73.643 6.75 73.769 ;
     RECT  14.508 73.535 14.85 73.769 ;
     RECT  15.66 73.111 17.586 73.769 ;
     RECT  19.692 73.535 20.358 73.769 ;
     RECT  32.112 72.931 34.074 73.769 ;
     RECT  92.988 73.651 95.778 73.769 ;
     RECT  97.38 73.237 98.622 73.771 ;
     RECT  132.015 73.741 132.642 73.777 ;
     RECT  2.268 72.995 3.438 73.805 ;
     RECT  7.815 73.741 10.278 73.805 ;
     RECT  11.988 73.381 12.006 73.805 ;
     RECT  27.612 73.571 30.114 73.805 ;
     RECT  102.888 73.499 103.194 73.805 ;
     RECT  120.924 73.229 121.497 73.805 ;
     RECT  134.64 73.265 135.054 73.805 ;
     RECT  136.224 72.455 136.602 73.805 ;
     RECT  97.38 73.771 98.658 73.811 ;
     RECT  7.815 73.805 9.666 73.841 ;
     RECT  27.612 73.805 27.954 73.841 ;
     RECT  92.988 73.769 95.562 73.877 ;
     RECT  97.38 73.811 98.478 73.877 ;
     RECT  101.916 73.522 101.934 73.877 ;
     RECT  103.104 73.805 103.194 73.877 ;
     RECT  131.652 73.777 132.642 73.877 ;
     RECT  27.612 73.841 27.882 73.901 ;
     RECT  22.248 73.615 26.802 73.913 ;
     RECT  7.815 73.841 9.594 73.921 ;
     RECT  96.552 73.031 96.57 73.921 ;
     RECT  99.615 72.571 100.314 73.921 ;
     RECT  136.224 73.805 136.494 73.921 ;
     RECT  137.376 70.835 137.754 73.921 ;
     RECT  138.78 73.471 138.87 73.921 ;
     RECT  22.248 73.913 26.478 73.949 ;
     RECT  41.508 73.615 43.038 73.949 ;
     RECT  63.972 73.103 63.99 73.949 ;
     RECT  134.712 73.805 134.802 73.949 ;
     RECT  25.992 73.949 26.478 73.997 ;
     RECT  96.372 73.921 96.57 74.011 ;
     RECT  115.815 73.381 116.262 74.011 ;
     RECT  7.596 73.921 9.594 74.039 ;
     RECT  22.86 73.949 25.254 74.039 ;
     RECT  25.992 73.997 26.334 74.039 ;
     RECT  50.94 73.381 51.894 74.039 ;
     RECT  52.956 73.139 52.974 74.039 ;
     RECT  45.615 73.651 47.718 74.047 ;
     RECT  96.372 74.011 96.606 74.047 ;
     RECT  99.576 73.921 100.314 74.047 ;
     RECT  15.66 73.769 17.478 74.075 ;
     RECT  22.896 74.039 25.254 74.075 ;
     RECT  90.036 72.563 91.242 74.075 ;
     RECT  126.615 73.651 128.898 74.075 ;
     RECT  131.652 73.877 132.498 74.075 ;
     RECT  135.972 73.921 136.494 74.075 ;
     RECT  25.992 74.039 26.154 74.093 ;
     RECT  50.94 74.039 51.714 74.093 ;
     RECT  96.372 74.047 96.678 74.093 ;
     RECT  7.815 74.039 9.594 74.111 ;
     RECT  25.992 74.093 26.01 74.111 ;
     RECT  6.012 73.769 6.534 74.155 ;
     RECT  92.196 73.265 92.214 74.155 ;
     RECT  92.988 73.877 94.497 74.155 ;
     RECT  118.224 73.229 120.006 74.155 ;
     RECT  92.196 74.155 94.497 74.191 ;
     RECT  118.224 74.155 120.15 74.191 ;
     RECT  95.364 73.877 95.562 74.219 ;
     RECT  13.104 73.499 13.662 74.281 ;
     RECT  20.34 73.769 20.358 74.281 ;
     RECT  20.34 74.281 20.502 74.309 ;
     RECT  27.684 73.901 27.882 74.309 ;
     RECT  7.815 74.111 8.154 74.345 ;
     RECT  27.684 74.309 27.702 74.345 ;
     RECT  37.296 72.599 37.314 74.345 ;
     RECT  91.728 74.191 94.497 74.345 ;
     RECT  103.176 73.877 103.194 74.345 ;
     RECT  117.648 74.191 120.15 74.345 ;
     RECT  98.028 73.877 98.478 74.381 ;
     RECT  4.176 72.725 4.806 74.389 ;
     RECT  5.544 74.155 6.534 74.389 ;
     RECT  38.412 72.221 38.43 74.389 ;
     RECT  39.888 72.221 40.497 74.389 ;
     RECT  99.504 74.047 100.314 74.389 ;
     RECT  20.484 74.309 20.502 74.453 ;
     RECT  31.032 73.229 31.266 74.461 ;
     RECT  32.112 73.769 32.562 74.461 ;
     RECT  104.796 72.995 105.297 74.461 ;
     RECT  117.828 74.345 120.15 74.461 ;
     RECT  4.176 74.389 6.534 74.489 ;
     RECT  96.552 74.093 96.606 74.489 ;
     RECT  12.852 74.281 13.662 74.551 ;
     RECT  33.588 73.769 34.074 74.551 ;
     RECT  34.815 72.833 35.097 74.551 ;
     RECT  38.304 74.389 38.43 74.551 ;
     RECT  38.304 74.551 38.574 74.579 ;
     RECT  91.728 74.345 92.898 74.579 ;
     RECT  130.68 74.461 130.698 74.587 ;
     RECT  4.176 74.489 5.562 74.615 ;
     RECT  38.412 74.579 38.574 74.615 ;
     RECT  39.348 74.389 40.497 74.615 ;
     RECT  41.508 73.949 42.822 74.615 ;
     RECT  98.028 74.381 98.262 74.615 ;
     RECT  36.036 70.601 36.054 74.623 ;
     RECT  99.216 74.389 100.314 74.623 ;
     RECT  104.328 74.461 105.297 74.623 ;
     RECT  4.176 74.615 5.274 74.651 ;
     RECT  35.964 74.623 36.054 74.651 ;
     RECT  41.508 74.615 41.526 74.659 ;
     RECT  139.932 74.461 139.95 74.659 ;
     RECT  117.828 74.461 120.258 74.669 ;
     RECT  43.92 72.841 44.154 74.687 ;
     RECT  139.86 74.659 139.95 74.687 ;
     RECT  41.364 74.659 41.526 74.695 ;
     RECT  115.815 74.011 116.658 74.717 ;
     RECT  14.508 73.769 14.778 74.731 ;
     RECT  15.66 74.075 15.678 74.731 ;
     RECT  49.104 73.075 49.878 74.731 ;
     RECT  50.94 74.093 51.297 74.731 ;
     RECT  93.744 74.345 94.497 74.731 ;
     RECT  122.436 73.381 124.074 74.731 ;
     RECT  134.712 73.949 134.73 74.731 ;
     RECT  16.776 74.075 17.478 74.759 ;
     RECT  93.744 74.731 94.662 74.759 ;
     RECT  122.436 74.731 124.29 74.821 ;
     RECT  4.176 74.651 5.238 74.849 ;
     RECT  14.508 74.731 15.678 74.849 ;
     RECT  116.82 74.731 117.054 74.849 ;
     RECT  130.68 74.587 130.77 74.875 ;
     RECT  131.652 74.075 132.297 74.875 ;
     RECT  6.444 74.489 6.534 74.885 ;
     RECT  96.552 74.489 96.57 74.885 ;
     RECT  99.036 74.623 100.494 74.885 ;
     RECT  104.328 74.623 105.39 74.885 ;
     RECT  116.82 74.849 116.838 74.885 ;
     RECT  12.78 74.551 13.662 74.921 ;
     RECT  45.615 74.047 47.754 74.929 ;
     RECT  137.376 73.921 138.87 74.929 ;
     RECT  6.48 74.885 6.498 74.957 ;
     RECT  14.508 74.849 15.534 74.957 ;
     RECT  45.615 74.929 48.042 74.957 ;
     RECT  90.036 74.075 90.81 74.957 ;
     RECT  94.215 74.759 94.662 74.957 ;
     RECT  99.108 74.885 100.494 74.957 ;
     RECT  134.532 74.731 134.73 74.957 ;
     RECT  130.536 74.875 130.77 74.965 ;
     RECT  131.652 74.875 132.39 74.965 ;
     RECT  15.228 74.957 15.534 74.993 ;
     RECT  13.14 74.921 13.662 75.001 ;
     RECT  33.588 74.551 35.19 75.001 ;
     RECT  47.268 74.957 48.042 75.001 ;
     RECT  49.104 74.731 51.297 75.001 ;
     RECT  86.184 73.111 87.246 75.001 ;
     RECT  88.596 72.023 89.097 75.001 ;
     RECT  90.468 74.957 90.81 75.001 ;
     RECT  136.26 74.075 136.494 75.001 ;
     RECT  137.376 74.929 139.122 75.001 ;
     RECT  47.268 75.001 51.297 75.029 ;
     RECT  16.776 74.759 17.298 75.119 ;
     RECT  41.328 74.695 41.526 75.119 ;
     RECT  47.268 75.029 50.202 75.119 ;
     RECT  90.468 75.001 90.882 75.119 ;
     RECT  9 74.111 9.594 75.127 ;
     RECT  117.828 74.669 118.242 75.149 ;
     RECT  13.14 75.001 14.346 75.155 ;
     RECT  47.268 75.119 49.878 75.155 ;
     RECT  90.468 75.119 90.774 75.155 ;
     RECT  97.488 75.001 97.506 75.155 ;
     RECT  99.216 74.957 100.494 75.155 ;
     RECT  41.328 75.119 41.454 75.163 ;
     RECT  15.228 74.993 15.246 75.191 ;
     RECT  9 75.127 9.882 75.197 ;
     RECT  31.032 74.461 32.562 75.199 ;
     RECT  33.3 75.001 35.19 75.199 ;
     RECT  122.436 74.821 124.83 75.199 ;
     RECT  47.34 75.155 49.878 75.227 ;
     RECT  90.468 75.155 90.486 75.227 ;
     RECT  122.436 75.199 124.938 75.235 ;
     RECT  47.448 75.227 49.878 75.263 ;
     RECT  31.032 75.199 35.19 75.271 ;
     RECT  35.964 74.651 35.982 75.271 ;
     RECT  99.615 75.155 100.494 75.271 ;
     RECT  136.26 75.001 139.122 75.271 ;
     RECT  106.668 71.761 106.686 75.293 ;
     RECT  130.536 74.965 132.39 75.361 ;
     RECT  91.728 74.579 92.502 75.389 ;
     RECT  38.556 74.615 38.574 75.397 ;
     RECT  134.604 74.957 134.73 75.397 ;
     RECT  134.604 75.397 134.982 75.403 ;
     RECT  31.032 75.271 35.982 75.425 ;
     RECT  86.184 75.001 89.097 75.425 ;
     RECT  91.728 75.389 91.746 75.425 ;
     RECT  109.044 72.301 109.602 75.425 ;
     RECT  126.615 74.075 128.826 75.425 ;
     RECT  134.604 75.403 135.09 75.425 ;
     RECT  136.08 75.271 139.122 75.425 ;
     RECT  122.436 75.235 125.01 75.461 ;
     RECT  38.34 75.397 38.574 75.469 ;
     RECT  110.415 68.369 110.697 75.469 ;
     RECT  95.544 74.219 95.562 75.485 ;
     RECT  130.536 75.361 132.75 75.497 ;
     RECT  119.268 74.669 120.258 75.505 ;
     RECT  129.708 75.397 129.726 75.505 ;
     RECT  99.615 75.271 100.674 75.533 ;
     RECT  118.224 75.149 118.242 75.533 ;
     RECT  2.268 73.805 3.258 75.541 ;
     RECT  28.908 73.805 30.114 75.541 ;
     RECT  136.08 75.425 136.422 75.541 ;
     RECT  137.16 75.425 139.122 75.541 ;
     RECT  139.86 74.687 139.878 75.541 ;
     RECT  34.524 75.425 35.982 75.569 ;
     RECT  105.015 74.885 105.39 75.569 ;
     RECT  130.752 75.497 132.75 75.631 ;
     RECT  28.908 75.541 30.294 75.659 ;
     RECT  31.032 75.425 33.606 75.659 ;
     RECT  38.34 75.469 38.754 75.659 ;
     RECT  129.348 75.505 129.726 75.659 ;
     RECT  134.712 75.425 135.09 75.659 ;
     RECT  135.072 75.659 135.09 75.677 ;
     RECT  29.016 75.659 30.294 75.695 ;
     RECT  98.244 74.615 98.262 75.695 ;
     RECT  135.936 75.541 136.422 75.695 ;
     RECT  119.268 75.505 120.294 75.775 ;
     RECT  121.14 73.805 121.497 75.775 ;
     RECT  99.615 75.533 100.314 75.839 ;
     RECT  41.256 75.163 41.454 75.901 ;
     RECT  42.264 74.615 42.822 75.901 ;
     RECT  122.436 75.461 124.938 75.929 ;
     RECT  119.268 75.775 121.497 76.013 ;
     RECT  41.256 75.901 42.822 76.037 ;
     RECT  119.268 76.013 120.366 76.109 ;
     RECT  39.528 74.615 40.497 76.171 ;
     RECT  41.256 76.037 41.346 76.171 ;
     RECT  83.415 72.329 84.51 76.171 ;
     RECT  85.248 72.329 85.266 76.171 ;
     RECT  24.015 74.075 24.642 76.199 ;
     RECT  122.508 75.929 124.938 76.199 ;
     RECT  122.508 76.199 124.074 76.205 ;
     RECT  47.592 75.263 49.878 76.207 ;
     RECT  118.944 76.207 118.962 76.253 ;
     RECT  34.56 75.569 35.982 76.271 ;
     RECT  39.528 76.171 41.346 76.271 ;
     RECT  47.592 76.207 49.95 76.271 ;
     RECT  122.544 76.205 124.074 76.271 ;
     RECT  109.044 75.425 109.062 76.301 ;
     RECT  34.776 76.271 35.982 76.315 ;
     RECT  39.636 76.271 41.346 76.343 ;
     RECT  24.015 76.199 24.498 76.349 ;
     RECT  13.176 75.155 14.346 76.351 ;
     RECT  42.156 76.037 42.822 76.351 ;
     RECT  136.26 75.695 136.422 76.351 ;
     RECT  137.16 75.541 139.878 76.351 ;
     RECT  12.672 76.351 14.346 76.397 ;
     RECT  34.776 76.315 36.054 76.441 ;
     RECT  129.348 75.659 129.366 76.441 ;
     RECT  18.615 73.535 18.897 76.459 ;
     RECT  50.94 75.029 51.297 76.469 ;
     RECT  83.415 76.171 85.266 76.469 ;
     RECT  92.484 75.389 92.502 76.505 ;
     RECT  109.8 75.469 110.697 76.541 ;
     RECT  129.348 76.441 129.618 76.541 ;
     RECT  136.26 76.351 139.878 76.549 ;
     RECT  18.504 76.459 18.897 76.585 ;
     RECT  88.56 75.425 89.097 76.589 ;
     RECT  9 75.197 9.594 76.621 ;
     RECT  29.088 75.695 30.294 76.739 ;
     RECT  129.348 76.541 129.402 76.739 ;
     RECT  136.08 76.549 139.878 76.739 ;
     RECT  38.34 75.659 38.61 76.747 ;
     RECT  136.44 76.739 139.878 76.747 ;
     RECT  4.176 74.849 5.166 76.775 ;
     RECT  123.948 76.271 124.074 76.775 ;
     RECT  134.856 76.621 134.874 76.775 ;
     RECT  136.44 76.747 139.914 76.775 ;
     RECT  124.848 76.199 124.938 76.783 ;
     RECT  126.615 75.425 128.358 76.843 ;
     RECT  37.728 76.747 38.61 76.847 ;
     RECT  42.156 76.351 42.966 76.847 ;
     RECT  126.615 76.843 128.394 76.883 ;
     RECT  6.264 76.621 6.282 76.891 ;
     RECT  37.728 76.847 38.358 76.891 ;
     RECT  119.7 76.109 120.366 76.891 ;
     RECT  126.615 76.883 128.178 76.919 ;
     RECT  45.615 74.957 46.494 76.981 ;
     RECT  124.848 76.783 125.118 76.981 ;
     RECT  18.504 76.585 18.954 77.009 ;
     RECT  4.212 76.775 5.166 77.017 ;
     RECT  6.264 76.891 6.642 77.017 ;
     RECT  45.615 76.981 46.602 77.017 ;
     RECT  124.848 76.981 125.334 77.017 ;
     RECT  126.615 76.919 128.106 77.017 ;
     RECT  4.212 77.017 6.642 77.045 ;
     RECT  18.504 77.009 18.897 77.053 ;
     RECT  124.848 77.017 128.106 77.053 ;
     RECT  10.8 75.271 10.818 77.081 ;
     RECT  122.544 76.271 123.102 77.081 ;
     RECT  39.672 76.343 41.346 77.083 ;
     RECT  13.215 76.397 14.346 77.089 ;
     RECT  15.228 77.017 15.246 77.089 ;
     RECT  119.7 76.891 120.402 77.089 ;
     RECT  119.7 77.089 120.438 77.117 ;
     RECT  124.776 77.053 128.106 77.117 ;
     RECT  37.584 76.891 38.358 77.125 ;
     RECT  39.6 77.083 41.346 77.153 ;
     RECT  124.92 77.117 128.106 77.153 ;
     RECT  13.215 77.089 15.246 77.161 ;
     RECT  16.776 75.119 16.794 77.161 ;
     RECT  121.215 76.013 121.497 77.161 ;
     RECT  7.815 74.345 8.097 77.251 ;
     RECT  120.024 77.117 120.438 77.251 ;
     RECT  121.215 77.161 121.698 77.251 ;
     RECT  130.752 75.631 133.002 77.251 ;
     RECT  13.215 77.161 16.002 77.279 ;
     RECT  39.708 77.153 41.31 77.279 ;
     RECT  123.948 76.775 123.966 77.279 ;
     RECT  6.624 77.045 6.642 77.315 ;
     RECT  93.06 76.621 93.078 77.315 ;
     RECT  124.92 77.153 128.07 77.315 ;
     RECT  136.8 76.775 139.914 77.315 ;
     RECT  45.615 77.017 46.818 77.323 ;
     RECT  47.592 76.271 49.122 77.323 ;
     RECT  22.068 75.199 22.158 77.359 ;
     RECT  24.015 76.349 24.297 77.359 ;
     RECT  18.288 77.053 18.897 77.431 ;
     RECT  130.212 77.251 133.002 77.431 ;
     RECT  39.708 77.279 40.554 77.459 ;
     RECT  4.212 77.045 5.706 77.501 ;
     RECT  7.815 77.251 8.154 77.521 ;
     RECT  8.928 76.621 9.594 77.521 ;
     RECT  15.984 77.279 16.002 77.521 ;
     RECT  16.776 77.161 17.406 77.521 ;
     RECT  29.304 76.739 30.294 77.521 ;
     RECT  129.384 76.739 129.402 77.521 ;
     RECT  130.212 77.431 133.11 77.521 ;
     RECT  133.92 77.251 133.938 77.521 ;
     RECT  120.024 77.251 121.698 77.549 ;
     RECT  130.212 77.521 133.938 77.549 ;
     RECT  4.392 77.501 5.706 77.585 ;
     RECT  15.984 77.521 17.406 77.585 ;
     RECT  120.024 77.549 120.042 77.585 ;
     RECT  13.215 77.279 15.246 77.593 ;
     RECT  133.812 77.549 133.938 77.593 ;
     RECT  129.384 77.521 129.438 77.629 ;
     RECT  130.212 77.549 132.93 77.629 ;
     RECT  129.384 77.629 132.93 77.665 ;
     RECT  133.812 77.593 134.442 77.665 ;
     RECT  135.756 77.593 135.774 77.665 ;
     RECT  4.572 77.585 5.706 77.693 ;
     RECT  7.815 77.521 9.594 77.701 ;
     RECT  29.232 77.521 30.294 77.701 ;
     RECT  135.648 77.665 136.314 77.701 ;
     RECT  129.312 77.665 132.93 77.741 ;
     RECT  22.068 77.359 24.297 77.791 ;
     RECT  29.16 77.701 30.366 77.791 ;
     RECT  7.815 77.701 9.702 77.803 ;
     RECT  5.184 77.693 5.706 77.819 ;
     RECT  12.816 77.593 15.246 77.819 ;
     RECT  25.236 77.701 25.254 77.819 ;
     RECT  133.812 77.665 134.478 77.819 ;
     RECT  45.615 77.323 49.122 77.827 ;
     RECT  49.932 76.271 49.95 77.827 ;
     RECT  5.184 77.819 5.202 77.837 ;
     RECT  7.815 77.803 9.774 77.855 ;
     RECT  10.692 77.665 10.782 77.855 ;
     RECT  29.16 77.791 30.438 77.855 ;
     RECT  120.96 77.549 121.698 77.855 ;
     RECT  133.884 77.819 134.478 77.855 ;
     RECT  135.576 77.701 136.314 77.855 ;
     RECT  21.96 77.791 24.297 77.863 ;
     RECT  21.96 77.863 24.354 77.891 ;
     RECT  121.14 77.855 121.698 77.891 ;
     RECT  125.928 77.315 128.07 77.891 ;
     RECT  135.648 77.855 136.314 77.891 ;
     RECT  16.236 77.585 17.406 77.899 ;
     RECT  18.252 77.431 18.897 77.899 ;
     RECT  16.236 77.899 18.897 77.935 ;
     RECT  45.615 77.827 49.95 77.935 ;
     RECT  51.015 76.469 51.297 77.935 ;
     RECT  29.412 77.855 30.438 77.971 ;
     RECT  29.412 77.971 30.762 77.981 ;
     RECT  45.615 77.935 51.297 77.981 ;
     RECT  7.815 77.855 9.63 77.999 ;
     RECT  133.956 77.855 134.478 77.999 ;
     RECT  29.415 77.981 30.762 78.061 ;
     RECT  31.608 75.659 33.606 78.061 ;
     RECT  6.84 77.791 6.858 78.089 ;
     RECT  10.764 77.855 10.782 78.089 ;
     RECT  22.896 77.891 24.354 78.089 ;
     RECT  45.615 77.981 49.95 78.089 ;
     RECT  129.312 77.741 132.297 78.089 ;
     RECT  47.592 78.089 49.554 78.125 ;
     RECT  93.276 77.431 93.294 78.125 ;
     RECT  133.956 77.999 134.334 78.125 ;
     RECT  34.776 76.441 36.27 78.169 ;
     RECT  37.116 77.125 38.358 78.169 ;
     RECT  129.312 78.089 130.266 78.197 ;
     RECT  137.196 77.315 139.914 78.221 ;
     RECT  43.992 74.687 44.154 78.241 ;
     RECT  136.08 77.891 136.314 78.241 ;
     RECT  137.196 78.221 137.697 78.241 ;
     RECT  47.664 78.125 49.122 78.269 ;
     RECT  129.96 78.197 130.266 78.269 ;
     RECT  138.528 78.221 139.914 78.317 ;
     RECT  48.384 78.269 49.122 78.359 ;
     RECT  130.068 78.269 130.266 78.359 ;
     RECT  16.236 77.935 19.206 78.395 ;
     RECT  23.364 78.089 24.354 78.395 ;
     RECT  130.068 78.359 130.086 78.395 ;
     RECT  14.796 77.819 15.246 78.475 ;
     RECT  23.544 78.395 24.354 78.475 ;
     RECT  14.796 78.475 15.426 78.503 ;
     RECT  29.415 78.061 33.606 78.511 ;
     RECT  34.776 78.169 38.358 78.511 ;
     RECT  124.92 77.315 124.938 78.511 ;
     RECT  126.615 77.891 128.07 78.601 ;
     RECT  122.832 77.081 123.102 78.619 ;
     RECT  15.012 78.503 15.426 78.629 ;
     RECT  29.415 78.511 38.358 78.629 ;
     RECT  138.528 78.317 139.05 78.629 ;
     RECT  15.012 78.629 15.246 78.665 ;
     RECT  43.812 78.241 44.154 78.665 ;
     RECT  122.832 78.619 123.282 78.665 ;
     RECT  126.615 78.601 128.142 78.665 ;
     RECT  136.08 78.241 137.697 78.665 ;
     RECT  43.92 78.665 44.154 78.701 ;
     RECT  86.184 75.425 87.246 78.701 ;
     RECT  136.08 78.665 136.314 78.745 ;
     RECT  87.228 78.701 87.246 78.749 ;
     RECT  29.415 78.629 38.286 78.773 ;
     RECT  116.82 78.241 116.838 78.797 ;
     RECT  43.992 78.701 44.154 78.871 ;
     RECT  139.032 78.629 139.05 78.899 ;
     RECT  124.2 78.511 124.938 78.935 ;
     RECT  124.884 78.935 124.938 78.971 ;
     RECT  134.208 78.125 134.334 78.979 ;
     RECT  134.1 78.979 134.334 79.015 ;
     RECT  31.608 78.773 38.286 79.043 ;
     RECT  23.544 78.475 24.57 79.051 ;
     RECT  135.72 78.745 136.314 79.051 ;
     RECT  124.884 78.971 124.902 79.079 ;
     RECT  8.928 77.999 9.45 79.169 ;
     RECT  29.415 78.773 30.798 79.169 ;
     RECT  34.815 79.043 38.286 79.169 ;
     RECT  43.992 78.871 44.55 79.169 ;
     RECT  135.54 79.051 136.314 79.169 ;
     RECT  15.012 78.665 15.03 79.205 ;
     RECT  135.54 79.169 135.666 79.205 ;
     RECT  20.448 79.141 20.466 79.213 ;
     RECT  134.1 79.015 134.622 79.249 ;
     RECT  43.992 79.169 44.154 79.313 ;
     RECT  20.376 79.213 20.466 79.411 ;
     RECT  131.148 78.089 132.297 79.411 ;
     RECT  133.344 79.015 133.362 79.411 ;
     RECT  139.824 78.317 139.914 79.439 ;
     RECT  25.992 79.435 26.01 79.475 ;
     RECT  20.16 79.411 20.466 79.519 ;
     RECT  23.544 79.051 25.182 79.547 ;
     RECT  137.376 78.665 137.697 79.555 ;
     RECT  41.292 77.279 41.31 79.681 ;
     RECT  42.156 76.847 42.822 79.681 ;
     RECT  23.76 79.547 25.182 79.709 ;
     RECT  130.392 79.672 130.41 79.709 ;
     RECT  135.648 79.205 135.666 79.709 ;
     RECT  139.824 79.439 139.842 79.709 ;
     RECT  2.268 75.541 3.438 79.745 ;
     RECT  39.708 77.459 40.497 79.819 ;
     RECT  127.98 78.665 128.142 79.819 ;
     RECT  16.776 78.395 19.206 79.861 ;
     RECT  26.568 79.591 26.586 79.861 ;
     RECT  35.892 79.169 38.286 79.861 ;
     RECT  39.456 79.819 40.497 79.861 ;
     RECT  131.148 79.411 133.362 79.861 ;
     RECT  130.788 79.861 133.362 79.889 ;
     RECT  43.992 79.313 44.118 79.915 ;
     RECT  16.776 79.861 19.35 79.951 ;
     RECT  20.16 79.519 21.006 79.951 ;
     RECT  127.8 79.819 128.142 79.951 ;
     RECT  16.776 79.951 21.006 79.979 ;
     RECT  43.632 79.915 44.118 79.979 ;
     RECT  114.84 72.725 114.858 79.979 ;
     RECT  121.215 77.891 121.698 79.979 ;
     RECT  21.96 77.891 22.158 79.987 ;
     RECT  35.892 79.861 40.497 80.015 ;
     RECT  122.832 78.665 123.03 80.023 ;
     RECT  17.46 79.979 21.006 80.051 ;
     RECT  19.944 80.051 21.006 80.059 ;
     RECT  21.78 79.987 22.158 80.059 ;
     RECT  34.815 79.169 35.097 80.059 ;
     RECT  35.892 80.015 38.862 80.059 ;
     RECT  41.292 79.681 42.822 80.059 ;
     RECT  41.22 80.059 42.822 80.123 ;
     RECT  4.572 79.591 4.59 80.131 ;
     RECT  17.46 80.051 19.098 80.159 ;
     RECT  23.94 79.709 25.182 80.159 ;
     RECT  43.776 79.979 44.118 80.159 ;
     RECT  86.184 78.701 86.202 80.159 ;
     RECT  127.8 79.951 128.754 80.159 ;
     RECT  130.788 79.889 132.858 80.159 ;
     RECT  26.568 79.861 26.766 80.221 ;
     RECT  45.615 78.089 46.494 80.221 ;
     RECT  17.46 80.159 19.026 80.249 ;
     RECT  19.944 80.059 22.158 80.249 ;
     RECT  39.708 80.015 40.497 80.249 ;
     RECT  131.112 80.159 132.858 80.249 ;
     RECT  29.415 79.169 30.762 80.257 ;
     RECT  34.815 80.059 38.862 80.257 ;
     RECT  17.46 80.249 18.99 80.285 ;
     RECT  20.16 80.249 22.158 80.285 ;
     RECT  41.22 80.123 42.786 80.285 ;
     RECT  131.112 80.249 132.75 80.285 ;
     RECT  20.304 80.285 22.158 80.321 ;
     RECT  26.496 80.221 26.838 80.321 ;
     RECT  43.776 80.159 44.082 80.321 ;
     RECT  2.304 79.745 3.438 80.329 ;
     RECT  4.572 80.131 5.274 80.329 ;
     RECT  136.764 79.555 137.697 80.329 ;
     RECT  29.415 80.257 30.87 80.357 ;
     RECT  34.56 80.257 38.862 80.357 ;
     RECT  41.76 80.285 42.786 80.381 ;
     RECT  20.844 80.321 21.222 80.393 ;
     RECT  41.796 80.381 42.786 80.429 ;
     RECT  43.776 80.321 43.866 80.429 ;
     RECT  122.508 80.023 123.03 80.519 ;
     RECT  126.615 78.665 126.897 80.527 ;
     RECT  127.8 80.159 128.25 80.527 ;
     RECT  17.892 80.285 18.99 80.555 ;
     RECT  43.848 80.429 43.866 80.555 ;
     RECT  2.304 80.329 5.274 80.563 ;
     RECT  17.964 80.555 18.99 80.591 ;
     RECT  126.615 80.527 128.25 80.599 ;
     RECT  49.104 78.359 49.122 80.635 ;
     RECT  45.615 80.221 46.854 80.671 ;
     RECT  42.084 80.429 42.786 80.699 ;
     RECT  7.815 77.999 8.097 80.761 ;
     RECT  8.928 79.169 9.414 80.761 ;
     RECT  18 80.591 18.99 80.789 ;
     RECT  20.988 80.393 21.222 80.789 ;
     RECT  21.996 80.321 22.158 80.789 ;
     RECT  34.56 80.357 35.097 80.789 ;
     RECT  35.892 80.357 38.286 80.789 ;
     RECT  2.304 80.563 5.706 80.825 ;
     RECT  18 80.789 18.897 80.825 ;
     RECT  45.615 80.671 46.926 80.833 ;
     RECT  122.652 80.519 123.03 80.833 ;
     RECT  7.815 80.761 9.414 80.869 ;
     RECT  124.74 80.599 124.758 80.869 ;
     RECT  5.688 80.825 5.706 80.905 ;
     RECT  7.815 80.869 9.486 80.905 ;
     RECT  124.74 80.869 124.83 80.905 ;
     RECT  7.815 80.905 9.666 80.941 ;
     RECT  122.652 80.833 123.678 80.941 ;
     RECT  124.74 80.905 124.938 80.941 ;
     RECT  45.615 80.833 47.07 80.971 ;
     RECT  5.688 80.905 5.814 81.031 ;
     RECT  5.688 81.031 6.03 81.059 ;
     RECT  48.708 80.635 49.122 81.059 ;
     RECT  5.724 81.059 6.03 81.067 ;
     RECT  45.615 80.971 47.79 81.095 ;
     RECT  124.74 80.941 125.514 81.103 ;
     RECT  126.54 80.599 128.25 81.103 ;
     RECT  22.068 80.789 22.158 81.131 ;
     RECT  124.74 81.103 128.25 81.139 ;
     RECT  2.304 80.825 4.77 81.167 ;
     RECT  134.1 79.249 134.802 81.205 ;
     RECT  5.724 81.067 6.246 81.211 ;
     RECT  7.272 80.941 9.666 81.211 ;
     RECT  134.1 81.205 135.126 81.211 ;
     RECT  136.224 80.329 137.697 81.211 ;
     RECT  4.752 81.167 4.77 81.239 ;
     RECT  122.652 80.941 123.75 81.239 ;
     RECT  45.615 81.095 47.07 81.329 ;
     RECT  49.104 81.059 49.122 81.329 ;
     RECT  134.1 81.211 135.27 81.329 ;
     RECT  124.704 81.139 128.25 81.337 ;
     RECT  12.816 77.819 13.986 81.365 ;
     RECT  122.796 81.239 123.75 81.365 ;
     RECT  124.704 81.337 128.286 81.365 ;
     RECT  45.615 81.329 46.818 81.401 ;
     RECT  122.796 81.365 122.994 81.437 ;
     RECT  5.724 81.211 9.666 81.445 ;
     RECT  29.415 80.357 30.762 81.445 ;
     RECT  31.608 79.043 33.606 81.445 ;
     RECT  131.112 80.285 132.297 81.445 ;
     RECT  124.74 81.365 128.286 81.481 ;
     RECT  5.724 81.445 9.738 81.509 ;
     RECT  124.74 81.481 128.718 81.509 ;
     RECT  136.044 81.211 137.697 81.509 ;
     RECT  122.796 81.437 122.958 81.599 ;
     RECT  123.732 81.365 123.75 81.599 ;
     RECT  23.94 80.159 24.297 81.607 ;
     RECT  122.796 81.599 122.814 81.629 ;
     RECT  22.068 81.131 22.086 81.635 ;
     RECT  125.028 81.509 128.718 81.635 ;
     RECT  34.815 80.789 35.097 81.643 ;
     RECT  5.724 81.509 8.097 81.671 ;
     RECT  9.288 81.509 9.738 81.679 ;
     RECT  26.496 80.321 26.73 81.679 ;
     RECT  23.868 81.607 24.297 81.715 ;
     RECT  34.776 81.643 35.097 81.743 ;
     RECT  29.415 81.445 33.606 81.751 ;
     RECT  39.816 80.249 40.497 81.751 ;
     RECT  9.288 81.679 9.81 81.779 ;
     RECT  35.892 80.789 38.178 81.779 ;
     RECT  125.388 81.635 128.718 81.835 ;
     RECT  25.164 80.159 25.182 81.841 ;
     RECT  125.388 81.835 128.826 81.841 ;
     RECT  13.104 81.365 13.986 81.869 ;
     RECT  25.164 81.841 25.398 81.869 ;
     RECT  131.112 81.445 132.822 81.869 ;
     RECT  29.415 81.751 33.678 81.877 ;
     RECT  125.388 81.841 129.51 81.905 ;
     RECT  35.964 81.779 38.178 81.913 ;
     RECT  29.415 81.877 33.786 81.977 ;
     RECT  26.496 81.679 26.802 81.985 ;
     RECT  35.964 81.913 38.718 82.013 ;
     RECT  45.615 81.401 46.638 82.013 ;
     RECT  128.808 81.905 129.51 82.013 ;
     RECT  83.415 76.469 84.51 82.111 ;
     RECT  85.248 76.469 85.266 82.111 ;
     RECT  134.1 81.329 135.126 82.111 ;
     RECT  135.9 81.715 135.918 82.111 ;
     RECT  83.415 82.111 85.266 82.139 ;
     RECT  125.388 81.905 127.602 82.139 ;
     RECT  134.1 82.111 135.918 82.139 ;
     RECT  83.415 82.139 85.122 82.157 ;
     RECT  134.1 82.139 135.81 82.211 ;
     RECT  136.764 81.509 137.697 82.211 ;
     RECT  131.112 81.869 132.354 82.22 ;
     RECT  32.4 81.977 33.786 82.247 ;
     RECT  13.176 81.869 13.986 82.291 ;
     RECT  34.815 81.743 35.097 82.291 ;
     RECT  126.615 82.139 127.602 82.319 ;
     RECT  13.176 82.291 14.202 82.381 ;
     RECT  29.415 81.977 31.626 82.409 ;
     RECT  131.148 82.22 132.354 82.517 ;
     RECT  26.496 81.985 26.874 82.561 ;
     RECT  134.748 82.211 135.81 82.589 ;
     RECT  13.176 82.381 14.274 82.679 ;
     RECT  131.4 82.517 132.354 82.679 ;
     RECT  134.748 82.589 134.946 82.679 ;
     RECT  34.815 82.291 35.154 82.687 ;
     RECT  36.792 82.013 38.718 82.687 ;
     RECT  128.808 82.013 128.826 82.715 ;
     RECT  13.215 82.679 14.274 82.723 ;
     RECT  134.748 82.679 134.766 82.733 ;
     RECT  6.084 81.671 8.097 82.751 ;
     RECT  36.792 82.687 38.754 82.759 ;
     RECT  11.844 82.687 11.862 82.795 ;
     RECT  9.648 81.779 9.81 82.831 ;
     RECT  23.616 81.715 24.297 82.831 ;
     RECT  25.38 81.869 25.398 82.831 ;
     RECT  36.792 82.759 38.79 82.831 ;
     RECT  39.564 81.751 40.497 82.831 ;
     RECT  11.664 82.795 11.97 82.949 ;
     RECT  132.015 82.679 132.354 82.949 ;
     RECT  135.72 82.589 135.81 82.949 ;
     RECT  135.72 82.949 135.738 82.985 ;
     RECT  86.04 82.291 86.058 83.021 ;
     RECT  31.608 82.409 31.626 83.101 ;
     RECT  32.4 82.247 33.354 83.101 ;
     RECT  83.415 82.157 84.51 83.101 ;
     RECT  31.608 83.101 33.354 83.129 ;
     RECT  2.304 81.167 3.438 83.191 ;
     RECT  83.415 83.101 84.762 83.191 ;
     RECT  29.415 82.409 30.726 83.227 ;
     RECT  34.776 82.687 35.154 83.227 ;
     RECT  35.964 82.013 36.054 83.227 ;
     RECT  23.616 82.831 25.398 83.299 ;
     RECT  26.496 82.561 26.982 83.299 ;
     RECT  34.776 83.227 36.054 83.299 ;
     RECT  36.792 82.831 40.497 83.299 ;
     RECT  29.415 83.227 30.798 83.327 ;
     RECT  34.776 83.299 40.842 83.399 ;
     RECT  34.815 83.399 40.842 83.525 ;
     RECT  42.084 80.699 42.75 83.525 ;
     RECT  35.964 83.525 40.734 83.561 ;
     RECT  11.664 82.949 11.682 83.641 ;
     RECT  20.988 80.789 21.006 83.731 ;
     RECT  9.648 82.831 9.918 83.759 ;
     RECT  35.964 83.561 40.662 83.759 ;
     RECT  11.592 83.641 11.682 83.767 ;
     RECT  29.415 83.327 30.762 83.795 ;
     RECT  39.528 83.759 40.662 83.795 ;
     RECT  20.988 83.731 21.69 83.803 ;
     RECT  35.964 83.759 38.754 83.831 ;
     RECT  11.52 83.767 11.682 83.875 ;
     RECT  11.304 83.875 11.682 83.903 ;
     RECT  35.964 83.831 38.574 84.029 ;
     RECT  2.304 83.191 3.69 84.065 ;
     RECT  6.084 82.751 6.138 84.065 ;
     RECT  3.636 84.065 3.69 84.181 ;
     RECT  7.272 82.751 8.097 84.181 ;
     RECT  11.304 83.903 11.538 84.181 ;
     RECT  16.164 80.635 16.182 84.181 ;
     RECT  83.415 83.191 84.87 84.181 ;
     RECT  3.636 84.181 3.906 84.271 ;
     RECT  7.128 84.181 8.097 84.271 ;
     RECT  15.372 82.453 15.39 84.271 ;
     RECT  16.164 84.181 17.118 84.271 ;
     RECT  3.636 84.271 3.978 84.335 ;
     RECT  9.72 83.759 9.918 84.335 ;
     RECT  83.415 84.181 84.906 84.335 ;
     RECT  3.816 84.335 3.978 84.379 ;
     RECT  7.056 84.271 8.097 84.407 ;
     RECT  5.112 84.379 5.13 84.451 ;
     RECT  7.164 84.407 8.097 84.475 ;
     RECT  3.816 84.379 4.05 84.541 ;
     RECT  13.215 82.723 14.31 84.541 ;
     RECT  15.372 84.271 17.118 84.541 ;
     RECT  3.816 84.541 4.122 84.605 ;
     RECT  6.084 84.065 6.102 84.605 ;
     RECT  18.504 80.825 18.897 84.613 ;
     RECT  13.215 84.541 17.118 84.641 ;
     RECT  9.72 84.335 9.882 84.649 ;
     RECT  14.868 84.641 17.118 84.649 ;
     RECT  18.108 84.613 19.53 84.649 ;
     RECT  3.924 84.605 4.122 84.685 ;
     RECT  5.04 84.451 5.13 84.685 ;
     RECT  14.868 84.649 19.53 84.685 ;
     RECT  20.772 83.803 21.69 84.685 ;
     RECT  7.164 84.475 8.55 84.749 ;
     RECT  14.868 84.685 21.69 84.749 ;
     RECT  3.924 84.685 5.13 84.839 ;
     RECT  14.94 84.749 19.53 84.839 ;
     RECT  7.272 84.749 8.55 84.875 ;
     RECT  5.04 84.839 5.13 84.883 ;
     RECT  7.272 84.875 8.37 84.893 ;
     RECT  18.108 84.839 19.53 84.911 ;
     RECT  20.34 84.749 21.69 84.911 ;
     RECT  23.616 83.299 26.982 84.919 ;
     RECT  18.108 84.911 19.206 84.983 ;
     RECT  9.576 84.649 9.882 85.081 ;
     RECT  20.34 84.911 21.078 85.109 ;
     RECT  3.924 84.839 4.23 85.145 ;
     RECT  5.04 84.883 5.49 85.145 ;
     RECT  20.376 85.109 21.078 85.181 ;
     RECT  3.96 85.145 4.23 85.217 ;
     RECT  22.608 84.919 26.982 85.253 ;
     RECT  3.996 85.217 4.23 85.379 ;
     RECT  5.112 85.145 5.49 85.379 ;
     RECT  9.504 85.081 9.882 85.379 ;
     RECT  22.824 85.253 26.982 85.379 ;
     RECT  3.996 85.379 4.014 85.415 ;
     RECT  14.94 84.839 17.118 85.415 ;
     RECT  14.94 85.415 16.182 85.495 ;
     RECT  35.964 84.029 38.178 85.523 ;
     RECT  29.415 83.795 30.726 85.531 ;
     RECT  31.896 83.129 33.354 85.531 ;
     RECT  29.415 85.531 33.354 85.559 ;
     RECT  14.832 85.495 16.182 85.649 ;
     RECT  5.472 85.379 5.49 85.685 ;
     RECT  29.415 85.559 31.374 85.793 ;
     RECT  29.415 85.793 30.762 85.801 ;
     RECT  37.008 85.523 38.178 85.801 ;
     RECT  10.764 84.181 11.538 85.829 ;
     RECT  7.272 84.893 8.097 85.919 ;
     RECT  35.964 85.523 36.198 85.919 ;
     RECT  37.008 85.801 38.754 85.955 ;
     RECT  5.688 85.801 5.706 85.991 ;
     RECT  16.164 85.649 16.182 85.991 ;
     RECT  29.34 85.801 30.762 86.011 ;
     RECT  37.116 85.955 38.754 86.027 ;
     RECT  7.38 85.919 8.097 86.035 ;
     RECT  29.196 86.011 30.762 86.063 ;
     RECT  39.528 83.795 40.497 86.063 ;
     RECT  22.824 85.379 24.297 86.099 ;
     RECT  25.2 85.379 26.982 86.161 ;
     RECT  7.38 86.035 8.154 86.233 ;
     RECT  20.52 85.181 21.078 86.233 ;
     RECT  42.084 83.525 42.102 86.261 ;
     RECT  45.615 82.013 46.494 86.333 ;
     RECT  20.376 86.233 21.078 86.341 ;
     RECT  32.364 85.559 33.354 86.341 ;
     RECT  7.38 86.233 8.55 86.369 ;
     RECT  29.415 86.063 30.762 86.369 ;
     RECT  25.2 86.161 27.054 86.458 ;
     RECT  32.364 86.341 33.714 86.495 ;
     RECT  36 85.919 36.198 86.495 ;
     RECT  30.6 86.369 30.762 86.539 ;
     RECT  25.164 86.458 27.054 86.567 ;
     RECT  18.108 84.983 18.897 86.611 ;
     RECT  30.6 86.539 31.482 86.611 ;
     RECT  37.224 86.027 38.754 86.611 ;
     RECT  25.164 86.567 26.514 86.639 ;
     RECT  18.108 86.611 19.422 86.701 ;
     RECT  20.268 86.341 21.078 86.701 ;
     RECT  30.6 86.611 31.59 86.729 ;
     RECT  32.364 86.495 33.462 86.729 ;
     RECT  14.832 85.649 15.21 86.737 ;
     RECT  9.648 85.379 9.882 86.765 ;
     RECT  30.6 86.729 30.618 86.765 ;
     RECT  13.215 84.641 14.022 86.845 ;
     RECT  14.76 86.737 15.21 86.845 ;
     RECT  23.112 86.099 24.297 86.845 ;
     RECT  37.224 86.611 38.898 86.845 ;
     RECT  18.108 86.701 21.15 86.873 ;
     RECT  16.92 85.415 17.118 86.881 ;
     RECT  18.108 86.873 21.078 86.881 ;
     RECT  16.92 86.881 21.078 86.909 ;
     RECT  13.215 86.845 15.21 86.999 ;
     RECT  37.116 86.845 38.898 86.999 ;
     RECT  32.364 86.729 33.354 87.035 ;
     RECT  22.824 86.845 24.297 87.071 ;
     RECT  25.308 86.639 26.514 87.071 ;
     RECT  31.428 86.729 31.59 87.211 ;
     RECT  32.364 87.035 33.102 87.211 ;
     RECT  11.304 85.829 11.538 87.241 ;
     RECT  38.232 86.999 38.898 87.259 ;
     RECT  31.428 87.211 33.102 87.269 ;
     RECT  37.116 86.999 37.35 87.269 ;
     RECT  9.684 86.765 9.882 87.305 ;
     RECT  36.036 86.495 36.198 87.305 ;
     RECT  34.815 83.525 35.097 87.313 ;
     RECT  36.036 87.305 36.054 87.377 ;
     RECT  38.232 87.259 38.934 87.385 ;
     RECT  32.364 87.269 33.102 87.449 ;
     RECT  34.776 87.313 35.097 87.449 ;
     RECT  16.92 86.909 20.79 87.511 ;
     RECT  31.428 87.269 31.59 87.539 ;
     RECT  32.364 87.449 32.382 87.539 ;
     RECT  11.304 87.241 12.222 87.583 ;
     RECT  22.86 87.071 24.297 87.611 ;
     RECT  16.596 87.511 20.79 87.647 ;
     RECT  22.932 87.611 24.297 87.647 ;
     RECT  11.304 87.583 12.438 87.691 ;
     RECT  13.215 86.999 14.022 87.691 ;
     RECT  38.232 87.385 39.078 87.809 ;
     RECT  2.304 84.065 2.826 87.845 ;
     RECT  38.664 87.809 38.934 87.881 ;
     RECT  11.304 87.691 14.022 87.889 ;
     RECT  14.76 86.999 15.21 87.889 ;
     RECT  25.524 87.071 26.514 87.917 ;
     RECT  37.332 87.269 37.35 87.953 ;
     RECT  38.916 87.881 38.934 87.953 ;
     RECT  11.304 87.889 15.21 88.079 ;
     RECT  23.076 87.647 24.297 88.115 ;
     RECT  16.596 87.647 18.897 88.195 ;
     RECT  2.415 87.845 2.826 88.223 ;
     RECT  3.996 88.123 4.014 88.231 ;
     RECT  25.596 87.917 26.514 88.231 ;
     RECT  6.408 87.961 6.426 88.385 ;
     RECT  7.38 86.369 8.097 88.699 ;
     RECT  25.596 88.231 26.586 88.727 ;
     RECT  23.364 88.115 24.297 88.781 ;
     RECT  23.868 88.781 24.297 88.799 ;
     RECT  3.852 88.231 4.014 88.861 ;
     RECT  7.38 88.699 8.73 88.897 ;
     RECT  16.524 88.195 18.897 88.925 ;
     RECT  25.848 88.727 26.586 88.925 ;
     RECT  11.304 88.079 14.13 88.933 ;
     RECT  7.056 88.897 8.73 89.005 ;
     RECT  3.6 88.861 4.014 89.041 ;
     RECT  9.864 87.305 9.882 89.041 ;
     RECT  3.6 89.041 4.59 89.131 ;
     RECT  7.056 89.005 8.874 89.159 ;
     RECT  6.228 88.897 6.246 89.167 ;
     RECT  7.056 89.159 8.097 89.167 ;
     RECT  3.6 89.131 4.806 89.195 ;
     RECT  6.228 89.167 8.097 89.195 ;
     RECT  19.836 87.647 20.79 89.195 ;
     RECT  9.612 89.041 9.882 89.239 ;
     RECT  3.744 89.195 4.806 89.275 ;
     RECT  25.848 88.925 26.226 89.303 ;
     RECT  3.744 89.275 4.842 89.311 ;
     RECT  9.54 89.239 10.53 89.339 ;
     RECT  19.908 89.195 20.43 89.429 ;
     RECT  3.744 89.311 4.914 89.437 ;
     RECT  3.744 89.437 5.058 89.465 ;
     RECT  6.336 89.195 8.097 89.465 ;
     RECT  15.192 88.079 15.21 89.473 ;
     RECT  4.032 89.465 5.058 89.501 ;
     RECT  15.084 89.473 15.21 89.501 ;
     RECT  4.032 89.501 4.914 89.699 ;
     RECT  9.576 89.339 10.53 89.707 ;
     RECT  11.304 88.933 14.238 89.707 ;
     RECT  9.576 89.707 14.238 89.735 ;
     RECT  25.992 89.303 26.226 89.744 ;
     RECT  17.064 88.925 18.897 89.851 ;
     RECT  26.208 89.744 26.226 89.879 ;
     RECT  6.444 89.465 6.642 89.969 ;
     RECT  7.416 89.465 8.097 89.969 ;
     RECT  11.844 89.735 14.238 89.969 ;
     RECT  16.812 89.851 18.897 89.977 ;
     RECT  6.444 89.969 6.462 90.005 ;
     RECT  16.776 89.977 18.897 90.029 ;
     RECT  9.576 89.735 11.034 90.041 ;
     RECT  16.812 90.029 18.897 90.077 ;
     RECT  4.032 89.699 4.59 90.211 ;
     RECT  3.888 90.211 4.59 90.239 ;
     RECT  9.576 90.041 10.926 90.239 ;
     RECT  3.888 90.239 3.906 90.269 ;
     RECT  12.024 89.969 14.238 90.619 ;
     RECT  15.084 89.501 15.102 90.619 ;
     RECT  10.26 90.239 10.926 91.085 ;
     RECT  16.164 90.751 16.182 91.165 ;
     RECT  16.92 90.077 18.897 91.165 ;
     RECT  10.908 91.085 10.926 91.193 ;
     RECT  12.024 90.619 15.102 91.243 ;
     RECT  11.772 91.243 15.102 91.319 ;
     RECT  16.164 91.165 18.897 91.319 ;
     RECT  13.104 91.319 15.102 91.499 ;
     RECT  13.104 91.499 14.346 91.517 ;
     RECT  16.272 91.319 18.897 91.589 ;
     RECT  16.344 91.589 17.37 91.625 ;
     RECT  13.104 91.517 14.31 91.661 ;
     RECT  16.452 91.625 17.37 91.661 ;
     RECT  18.324 91.589 18.897 91.661 ;
     RECT  13.215 91.661 14.31 91.859 ;
     RECT  16.596 91.661 17.118 91.859 ;
     RECT  16.596 91.859 17.082 91.895 ;
     RECT  15.084 91.499 15.102 91.931 ;
     RECT  13.215 91.859 14.13 92.669 ;
     RECT  13.215 92.669 13.806 92.705 ;
     RECT  16.884 91.895 17.082 92.717 ;
     RECT  17.064 92.717 17.082 92.849 ;
     RECT  2.415 88.223 2.697 137.447 ;
     RECT  7.815 89.969 8.097 137.447 ;
     RECT  13.215 92.705 13.497 137.447 ;
     RECT  18.615 91.661 18.897 137.447 ;
     RECT  24.015 88.799 24.297 137.447 ;
     RECT  29.415 86.369 29.697 137.447 ;
     RECT  34.815 87.449 35.097 137.447 ;
     RECT  40.215 86.063 40.497 137.447 ;
     RECT  45.615 86.333 45.897 137.447 ;
     RECT  51.015 77.981 51.297 137.447 ;
     RECT  56.415 72.725 56.697 137.447 ;
     RECT  61.815 72.185 62.097 137.447 ;
     RECT  67.215 72.959 67.497 137.447 ;
     RECT  72.615 2.413 72.897 137.447 ;
     RECT  78.015 72.797 78.297 137.447 ;
     RECT  83.415 84.335 84.834 137.447 ;
     RECT  88.815 76.589 89.097 137.447 ;
     RECT  94.215 74.957 94.497 137.447 ;
     RECT  99.615 75.839 99.897 137.447 ;
     RECT  105.015 75.569 105.297 137.447 ;
     RECT  110.415 76.541 110.697 137.447 ;
     RECT  115.815 74.717 116.097 137.447 ;
     RECT  121.215 79.979 121.497 137.447 ;
     RECT  126.615 82.319 126.897 137.447 ;
     RECT  132.015 82.949 132.297 137.447 ;
     RECT  137.415 82.211 137.697 137.447 ;
     RECT  2.415 137.447 2.505 137.717 ;
     RECT  7.815 137.447 7.905 137.717 ;
     RECT  13.215 137.447 13.305 137.717 ;
     RECT  18.615 137.447 18.705 137.717 ;
     RECT  24.015 137.447 24.105 137.717 ;
     RECT  29.415 137.447 29.505 137.717 ;
     RECT  34.815 137.447 34.905 137.717 ;
     RECT  40.215 137.447 40.305 137.717 ;
     RECT  45.615 137.447 45.705 137.717 ;
     RECT  51.015 137.447 51.105 137.717 ;
     RECT  56.415 137.447 56.505 137.717 ;
     RECT  61.815 137.447 61.905 137.717 ;
     RECT  67.215 137.447 67.305 137.717 ;
     RECT  72.615 137.447 72.705 137.717 ;
     RECT  78.015 137.447 78.105 137.717 ;
     RECT  83.415 137.447 83.505 137.717 ;
     RECT  88.815 137.447 88.905 137.717 ;
     RECT  94.215 137.447 94.305 137.717 ;
     RECT  99.615 137.447 99.705 137.717 ;
     RECT  105.015 137.447 105.105 137.717 ;
     RECT  110.415 137.447 110.505 137.717 ;
     RECT  115.815 137.447 115.905 137.717 ;
     RECT  121.215 137.447 121.305 137.717 ;
     RECT  126.615 137.447 126.705 137.717 ;
     RECT  132.015 137.447 132.105 137.717 ;
     RECT  137.415 137.447 137.505 137.717 ;
     RECT  84.312 137.447 84.834 139.901 ;
    LAYER M4 ;
     RECT  0.037 61.68 0.06 61.704 ;
     RECT  0.06 61.68 0.179 70.056 ;
     RECT  0.097 58.704 0.317 58.728 ;
     RECT  0.179 61.776 0.605 70.056 ;
     RECT  0.605 61.776 0.929 69.96 ;
     RECT  0.929 61.776 2.293 69.864 ;
     RECT  0.037 48.432 2.408 48.456 ;
     RECT  2.293 61.68 2.408 69.864 ;
     RECT  2.408 2.148 2.512 137.712 ;
     RECT  2.512 2.418 2.704 137.442 ;
     RECT  2.704 62.832 2.765 64.68 ;
     RECT  2.704 66 2.765 66.024 ;
     RECT  2.704 67.824 2.873 69.864 ;
     RECT  2.765 63.888 2.909 64.68 ;
     RECT  2.765 62.832 3.125 62.856 ;
     RECT  2.873 69.024 3.197 69.864 ;
     RECT  2.909 64.128 3.845 64.68 ;
     RECT  3.805 80.928 3.971 80.952 ;
     RECT  3.877 90.24 3.971 90.264 ;
     RECT  2.704 48.432 4.061 48.456 ;
     RECT  3.197 69.024 4.061 69.048 ;
     RECT  3.98 84.816 4.067 84.84 ;
     RECT  2.873 67.824 4.205 67.992 ;
     RECT  4.172 77.472 4.259 77.496 ;
     RECT  4.021 89.904 4.547 89.928 ;
     RECT  3.845 64.656 4.853 64.68 ;
     RECT  4.777 89.472 5.069 89.496 ;
     RECT  4.993 59.568 5.123 59.592 ;
     RECT  5.132 77.808 5.219 77.832 ;
     RECT  5.516 55.248 5.603 55.272 ;
     RECT  5.533 74.16 5.699 74.184 ;
     RECT  4.205 67.824 5.893 67.848 ;
     RECT  5.821 68.928 5.893 68.952 ;
     RECT  5.713 55.392 5.933 55.848 ;
     RECT  5.713 61.824 5.996 61.848 ;
     RECT  5.996 61.584 6.083 61.848 ;
     RECT  6.037 63.888 6.121 63.912 ;
     RECT  6.083 61.824 6.275 61.848 ;
     RECT  5.893 67.824 6.275 68.952 ;
     RECT  5.749 81.312 6.275 81.336 ;
     RECT  5.933 55.392 6.419 55.416 ;
     RECT  6.38 70.272 6.467 70.296 ;
     RECT  6.421 89.952 6.563 89.976 ;
     RECT  6.275 68.928 6.833 68.952 ;
     RECT  6.829 73.344 6.956 73.368 ;
     RECT  6.275 67.824 7.808 67.848 ;
     RECT  6.853 70.128 7.808 70.152 ;
     RECT  6.956 73.344 7.808 73.512 ;
     RECT  7.141 84.72 7.808 84.744 ;
     RECT  7.532 86.16 7.808 86.184 ;
     RECT  7.621 88.992 7.808 89.016 ;
     RECT  7.808 2.148 7.912 137.712 ;
     RECT  7.912 2.418 8.104 137.442 ;
     RECT  8.104 52.032 8.165 52.056 ;
     RECT  8.104 77.808 8.284 77.832 ;
     RECT  8.104 84.48 8.381 84.888 ;
     RECT  8.381 84.48 8.531 84.552 ;
     RECT  8.104 59.232 8.597 59.832 ;
     RECT  8.104 80.928 8.597 81.384 ;
     RECT  8.531 84.48 8.627 84.504 ;
     RECT  8.597 59.808 8.819 59.832 ;
     RECT  8.104 67.68 8.921 67.704 ;
     RECT  8.104 55.248 8.957 55.848 ;
     RECT  8.104 70.992 9.029 71.016 ;
     RECT  8.957 55.824 9.245 55.848 ;
     RECT  9.205 79.2 9.292 79.224 ;
     RECT  8.597 80.928 9.497 80.952 ;
     RECT  9.596 51.504 9.683 51.528 ;
     RECT  9.733 77.808 9.82 77.832 ;
     RECT  8.104 62.16 9.929 62.184 ;
     RECT  9.925 59.712 9.997 59.736 ;
     RECT  9.997 59.28 10.259 59.736 ;
     RECT  9.829 75.168 10.259 75.192 ;
     RECT  10.22 56.16 10.307 56.184 ;
     RECT  10.22 73.776 10.307 73.8 ;
     RECT  10.393 65.424 10.835 65.448 ;
     RECT  11.285 62.736 11.369 62.76 ;
     RECT  11.557 52.176 11.644 52.2 ;
     RECT  11.749 91.248 11.836 91.272 ;
     RECT  11.581 49.632 11.939 49.656 ;
     RECT  11.9 87.552 11.987 87.576 ;
     RECT  11.989 68.688 12.236 68.712 ;
     RECT  12.236 68.592 13.045 68.712 ;
     RECT  12.769 55.344 13.208 55.368 ;
     RECT  13.093 57.552 13.208 57.576 ;
     RECT  13.045 68.592 13.208 68.808 ;
     RECT  13.201 70.56 13.208 70.584 ;
     RECT  13.093 75.12 13.208 75.144 ;
     RECT  12.62 76.368 13.208 76.392 ;
     RECT  13.208 2.148 13.312 137.712 ;
     RECT  13.312 2.418 13.504 137.442 ;
     RECT  13.504 70.224 13.619 71.4 ;
     RECT  13.504 79.968 13.619 79.992 ;
     RECT  13.504 82.176 13.708 82.2 ;
     RECT  13.619 70.56 13.709 70.584 ;
     RECT  13.504 65.136 14.243 65.16 ;
     RECT  13.504 92.64 14.243 92.664 ;
     RECT  13.504 76.224 14.257 76.248 ;
     RECT  13.504 52.944 14.291 52.968 ;
     RECT  13.504 60.192 14.291 60.36 ;
     RECT  13.504 62.16 14.339 62.184 ;
     RECT  13.504 90.624 14.357 91.512 ;
     RECT  14.357 90.624 14.501 90.648 ;
     RECT  13.504 66.336 14.609 66.36 ;
     RECT  14.869 85.92 14.969 85.944 ;
     RECT  15.001 85.392 15.113 85.416 ;
     RECT  14.291 60.288 15.473 60.36 ;
     RECT  15.473 60.336 15.545 60.36 ;
     RECT  15.973 51.648 16.045 51.672 ;
     RECT  15.973 71.376 16.057 71.4 ;
     RECT  16.045 51.456 16.145 51.672 ;
     RECT  15.973 61.872 16.193 61.896 ;
     RECT  16.145 51.024 16.229 51.672 ;
     RECT  16.153 73.632 16.261 73.656 ;
     RECT  16.261 73.2 16.268 73.656 ;
     RECT  16.189 55.68 16.333 55.704 ;
     RECT  16.268 73.2 16.355 73.992 ;
     RECT  16.229 51.456 16.409 51.672 ;
     RECT  15.973 67.248 16.445 67.272 ;
     RECT  15.397 84.384 16.477 84.408 ;
     RECT  16.225 78.096 16.547 78.12 ;
     RECT  16.355 73.2 16.553 73.848 ;
     RECT  16.477 84.336 16.585 84.408 ;
     RECT  16.513 60.288 16.729 60.312 ;
     RECT  16.729 60.24 16.913 60.312 ;
     RECT  16.765 90 16.913 90.024 ;
     RECT  16.837 92.688 16.924 92.712 ;
     RECT  16.333 55.488 16.949 55.704 ;
     RECT  16.949 55.488 16.985 55.512 ;
     RECT  16.585 84.336 17.093 84.888 ;
     RECT  16.913 60.288 17.129 60.312 ;
     RECT  17.093 84.864 17.129 84.888 ;
     RECT  17.077 88.944 17.237 88.968 ;
     RECT  17.365 54.528 17.413 54.552 ;
     RECT  17.413 54.336 17.453 54.552 ;
     RECT  18.373 48.672 18.608 48.696 ;
     RECT  17.453 54.336 18.608 54.456 ;
     RECT  18.205 67.056 18.608 67.08 ;
     RECT  18.469 76.464 18.608 76.488 ;
     RECT  17.653 80.784 18.608 80.808 ;
     RECT  18.085 91.152 18.608 91.176 ;
     RECT  18.608 2.148 18.712 137.712 ;
     RECT  18.712 2.418 18.904 137.442 ;
     RECT  18.904 59.472 19.043 59.496 ;
     RECT  18.904 69.984 19.109 70.104 ;
     RECT  19.109 70.08 19.217 70.104 ;
     RECT  18.904 73.008 19.829 73.512 ;
     RECT  19.897 88.944 19.981 88.968 ;
     RECT  19.957 63.504 20.081 63.528 ;
     RECT  19.969 64.896 20.117 64.92 ;
     RECT  20.108 84.72 20.195 84.744 ;
     RECT  20.149 58.512 20.291 58.536 ;
     RECT  20.533 54.624 20.62 54.648 ;
     RECT  20.473 51.36 20.621 51.72 ;
     RECT  21.049 80.4 21.133 80.424 ;
     RECT  20.977 48.96 21.157 48.984 ;
     RECT  21.157 48.672 21.244 48.984 ;
     RECT  21.244 48.96 21.485 48.984 ;
     RECT  21.109 60.432 21.665 60.456 ;
     RECT  20.621 51.696 21.737 51.72 ;
     RECT  21.949 63.216 22.211 63.24 ;
     RECT  19.829 73.008 22.277 73.032 ;
     RECT  22.273 58.176 22.381 58.2 ;
     RECT  22.693 85.2 22.781 85.224 ;
     RECT  22.381 58.128 22.853 58.2 ;
     RECT  22.853 58.128 22.925 58.152 ;
     RECT  22.849 55.776 23.033 55.8 ;
     RECT  22.885 73.536 23.324 73.608 ;
     RECT  23.893 48.72 24.008 48.744 ;
     RECT  23.821 50.016 24.008 50.04 ;
     RECT  23.125 64.32 24.008 64.344 ;
     RECT  23.845 69.408 24.008 69.432 ;
     RECT  23.641 70.56 24.008 70.584 ;
     RECT  23.324 73.536 24.008 73.8 ;
     RECT  23.893 77.568 24.008 77.592 ;
     RECT  23.324 88.752 24.008 88.776 ;
     RECT  24.008 2.148 24.112 137.712 ;
     RECT  24.112 2.418 24.304 137.442 ;
     RECT  24.304 48.96 24.419 48.984 ;
     RECT  24.304 64.032 24.419 64.968 ;
     RECT  24.304 76.32 24.515 76.344 ;
     RECT  24.419 64.032 24.563 64.056 ;
     RECT  24.304 50.016 24.653 50.04 ;
     RECT  24.304 83.28 25.165 83.832 ;
     RECT  25.165 83.808 25.481 83.832 ;
     RECT  25.405 69.696 25.693 69.72 ;
     RECT  25.369 86.544 25.733 86.568 ;
     RECT  25.676 48.624 25.763 48.648 ;
     RECT  25.477 58.464 25.805 58.68 ;
     RECT  25.805 58.656 25.841 58.68 ;
     RECT  25.693 69.552 25.948 69.72 ;
     RECT  25.948 69.552 26.021 69.864 ;
     RECT  25.669 89.712 26.021 89.736 ;
     RECT  25.957 79.44 26.044 79.464 ;
     RECT  24.304 73.776 26.125 73.992 ;
     RECT  26.053 50.4 26.14 50.424 ;
     RECT  26.089 86.592 26.201 86.616 ;
     RECT  26.125 73.776 26.243 74.088 ;
     RECT  26.021 69.696 26.245 69.864 ;
     RECT  26.243 73.776 26.301 73.992 ;
     RECT  26.301 73.824 26.309 73.992 ;
     RECT  26.245 69.696 26.444 70.152 ;
     RECT  26.309 73.968 26.489 73.992 ;
     RECT  26.444 69.696 26.531 70.536 ;
     RECT  26.531 69.696 26.597 70.344 ;
     RECT  26.597 69.84 26.633 70.344 ;
     RECT  26.633 70.32 26.857 70.344 ;
     RECT  26.917 58.176 27.133 58.2 ;
     RECT  26.773 55.488 27.205 55.512 ;
     RECT  27.133 58.176 27.205 58.344 ;
     RECT  27.205 55.344 27.277 55.512 ;
     RECT  27.133 51.168 27.421 51.192 ;
     RECT  27.277 55.344 27.461 55.848 ;
     RECT  27.205 58.128 27.529 58.344 ;
     RECT  27.461 55.392 27.533 55.848 ;
     RECT  27.349 74.16 27.601 74.184 ;
     RECT  27.421 50.976 27.677 51.192 ;
     RECT  27.601 73.872 27.713 74.184 ;
     RECT  26.881 48.432 27.749 48.456 ;
     RECT  27.692 72.72 27.779 72.744 ;
     RECT  27.74 47.232 27.827 47.256 ;
     RECT  27.533 55.488 27.857 55.848 ;
     RECT  27.385 66.192 27.893 66.216 ;
     RECT  27.857 55.488 27.965 55.656 ;
     RECT  27.965 55.488 28.073 55.512 ;
     RECT  27.529 58.128 28.397 58.536 ;
     RECT  28.213 67.392 28.433 67.416 ;
     RECT  29.221 70.032 29.269 70.056 ;
     RECT  29.249 72.96 29.269 72.984 ;
     RECT  28.501 50.928 29.408 50.952 ;
     RECT  28.397 58.128 29.408 58.44 ;
     RECT  29.269 69.84 29.408 70.056 ;
     RECT  29.269 72.96 29.408 73.608 ;
     RECT  29.269 77.952 29.408 77.976 ;
     RECT  29.269 79.2 29.408 79.224 ;
     RECT  29.185 86.016 29.408 86.04 ;
     RECT  29.408 2.148 29.512 137.712 ;
     RECT  29.512 2.418 29.704 137.442 ;
     RECT  29.704 58.128 29.765 58.248 ;
     RECT  29.765 58.224 29.801 58.248 ;
     RECT  29.704 82.416 30.124 82.44 ;
     RECT  29.704 78.768 30.629 78.792 ;
     RECT  29.704 47.856 31.061 47.88 ;
     RECT  31.045 82.128 31.244 82.152 ;
     RECT  31.244 82.032 31.313 82.152 ;
     RECT  31.313 82.032 31.331 82.056 ;
     RECT  31.201 71.184 31.529 71.208 ;
     RECT  31.589 87.216 31.673 87.24 ;
     RECT  31.885 78.816 31.921 78.84 ;
     RECT  31.921 78.72 31.957 78.84 ;
     RECT  31.957 78.72 32.105 79.032 ;
     RECT  32.105 78.72 32.141 78.84 ;
     RECT  32.141 78.72 32.177 78.744 ;
     RECT  32.173 50.304 32.321 50.328 ;
     RECT  32.101 67.344 32.425 67.368 ;
     RECT  32.353 70.656 32.492 70.68 ;
     RECT  32.492 70.656 32.501 71.016 ;
     RECT  32.501 70.992 32.579 71.016 ;
     RECT  32.425 67.344 32.681 67.656 ;
     RECT  32.78 82.128 32.785 82.152 ;
     RECT  32.681 67.632 32.825 67.656 ;
     RECT  32.785 81.936 32.867 82.152 ;
     RECT  32.389 85.776 32.933 85.8 ;
     RECT  32.867 81.936 33.149 81.96 ;
     RECT  33.289 78.336 33.443 78.36 ;
     RECT  33.649 51.792 34.333 51.816 ;
     RECT  34.333 51.744 34.808 51.816 ;
     RECT  34.765 61.392 34.808 61.416 ;
     RECT  34.213 71.28 34.808 71.304 ;
     RECT  34.808 2.148 34.912 137.712 ;
     RECT  34.912 2.418 35.104 137.442 ;
     RECT  35.104 61.392 35.201 61.416 ;
     RECT  35.104 58.176 35.237 58.248 ;
     RECT  35.104 83.28 35.273 83.304 ;
     RECT  35.237 58.176 35.309 58.2 ;
     RECT  35.104 75.504 35.309 75.528 ;
     RECT  35.104 65.952 35.381 66.216 ;
     RECT  35.381 66.192 35.453 66.216 ;
     RECT  35.104 53.568 36.245 53.592 ;
     RECT  36.601 78.432 36.925 78.456 ;
     RECT  36.925 78.432 37.043 78.552 ;
     RECT  37.043 78.432 37.145 78.456 ;
     RECT  37.285 87.168 37.619 87.192 ;
     RECT  36.469 81.984 37.753 82.008 ;
     RECT  37.861 66.096 37.897 66.12 ;
     RECT  37.753 81.648 38.009 82.008 ;
     RECT  38.041 78.672 38.261 78.696 ;
     RECT  38.009 81.984 38.297 82.008 ;
     RECT  37.897 66 38.545 66.12 ;
     RECT  38.545 65.616 38.837 66.12 ;
     RECT  35.104 51.744 38.873 51.768 ;
     RECT  38.041 71.184 38.945 71.208 ;
     RECT  38.876 87.264 38.963 87.288 ;
     RECT  38.761 52.944 39.049 52.968 ;
     RECT  38.833 58.56 39.125 58.584 ;
     RECT  38.837 65.616 39.125 66.024 ;
     RECT  39.049 52.944 39.193 53.88 ;
     RECT  39.125 66 39.197 66.024 ;
     RECT  39.589 77.088 39.781 77.112 ;
     RECT  39.193 52.512 40.208 53.88 ;
     RECT  39.661 68.736 40.208 68.76 ;
     RECT  39.781 77.088 40.208 77.496 ;
     RECT  39.445 79.824 40.208 79.848 ;
     RECT  39.5 83.424 40.208 83.448 ;
     RECT  40.208 2.148 40.312 137.712 ;
     RECT  40.312 2.418 40.504 137.442 ;
     RECT  40.504 77.088 41.141 77.112 ;
     RECT  40.504 52.416 41.573 52.44 ;
     RECT  41.749 80.352 42.617 80.376 ;
     RECT  42.505 73.584 42.755 73.608 ;
     RECT  42.649 64.32 42.941 64.344 ;
     RECT  42.613 50.112 43.085 50.136 ;
     RECT  43.573 79.92 43.661 79.944 ;
     RECT  43.837 80.256 43.985 80.28 ;
     RECT  43.909 78.672 44.021 78.696 ;
     RECT  44.485 78.912 44.579 79.128 ;
     RECT  40.504 53.856 45.452 53.88 ;
     RECT  45.061 47.52 45.608 47.544 ;
     RECT  45.452 53.472 45.608 53.88 ;
     RECT  44.629 56.448 45.608 56.472 ;
     RECT  44.579 79.104 45.608 79.128 ;
     RECT  45.608 2.148 45.712 137.712 ;
     RECT  45.712 2.418 45.904 137.442 ;
     RECT  45.904 47.952 46.109 47.976 ;
     RECT  45.904 72.576 46.115 72.6 ;
     RECT  45.904 59.76 46.739 59.784 ;
     RECT  45.904 68.112 46.829 68.28 ;
     RECT  46.829 68.256 46.933 68.28 ;
     RECT  45.904 81.216 47.041 81.24 ;
     RECT  46.961 62.736 47.045 62.76 ;
     RECT  46.933 68.256 47.045 68.424 ;
     RECT  45.904 56.016 47.081 56.376 ;
     RECT  47.041 80.976 47.081 81.24 ;
     RECT  47.081 56.352 47.189 56.376 ;
     RECT  47.005 64.848 47.315 64.872 ;
     RECT  47.317 47.424 47.404 47.448 ;
     RECT  47.185 77.904 47.653 77.928 ;
     RECT  47.045 68.256 47.657 68.28 ;
     RECT  47.081 80.976 47.845 81 ;
     RECT  47.653 77.808 47.893 77.928 ;
     RECT  47.893 77.808 48.017 78.12 ;
     RECT  47.989 74.976 48.076 75 ;
     RECT  48.017 77.808 48.089 77.928 ;
     RECT  48.265 54.912 48.557 54.936 ;
     RECT  48.089 77.808 48.845 77.88 ;
     RECT  48.697 58.944 48.851 58.968 ;
     RECT  48.901 60.288 48.989 60.312 ;
     RECT  48.845 77.808 49.025 77.832 ;
     RECT  48.697 51.024 49.043 51.048 ;
     RECT  48.997 57.12 49.045 57.144 ;
     RECT  49.045 57.12 49.132 57.24 ;
     RECT  49.189 75.168 49.276 75.192 ;
     RECT  45.904 53.856 49.477 53.88 ;
     RECT  49.477 53.856 49.565 54.072 ;
     RECT  49.132 57.12 49.571 57.144 ;
     RECT  50.725 46.656 51.008 46.68 ;
     RECT  50.497 49.2 51.008 49.224 ;
     RECT  49.565 53.856 51.008 53.88 ;
     RECT  50.725 55.488 51.008 55.512 ;
     RECT  50.252 59.04 51.008 59.064 ;
     RECT  50.389 64.848 51.008 64.872 ;
     RECT  47.269 73.344 51.008 73.368 ;
     RECT  50.581 77.952 51.008 77.976 ;
     RECT  51.008 2.148 51.112 137.712 ;
     RECT  51.112 2.418 51.304 137.442 ;
     RECT  51.304 53.856 51.509 54.744 ;
     RECT  51.304 62.352 51.58 62.376 ;
     RECT  51.304 65.28 51.58 65.928 ;
     RECT  51.304 73.344 51.725 74.088 ;
     RECT  51.58 65.28 51.875 65.736 ;
     RECT  51.725 73.344 51.875 73.368 ;
     RECT  51.875 65.28 51.905 65.496 ;
     RECT  51.304 58.8 52.121 59.016 ;
     RECT  52.121 58.992 52.157 59.016 ;
     RECT  52.7 48.384 52.787 48.408 ;
     RECT  53.665 71.328 53.891 71.352 ;
     RECT  53.852 67.776 53.939 67.8 ;
     RECT  53.557 59.904 53.957 59.928 ;
     RECT  54.025 52.752 54.097 52.776 ;
     RECT  53.701 50.784 54.131 50.808 ;
     RECT  54.097 52.704 54.205 52.776 ;
     RECT  54.205 52.704 54.461 52.824 ;
     RECT  54.241 64.752 54.637 64.776 ;
     RECT  54.169 70.704 54.713 71.304 ;
     RECT  54.637 64.752 54.785 64.92 ;
     RECT  54.713 70.896 54.857 71.304 ;
     RECT  54.857 71.184 54.889 71.304 ;
     RECT  54.889 71.184 54.893 71.832 ;
     RECT  54.893 71.28 54.929 71.832 ;
     RECT  54.461 52.752 55.037 52.824 ;
     RECT  54.757 50.016 55.073 50.04 ;
     RECT  54.785 64.752 55.217 64.776 ;
     RECT  55.333 49.968 55.42 49.992 ;
     RECT  54.929 71.808 55.525 71.832 ;
     RECT  51.509 53.856 56.293 54.12 ;
     RECT  55.285 47.568 56.408 47.592 ;
     RECT  56.293 49.584 56.408 49.608 ;
     RECT  55.621 52.464 56.408 52.488 ;
     RECT  56.293 53.856 56.408 54.456 ;
     RECT  55.537 60.624 56.408 60.648 ;
     RECT  55.532 62.592 56.408 62.616 ;
     RECT  55.285 65.904 56.408 66.36 ;
     RECT  55.525 71.808 56.408 71.928 ;
     RECT  56.408 2.148 56.512 137.712 ;
     RECT  56.512 2.418 56.704 137.442 ;
     RECT  56.704 65.904 57.052 65.928 ;
     RECT  56.704 57.6 57.521 57.624 ;
     RECT  56.704 70.608 57.587 70.632 ;
     RECT  56.704 66.912 57.635 66.936 ;
     RECT  56.704 62.736 57.773 62.76 ;
     RECT  57.788 63.744 57.875 63.768 ;
     RECT  56.704 53.808 58.165 54.12 ;
     RECT  57.877 49.248 58.277 49.272 ;
     RECT  58.165 53.616 58.529 54.12 ;
     RECT  58.529 53.712 58.588 54.12 ;
     RECT  58.117 70.752 58.601 70.776 ;
     RECT  58.588 53.76 58.673 54.12 ;
     RECT  58.673 53.76 58.781 54.024 ;
     RECT  58.933 49.392 59.02 49.416 ;
     RECT  58.781 53.76 59.069 53.976 ;
     RECT  59.069 53.952 59.285 53.976 ;
     RECT  59.269 62.736 59.357 62.76 ;
     RECT  59.269 60.624 59.429 60.648 ;
     RECT  59.372 51.024 59.459 51.048 ;
     RECT  60.289 54.768 60.419 54.792 ;
     RECT  60.421 68.352 60.689 68.376 ;
     RECT  61.669 52.56 61.808 52.584 ;
     RECT  61.441 57.84 61.808 57.864 ;
     RECT  60.721 70.848 61.808 70.872 ;
     RECT  61.808 2.148 61.912 137.712 ;
     RECT  61.912 2.418 62.104 137.442 ;
     RECT  64.249 54.72 64.685 54.744 ;
     RECT  67.208 2.148 67.312 137.712 ;
     RECT  67.312 2.418 67.504 137.442 ;
     RECT  69.317 50.112 69.401 50.136 ;
     RECT  70.892 50.112 70.979 50.136 ;
     RECT  72.608 2.148 72.712 137.712 ;
     RECT  72.712 2.418 72.904 137.442 ;
     RECT  78.008 2.148 78.112 137.712 ;
     RECT  78.112 2.418 78.304 137.442 ;
     RECT  78.304 71.856 79.811 71.88 ;
     RECT  80.809 71.664 81.173 71.688 ;
     RECT  83.408 2.148 83.512 137.712 ;
     RECT  83.512 2.418 83.704 137.442 ;
     RECT  83.704 63.744 83.843 63.768 ;
     RECT  83.704 71.136 83.987 71.832 ;
     RECT  83.987 71.136 84.131 71.16 ;
     RECT  83.704 76.656 84.131 76.68 ;
     RECT  83.704 50.064 84.371 50.232 ;
     RECT  84.229 139.872 84.476 139.896 ;
     RECT  84.371 50.064 84.563 50.088 ;
     RECT  84.476 139.104 84.563 139.896 ;
     RECT  83.704 91.248 84.673 91.752 ;
     RECT  84.673 91.248 84.737 91.272 ;
     RECT  83.704 65.664 84.748 65.688 ;
     RECT  84.563 139.872 84.845 139.896 ;
     RECT  84.764 46.512 84.851 46.536 ;
     RECT  84.841 42.72 84.925 42.744 ;
     RECT  84.941 76.224 85.025 76.248 ;
     RECT  85.052 43.008 85.139 43.032 ;
     RECT  85.093 82.128 85.177 82.152 ;
     RECT  85.189 46.8 85.276 46.824 ;
     RECT  85.772 59.712 85.859 59.736 ;
     RECT  85.477 44.832 86.003 44.856 ;
     RECT  86.156 27.84 86.465 27.864 ;
     RECT  86.389 70.512 86.473 70.536 ;
     RECT  86.317 41.184 86.713 41.208 ;
     RECT  86.641 24.528 86.725 24.552 ;
     RECT  86.713 41.184 86.753 41.4 ;
     RECT  86.677 74.928 86.819 74.952 ;
     RECT  86.965 25.008 87.049 25.032 ;
     RECT  87.02 17.616 87.107 17.64 ;
     RECT  87.109 55.152 87.145 55.176 ;
     RECT  86.749 78.672 87.217 78.696 ;
     RECT  87.212 36.192 87.299 36.216 ;
     RECT  86.753 41.376 87.473 41.4 ;
     RECT  87.145 55.152 87.545 55.272 ;
     RECT  87.548 37.248 87.635 37.272 ;
     RECT  87.545 55.152 87.653 55.176 ;
     RECT  87.205 66.288 87.829 66.312 ;
     RECT  87.829 66.288 88.021 66.936 ;
     RECT  87.98 14.352 88.477 14.376 ;
     RECT  88.076 11.904 88.808 11.928 ;
     RECT  88.477 14.208 88.808 14.376 ;
     RECT  88.477 17.136 88.808 17.16 ;
     RECT  88.213 33.024 88.808 33.048 ;
     RECT  88.028 41.088 88.808 41.112 ;
     RECT  88.021 66.24 88.808 66.936 ;
     RECT  88.549 76.56 88.808 76.584 ;
     RECT  87.217 78.672 88.808 78.744 ;
     RECT  88.808 2.148 88.912 137.712 ;
     RECT  88.912 2.418 89.104 137.442 ;
     RECT  89.104 66.288 89.165 66.552 ;
     RECT  89.104 14.4 89.219 14.424 ;
     RECT  89.165 66.48 89.309 66.552 ;
     RECT  89.104 12.528 89.315 12.552 ;
     RECT  89.309 66.528 89.363 66.552 ;
     RECT  89.104 41.088 90.083 41.112 ;
     RECT  90.241 72.096 90.313 72.12 ;
     RECT  90.313 72.096 90.563 72.312 ;
     RECT  90.557 28.08 90.565 28.104 ;
     RECT  90.517 24.912 90.604 24.936 ;
     RECT  90.563 72.096 90.605 72.12 ;
     RECT  90.565 28.08 90.641 28.488 ;
     RECT  89.104 74.928 90.701 74.952 ;
     RECT  90.613 45.456 90.764 45.48 ;
     RECT  90.701 74.688 90.785 74.952 ;
     RECT  90.764 45.36 90.821 45.48 ;
     RECT  90.821 45.36 90.851 45.384 ;
     RECT  90.613 34.08 90.86 34.104 ;
     RECT  90.812 21.216 90.899 21.24 ;
     RECT  90.86 33.792 90.947 34.104 ;
     RECT  90.641 28.464 91.001 28.488 ;
     RECT  90.947 34.08 91.001 34.104 ;
     RECT  90.997 26.496 91.141 26.52 ;
     RECT  88.297 0.048 91.177 0.072 ;
     RECT  91.1 17.088 91.187 17.112 ;
     RECT  91.177 0.048 91.213 0.216 ;
     RECT  91.141 26.256 91.217 26.52 ;
     RECT  91.217 26.256 91.228 26.28 ;
     RECT  91.321 36.576 91.532 36.6 ;
     RECT  91.532 36.576 91.619 36.792 ;
     RECT  91.619 36.576 91.645 36.6 ;
     RECT  90.785 74.928 91.717 74.952 ;
     RECT  91.645 36.384 91.753 36.6 ;
     RECT  91.676 8.688 91.763 8.712 ;
     RECT  91.753 36.144 91.829 36.6 ;
     RECT  91.829 36.144 91.901 36.168 ;
     RECT  92.005 12.768 92.092 12.792 ;
     RECT  92.141 73.584 92.225 73.608 ;
     RECT  92.197 69.12 92.284 69.144 ;
     RECT  92.204 9.168 92.291 9.192 ;
     RECT  91.717 74.928 92.293 75 ;
     RECT  92.293 74.16 92.377 75 ;
     RECT  92.348 21.216 92.435 21.24 ;
     RECT  92.492 17.472 92.579 17.496 ;
     RECT  92.533 65.328 92.62 65.352 ;
     RECT  92.677 65.76 92.764 65.784 ;
     RECT  92.684 26.4 92.771 26.424 ;
     RECT  92.821 40.992 92.908 41.016 ;
     RECT  92.377 74.544 92.915 75 ;
     RECT  91.213 0.048 92.963 0.552 ;
     RECT  92.897 32.976 92.981 33 ;
     RECT  92.972 31.92 93.059 31.944 ;
     RECT  93.205 66.048 93.349 66.072 ;
     RECT  93.157 1.728 93.491 1.752 ;
     RECT  93.509 11.328 93.841 11.352 ;
     RECT  93.193 41.184 94.165 41.352 ;
     RECT  93.805 1.776 94.208 1.8 ;
     RECT  93.404 8.688 94.208 8.712 ;
     RECT  93.841 10.848 94.208 11.352 ;
     RECT  93.541 12.768 94.208 12.792 ;
     RECT  93.733 16.128 94.208 16.152 ;
     RECT  94.069 25.008 94.208 25.032 ;
     RECT  93.692 28.368 94.208 28.392 ;
     RECT  94.165 41.136 94.208 41.352 ;
     RECT  93.349 66.048 94.208 66.264 ;
     RECT  94.069 69.984 94.208 70.008 ;
     RECT  93.404 72.672 94.208 72.696 ;
     RECT  92.915 74.928 94.208 75 ;
     RECT  89.104 76.56 94.208 76.584 ;
     RECT  89.104 78.672 94.208 78.744 ;
     RECT  92.963 0.048 94.307 0.216 ;
     RECT  94.208 1.776 94.312 137.712 ;
     RECT  94.312 1.776 94.489 137.442 ;
     RECT  94.489 1.728 94.504 137.442 ;
     RECT  94.504 23.712 94.565 25.032 ;
     RECT  94.504 1.728 94.573 2.904 ;
     RECT  94.573 1.776 94.643 2.904 ;
     RECT  94.504 27.888 94.643 28.2 ;
     RECT  94.504 41.184 94.673 41.208 ;
     RECT  94.643 27.888 94.709 28.104 ;
     RECT  94.643 1.776 94.739 2.808 ;
     RECT  94.709 28.08 94.787 28.104 ;
     RECT  94.504 12.912 94.883 12.936 ;
     RECT  94.565 23.712 94.931 24.072 ;
     RECT  94.504 17.04 94.997 17.544 ;
     RECT  94.997 17.088 95.177 17.112 ;
     RECT  94.931 24.048 95.213 24.072 ;
     RECT  94.307 0.048 95.281 0.12 ;
     RECT  94.504 35.808 95.356 35.832 ;
     RECT  94.504 74.928 95.533 75 ;
     RECT  94.504 73.776 95.548 73.8 ;
     RECT  95.281 0.048 95.557 0.6 ;
     RECT  94.739 1.776 95.557 2.376 ;
     RECT  94.504 3.984 95.699 4.008 ;
     RECT  95.633 19.536 95.708 19.56 ;
     RECT  95.708 19.536 95.717 20.472 ;
     RECT  95.557 0.048 95.756 2.376 ;
     RECT  95.701 37.584 95.788 37.608 ;
     RECT  95.717 20.448 95.795 20.472 ;
     RECT  95.756 0.048 95.929 2.856 ;
     RECT  95.929 0.048 96.083 3.528 ;
     RECT  96.083 1.152 96.293 3.528 ;
     RECT  96.293 1.728 96.337 2.904 ;
     RECT  95.533 74.928 96.361 75.48 ;
     RECT  96.361 74.064 96.689 75.48 ;
     RECT  95.749 31.872 96.821 31.896 ;
     RECT  96.805 8.736 96.892 8.76 ;
     RECT  96.821 31.776 96.901 31.896 ;
     RECT  96.901 31.776 96.905 31.992 ;
     RECT  97.052 27.792 97.139 27.816 ;
     RECT  96.905 31.968 97.157 31.992 ;
     RECT  97.1 41.52 97.187 41.544 ;
     RECT  97.148 16.176 97.235 16.2 ;
     RECT  96.337 1.728 97.381 2.376 ;
     RECT  97.381 35.28 97.468 35.304 ;
     RECT  97.381 1.152 97.475 2.376 ;
     RECT  96.083 0.048 97.523 0.168 ;
     RECT  97.436 32.112 97.523 32.136 ;
     RECT  97.475 1.152 97.763 1.848 ;
     RECT  97.717 9.984 97.804 10.008 ;
     RECT  97.763 1.152 97.841 1.176 ;
     RECT  97.957 23.856 98.044 23.88 ;
     RECT  96.689 74.928 98.06 75.48 ;
     RECT  97.523 0.048 98.147 0.072 ;
     RECT  98.06 74.544 98.147 75.48 ;
     RECT  98.053 27.984 98.381 28.008 ;
     RECT  98.053 70.848 98.453 70.872 ;
     RECT  98.053 7.92 98.581 7.944 ;
     RECT  98.197 23.376 98.597 23.4 ;
     RECT  98.581 7.92 98.627 8.04 ;
     RECT  98.521 13.2 98.627 13.224 ;
     RECT  98.677 49.968 98.917 49.992 ;
     RECT  98.629 73.776 99.493 73.8 ;
     RECT  98.147 74.928 99.493 75.48 ;
     RECT  98.627 8.016 99.608 8.04 ;
     RECT  98.773 12.48 99.608 12.504 ;
     RECT  98.725 16.224 99.608 16.248 ;
     RECT  98.629 37.584 99.608 37.608 ;
     RECT  98.917 49.968 99.608 50.328 ;
     RECT  99.493 73.776 99.608 75.48 ;
     RECT  94.504 76.56 99.608 76.584 ;
     RECT  94.504 78.672 99.608 78.744 ;
     RECT  99.608 2.148 99.712 137.712 ;
     RECT  99.712 2.418 99.904 137.442 ;
     RECT  99.904 69.6 100.289 69.864 ;
     RECT  100.289 69.84 100.361 69.864 ;
     RECT  101.461 73.488 102.017 73.512 ;
     RECT  103.777 69.6 105.008 69.624 ;
     RECT  99.904 74.928 105.008 75.48 ;
     RECT  99.904 76.56 105.008 76.584 ;
     RECT  99.904 78.672 105.008 78.744 ;
     RECT  105.008 2.148 105.112 137.712 ;
     RECT  105.112 2.418 105.304 137.442 ;
     RECT  105.304 67.68 105.724 67.704 ;
     RECT  107.917 68.64 108.323 68.664 ;
     RECT  105.304 74.928 109.033 75.48 ;
     RECT  105.304 76.56 109.033 76.584 ;
     RECT  109.033 74.928 110.408 76.584 ;
     RECT  105.304 78.672 110.408 78.744 ;
     RECT  110.408 2.148 110.512 137.712 ;
     RECT  110.512 2.418 110.704 137.442 ;
     RECT  113.137 71.472 113.317 71.496 ;
     RECT  113.317 71.328 113.411 71.496 ;
     RECT  113.411 71.472 113.609 71.496 ;
     RECT  115.141 68.208 115.808 68.232 ;
     RECT  110.704 74.928 115.808 76.584 ;
     RECT  110.704 78.672 115.808 78.744 ;
     RECT  115.808 2.148 115.912 137.712 ;
     RECT  115.912 2.418 116.104 137.442 ;
     RECT  116.104 74.688 118.681 76.584 ;
     RECT  118.604 72.288 118.691 72.312 ;
     RECT  119.42 68.304 119.507 68.328 ;
     RECT  118.681 74.64 119.989 76.584 ;
     RECT  119.948 66.912 120.035 66.936 ;
     RECT  119.989 74.64 120.076 77.544 ;
     RECT  120.044 72.912 120.131 72.936 ;
     RECT  120.076 74.64 121.208 76.584 ;
     RECT  116.104 78.672 121.208 78.792 ;
     RECT  121.208 2.148 121.312 137.712 ;
     RECT  121.312 2.418 121.504 137.442 ;
     RECT  122.725 68.88 122.78 68.904 ;
     RECT  122.78 68.88 122.867 69.144 ;
     RECT  122.785 81.6 123.107 81.624 ;
     RECT  121.504 78.672 123.253 78.792 ;
     RECT  123.153 66.96 123.299 66.984 ;
     RECT  123.071 73.2 123.653 73.224 ;
     RECT  123.253 78.624 123.683 78.792 ;
     RECT  124.357 68.88 124.444 68.904 ;
     RECT  121.504 74.64 124.765 76.584 ;
     RECT  124.765 74.64 124.837 77.112 ;
     RECT  124.765 66.048 124.849 66.072 ;
     RECT  124.837 74.64 125.273 77.304 ;
     RECT  124.981 81.6 125.417 81.624 ;
     RECT  125.273 74.64 125.525 77.112 ;
     RECT  125.989 68.352 126.14 68.376 ;
     RECT  126.14 68.256 126.608 68.376 ;
     RECT  125.525 74.64 126.608 76.584 ;
     RECT  123.683 78.672 126.608 78.792 ;
     RECT  125.917 82.08 126.608 82.104 ;
     RECT  126.608 2.148 126.712 137.712 ;
     RECT  126.712 2.418 126.904 137.442 ;
     RECT  126.904 73.488 127.228 73.512 ;
     RECT  126.904 70.416 127.283 70.44 ;
     RECT  126.904 66.912 127.475 66.936 ;
     RECT  126.904 79.824 128.243 79.848 ;
     RECT  126.904 74.64 128.365 76.584 ;
     RECT  128.588 70.512 128.675 70.536 ;
     RECT  128.617 66.672 128.729 66.696 ;
     RECT  128.365 74.64 128.819 76.872 ;
     RECT  128.533 81.84 128.837 81.864 ;
     RECT  128.869 66.048 129.107 66.072 ;
     RECT  126.904 78.672 129.973 78.792 ;
     RECT  129.973 78.672 130.412 79.704 ;
     RECT  130.412 78.048 130.421 79.704 ;
     RECT  130.421 78.048 130.499 78.792 ;
     RECT  130.499 78.672 131.852 78.792 ;
     RECT  131.653 67.296 132.008 67.32 ;
     RECT  131.893 70.8 132.008 70.824 ;
     RECT  128.819 74.64 132.008 76.584 ;
     RECT  131.852 78.672 132.008 79.704 ;
     RECT  132.008 2.148 132.112 137.712 ;
     RECT  132.112 2.418 132.304 137.442 ;
     RECT  132.304 77.712 132.941 78.792 ;
     RECT  132.304 66.096 132.995 66.12 ;
     RECT  132.304 74.64 134.533 76.584 ;
     RECT  132.941 78.672 134.588 78.792 ;
     RECT  134.588 78.672 134.675 79.08 ;
     RECT  134.636 66.432 134.723 66.456 ;
     RECT  134.677 82.704 134.777 82.728 ;
     RECT  134.533 73.776 135.065 76.584 ;
     RECT  135.068 81.216 135.155 81.24 ;
     RECT  135.164 68.832 135.251 68.856 ;
     RECT  135.253 71.328 135.389 71.352 ;
     RECT  135.097 66.288 135.425 66.312 ;
     RECT  135.065 74.64 137.408 76.584 ;
     RECT  134.675 78.672 137.408 78.792 ;
     RECT  137.408 2.148 137.512 137.712 ;
     RECT  137.512 2.418 137.704 137.442 ;
     RECT  137.704 74.64 139.932 78.888 ;
    LAYER M5 ;
     RECT  94.56 0.047 94.584 0.053 ;
     RECT  96.576 0.047 96.6 0.053 ;
     RECT  98.112 0.037 98.136 0.053 ;
     RECT  96.048 0.053 98.136 0.121 ;
     RECT  94.128 0.053 94.584 0.131 ;
     RECT  96.048 0.121 97.512 0.131 ;
     RECT  94.128 0.131 94.296 0.179 ;
     RECT  97.392 0.131 97.512 0.179 ;
     RECT  94.272 0.179 94.296 0.227 ;
     RECT  96.048 0.131 96.072 0.565 ;
     RECT  92.928 0.501 92.952 0.589 ;
     RECT  95.568 0.565 96.072 1.141 ;
     RECT  97.392 0.179 97.416 1.141 ;
     RECT  94.512 1.141 94.536 1.589 ;
     RECT  95.568 1.141 97.416 1.589 ;
     RECT  93.456 1.141 93.48 1.717 ;
     RECT  94.512 1.589 97.416 1.717 ;
     RECT  93.456 1.717 97.752 1.763 ;
     RECT  93.888 1.763 97.752 1.811 ;
     RECT  94.2 1.811 97.752 1.859 ;
     RECT  95.808 1.859 97.464 2.317 ;
     RECT  97.44 2.317 97.464 2.387 ;
     RECT  2.4 2.137 2.52 2.407 ;
     RECT  7.8 2.137 7.92 2.407 ;
     RECT  13.2 2.137 13.32 2.407 ;
     RECT  18.6 2.137 18.72 2.407 ;
     RECT  24 2.137 24.12 2.407 ;
     RECT  29.4 2.137 29.52 2.407 ;
     RECT  34.8 2.137 34.92 2.407 ;
     RECT  40.2 2.137 40.32 2.407 ;
     RECT  45.6 2.137 45.72 2.407 ;
     RECT  51 2.137 51.12 2.407 ;
     RECT  56.4 2.137 56.52 2.407 ;
     RECT  61.8 2.137 61.92 2.407 ;
     RECT  67.2 2.137 67.32 2.407 ;
     RECT  72.6 2.137 72.72 2.407 ;
     RECT  78 2.137 78.12 2.407 ;
     RECT  83.4 2.137 83.52 2.407 ;
     RECT  88.8 2.137 88.92 2.407 ;
     RECT  99.6 2.137 99.72 2.407 ;
     RECT  105 2.137 105.12 2.407 ;
     RECT  110.4 2.137 110.52 2.407 ;
     RECT  115.8 2.137 115.92 2.407 ;
     RECT  121.2 2.137 121.32 2.407 ;
     RECT  126.6 2.137 126.72 2.407 ;
     RECT  132 2.137 132.12 2.407 ;
     RECT  137.4 2.137 137.52 2.407 ;
     RECT  94.2 1.859 94.728 2.819 ;
     RECT  94.2 2.819 94.632 2.915 ;
     RECT  95.808 2.317 96.312 2.915 ;
     RECT  95.808 2.915 96.264 3.445 ;
     RECT  95.664 3.445 96.264 3.539 ;
     RECT  95.664 3.539 95.688 4.019 ;
     RECT  98.064 7.909 98.616 8.051 ;
     RECT  94.2 2.915 94.512 8.659 ;
     RECT  91.728 8.659 91.752 8.693 ;
     RECT  91.728 8.693 92.28 8.747 ;
     RECT  93.456 8.659 94.512 8.747 ;
     RECT  98.064 8.051 98.088 8.747 ;
     RECT  96.816 8.693 96.84 8.781 ;
     RECT  92.256 8.747 92.28 9.203 ;
     RECT  97.728 9.909 97.752 10.019 ;
     RECT  94.2 8.747 94.512 10.805 ;
     RECT  93.888 10.805 94.512 11.317 ;
     RECT  93.552 11.317 94.512 11.401 ;
     RECT  88.8 2.407 89.112 11.859 ;
     RECT  88.128 11.859 89.112 11.893 ;
     RECT  88.128 11.893 89.304 11.947 ;
     RECT  99.6 2.407 99.912 12.469 ;
     RECT  98.784 12.469 99.912 12.553 ;
     RECT  94.2 11.401 94.512 12.757 ;
     RECT  88.8 11.947 89.304 12.843 ;
     RECT  92.016 12.757 92.04 12.843 ;
     RECT  93.552 12.757 94.512 12.843 ;
     RECT  94.2 12.843 94.512 12.883 ;
     RECT  94.2 12.883 94.872 12.971 ;
     RECT  98.592 13.151 98.616 13.235 ;
     RECT  88.8 12.843 89.112 14.325 ;
     RECT  88.032 14.325 89.208 14.413 ;
     RECT  88.8 14.413 89.208 14.435 ;
     RECT  94.2 12.971 94.512 16.117 ;
     RECT  99.6 12.553 99.912 16.181 ;
     RECT  94.032 16.117 94.512 16.201 ;
     RECT  97.2 16.147 97.224 16.235 ;
     RECT  98.736 16.181 99.912 16.269 ;
     RECT  94.2 16.201 94.512 16.991 ;
     RECT  88.8 14.435 89.112 17.077 ;
     RECT  94.2 16.991 94.68 17.077 ;
     RECT  94.2 17.077 95.16 17.161 ;
     RECT  88.704 17.077 89.112 17.171 ;
     RECT  91.152 17.047 91.176 17.579 ;
     RECT  92.544 17.461 92.568 17.579 ;
     RECT  94.2 17.161 94.68 17.593 ;
     RECT  87.072 17.589 87.096 17.677 ;
     RECT  95.664 19.487 95.688 19.571 ;
     RECT  95.76 20.437 95.784 20.523 ;
     RECT  90.864 21.173 90.888 21.261 ;
     RECT  92.4 21.173 92.424 21.261 ;
     RECT  94.2 17.593 94.512 23.701 ;
     RECT  94.2 23.701 94.92 23.915 ;
     RECT  97.968 23.827 97.992 23.915 ;
     RECT  86.688 23.989 86.712 24.563 ;
     RECT  94.2 23.915 94.512 24.997 ;
     RECT  90.528 24.901 90.552 25.067 ;
     RECT  86.976 24.997 87 25.081 ;
     RECT  94.08 24.997 94.512 25.081 ;
     RECT  91.152 26.229 91.176 26.317 ;
     RECT  91.104 26.357 91.128 26.421 ;
     RECT  92.736 26.357 92.76 26.445 ;
     RECT  91.008 26.421 91.128 26.531 ;
     RECT  86.208 27.381 86.232 27.875 ;
     RECT  97.104 27.781 97.128 27.935 ;
     RECT  94.2 25.081 94.512 27.957 ;
     RECT  97.104 27.935 98.088 28.011 ;
     RECT  98.064 28.011 98.088 28.019 ;
     RECT  90.576 28.021 90.6 28.115 ;
     RECT  94.2 27.957 94.776 28.115 ;
     RECT  94.2 28.115 94.632 28.149 ;
     RECT  93.744 28.149 94.632 28.237 ;
     RECT  93.744 28.237 94.512 28.403 ;
     RECT  96.864 31.727 96.888 31.811 ;
     RECT  95.76 31.861 95.784 31.945 ;
     RECT  93.024 31.891 93.048 31.979 ;
     RECT  96.912 31.919 96.936 32.003 ;
     RECT  97.488 32.083 97.512 32.171 ;
     RECT  88.8 17.171 89.112 32.979 ;
     RECT  92.928 32.927 92.952 33.011 ;
     RECT  88.224 32.979 89.112 33.067 ;
     RECT  90.912 33.747 90.936 33.835 ;
     RECT  90.624 34.069 90.648 34.155 ;
     RECT  94.2 28.403 94.512 35.797 ;
     RECT  94.2 35.797 95.304 35.883 ;
     RECT  97.392 34.805 97.416 35.883 ;
     RECT  87.264 36.149 87.624 36.237 ;
     RECT  91.584 36.757 91.608 36.843 ;
     RECT  87.6 36.237 87.624 37.283 ;
     RECT  99.6 16.269 99.912 37.535 ;
     RECT  98.64 37.535 99.912 37.619 ;
     RECT  95.712 36.789 95.736 37.645 ;
     RECT  88.8 33.067 89.112 41.043 ;
     RECT  88.08 41.043 89.112 41.077 ;
     RECT  88.08 41.077 90.072 41.131 ;
     RECT  92.832 40.981 92.856 41.131 ;
     RECT  88.8 41.131 90.072 41.161 ;
     RECT  86.592 41.173 86.616 41.259 ;
     RECT  94.2 35.883 94.512 41.317 ;
     RECT  93.456 41.317 94.512 41.401 ;
     RECT  97.152 41.333 97.176 41.579 ;
     RECT  84.864 42.671 84.888 42.755 ;
     RECT  85.104 42.963 85.128 43.051 ;
     RECT  85.488 44.789 85.512 44.821 ;
     RECT  85.488 44.821 85.992 44.877 ;
     RECT  85.968 44.877 85.992 44.907 ;
     RECT  90.624 45.045 90.648 45.301 ;
     RECT  90.624 45.301 90.84 45.395 ;
     RECT  90.624 45.395 90.648 45.491 ;
     RECT  84.816 46.483 84.84 46.571 ;
     RECT  51 2.407 51.312 46.611 ;
     RECT  50.736 46.611 51.312 46.699 ;
     RECT  85.2 46.773 85.224 46.861 ;
     RECT  45.6 2.407 45.912 47.471 ;
     RECT  47.328 47.349 47.352 47.531 ;
     RECT  45.504 47.471 45.912 47.555 ;
     RECT  55.296 47.519 55.32 47.603 ;
     RECT  29.4 2.407 29.712 47.797 ;
     RECT  27.792 47.221 27.816 47.851 ;
     RECT  29.4 47.797 30.84 47.891 ;
     RECT  52.752 47.349 52.776 48.419 ;
     RECT  25.728 47.797 25.752 48.659 ;
     RECT  18.6 2.407 18.912 48.661 ;
     RECT  24 2.407 24.312 48.671 ;
     RECT  18.384 48.661 18.912 48.747 ;
     RECT  21.168 48.661 21.192 48.747 ;
     RECT  23.904 48.671 24.312 48.755 ;
     RECT  24 48.755 24.312 48.915 ;
     RECT  24 48.915 24.408 49.003 ;
     RECT  58.944 49.363 58.968 49.451 ;
     RECT  11.904 49.583 11.928 49.667 ;
     RECT  99.6 37.619 99.912 49.957 ;
     RECT  55.344 49.909 55.368 49.967 ;
     RECT  54.768 49.967 55.368 50.003 ;
     RECT  83.4 2.407 83.712 50.037 ;
     RECT  98.688 49.957 99.912 50.041 ;
     RECT  54.768 50.003 54.792 50.051 ;
     RECT  83.4 50.037 84.552 50.125 ;
     RECT  70.944 50.067 70.968 50.155 ;
     RECT  69.36 50.101 69.384 50.185 ;
     RECT  83.4 50.125 84.36 50.243 ;
     RECT  99.024 50.041 99.912 50.377 ;
     RECT  26.064 50.389 26.088 50.475 ;
     RECT  54.096 50.735 54.12 50.819 ;
     RECT  29.4 47.891 29.712 50.869 ;
     RECT  28.512 50.869 29.712 50.963 ;
     RECT  16.176 50.975 16.2 51.059 ;
     RECT  49.008 50.975 49.032 51.059 ;
     RECT  59.424 50.997 59.448 51.085 ;
     RECT  9.648 51.493 9.672 52.203 ;
     RECT  11.568 52.149 11.592 52.237 ;
     RECT  56.4 2.407 56.712 52.435 ;
     RECT  55.632 52.435 56.712 52.523 ;
     RECT  61.8 2.407 62.112 52.549 ;
     RECT  61.68 52.549 62.112 52.651 ;
     RECT  13.2 2.407 13.512 52.917 ;
     RECT  13.2 52.917 14.184 52.933 ;
     RECT  13.2 52.933 14.28 53.035 ;
     RECT  45.6 47.555 45.912 53.461 ;
     RECT  45.504 53.461 45.912 53.547 ;
     RECT  58.512 53.701 58.536 54.083 ;
     RECT  49.488 54.005 49.512 54.187 ;
     RECT  18.6 48.747 18.912 54.325 ;
     RECT  56.4 52.523 56.712 54.389 ;
     RECT  17.616 54.325 18.912 54.453 ;
     RECT  17.376 54.453 18.912 54.467 ;
     RECT  56.304 54.389 56.712 54.477 ;
     RECT  17.376 54.467 17.4 54.563 ;
     RECT  20.544 54.613 20.568 54.699 ;
     RECT  60.384 54.709 60.408 54.803 ;
     RECT  7.8 2.407 8.112 55.237 ;
     RECT  13.2 53.035 13.512 55.285 ;
     RECT  13.056 55.285 13.512 55.379 ;
     RECT  5.568 55.237 5.592 55.381 ;
     RECT  5.568 55.381 6.408 55.467 ;
     RECT  51 46.699 51.312 55.477 ;
     RECT  50.736 55.477 51.312 55.561 ;
     RECT  7.8 55.237 8.904 55.851 ;
     RECT  45.6 53.547 45.912 56.341 ;
     RECT  45.6 56.341 46.776 56.373 ;
     RECT  10.272 55.797 10.296 56.427 ;
     RECT  45.024 56.373 46.776 56.427 ;
     RECT  45.024 56.427 45.912 56.483 ;
     RECT  49.008 56.373 49.032 57.109 ;
     RECT  49.008 57.109 49.56 57.155 ;
     RECT  49.056 57.155 49.56 57.323 ;
     RECT  13.2 55.379 13.512 57.503 ;
     RECT  13.104 57.503 13.512 57.587 ;
     RECT  56.4 54.477 56.712 57.589 ;
     RECT  56.4 57.589 57.048 57.673 ;
     RECT  61.8 52.651 62.112 57.829 ;
     RECT  61.536 57.829 62.112 57.913 ;
     RECT  20.256 58.485 20.28 58.501 ;
     RECT  20.16 58.501 20.28 58.573 ;
     RECT  20.16 58.573 20.184 58.603 ;
     RECT  51 55.561 51.312 58.741 ;
     RECT  51 58.741 51.96 58.835 ;
     RECT  48.816 58.933 48.84 59.017 ;
     RECT  51 58.835 51.312 59.029 ;
     RECT  50.304 59.029 51.312 59.115 ;
     RECT  7.8 55.851 8.112 59.221 ;
     RECT  18.6 54.467 18.912 59.445 ;
     RECT  18.6 59.445 19.032 59.533 ;
     RECT  5.088 59.509 5.112 59.603 ;
     RECT  45.6 56.483 45.912 59.749 ;
     RECT  85.824 59.667 85.848 59.755 ;
     RECT  7.8 59.221 8.232 59.765 ;
     RECT  10.224 59.231 10.248 59.785 ;
     RECT  45.6 59.749 46.728 59.833 ;
     RECT  7.8 59.765 8.808 59.853 ;
     RECT  13.2 57.587 13.512 60.181 ;
     RECT  48.912 60.243 48.936 60.331 ;
     RECT  13.2 60.181 14.28 60.395 ;
     RECT  21.12 60.383 21.144 60.467 ;
     RECT  56.4 57.673 56.712 60.575 ;
     RECT  55.824 60.575 56.712 60.659 ;
     RECT  59.28 60.575 59.304 60.659 ;
     RECT  0.048 48.421 0.072 61.669 ;
     RECT  0.048 61.669 0.168 61.715 ;
     RECT  6.048 61.557 6.072 61.813 ;
     RECT  7.8 59.853 8.112 61.813 ;
     RECT  13.2 60.395 13.512 61.813 ;
     RECT  6.048 61.813 6.264 61.867 ;
     RECT  6.24 61.867 6.264 61.897 ;
     RECT  15.984 61.813 16.008 61.907 ;
     RECT  7.8 61.813 9.096 62.195 ;
     RECT  13.2 61.813 14.328 62.195 ;
     RECT  0.144 61.715 0.168 62.291 ;
     RECT  51 59.115 51.312 62.341 ;
     RECT  56.4 60.659 56.712 62.581 ;
     RECT  55.584 62.581 56.712 62.709 ;
     RECT  51 62.341 51.528 62.763 ;
     RECT  55.584 62.709 57.624 62.763 ;
     RECT  11.328 62.709 11.352 62.797 ;
     RECT  46.992 62.709 47.016 62.797 ;
     RECT  56.4 62.763 57.624 62.797 ;
     RECT  59.28 62.725 59.304 63.275 ;
     RECT  22.176 63.205 22.2 63.289 ;
     RECT  19.968 63.455 19.992 63.539 ;
     RECT  83.4 50.243 83.712 63.669 ;
     RECT  83.4 63.669 83.832 63.779 ;
     RECT  57.84 63.221 57.864 63.851 ;
     RECT  6.048 63.839 6.072 63.923 ;
     RECT  24 49.003 24.312 64.021 ;
     RECT  24 64.021 24.552 64.053 ;
     RECT  23.136 64.053 24.552 64.107 ;
     RECT  23.136 64.107 24.408 64.355 ;
     RECT  51 62.763 51.312 64.821 ;
     RECT  47.28 64.799 47.304 64.883 ;
     RECT  50.4 64.821 51.312 64.909 ;
     RECT  50.688 64.909 51.312 64.939 ;
     RECT  24 64.355 24.408 65.003 ;
     RECT  13.2 62.195 13.512 65.077 ;
     RECT  13.2 65.077 14.232 65.171 ;
     RECT  92.544 65.299 92.568 65.387 ;
     RECT  10.8 65.375 10.824 65.459 ;
     RECT  83.4 63.779 83.712 65.589 ;
     RECT  51 64.939 51.312 65.683 ;
     RECT  83.4 65.589 84.696 65.699 ;
     RECT  51 65.683 51.864 65.771 ;
     RECT  56.4 62.797 56.712 65.845 ;
     RECT  56.4 65.845 57 65.939 ;
     RECT  92.688 65.749 92.712 66.003 ;
     RECT  94.2 41.401 94.512 66.003 ;
     RECT  132 2.407 132.312 66.067 ;
     RECT  124.8 66.037 124.824 66.121 ;
     RECT  129.072 66.037 129.096 66.121 ;
     RECT  51 65.771 51.528 66.155 ;
     RECT  132 66.067 132.984 66.155 ;
     RECT  88.8 41.161 89.112 66.195 ;
     RECT  92.688 66.003 94.512 66.219 ;
     RECT  88.032 66.195 89.112 66.229 ;
     RECT  93.36 66.219 94.512 66.275 ;
     RECT  88.032 66.229 89.256 66.277 ;
     RECT  87.216 66.277 89.256 66.357 ;
     RECT  87.216 66.357 89.352 66.361 ;
     RECT  55.296 65.893 55.32 66.411 ;
     RECT  87.744 66.361 89.352 66.411 ;
     RECT  134.688 66.101 134.712 66.467 ;
     RECT  88.32 66.411 89.352 66.603 ;
     RECT  56.4 65.939 56.712 66.901 ;
     RECT  126.6 2.407 126.912 66.901 ;
     RECT  123.264 66.933 123.288 66.949 ;
     RECT  56.4 66.901 57.624 66.987 ;
     RECT  88.32 66.603 89.112 66.987 ;
     RECT  126.6 66.901 127.464 66.987 ;
     RECT  123.168 66.949 123.288 67.021 ;
     RECT  120 66.901 120.024 67.051 ;
     RECT  123.168 67.021 123.192 67.051 ;
     RECT  132 66.155 132.312 67.125 ;
     RECT  15.984 67.125 16.008 67.283 ;
     RECT  131.664 67.125 132.312 67.331 ;
     RECT  7.8 62.195 8.112 67.669 ;
     RECT  105 2.407 105.312 67.669 ;
     RECT  7.8 67.669 8.616 68.139 ;
     RECT  53.904 67.765 53.928 68.139 ;
     RECT  105 67.669 105.672 68.139 ;
     RECT  115.8 2.407 116.112 68.149 ;
     RECT  126.6 66.987 126.912 68.213 ;
     RECT  115.152 68.149 116.112 68.331 ;
     RECT  126.192 68.213 126.912 68.341 ;
     RECT  119.472 68.277 119.496 68.365 ;
     RECT  123.6 68.213 123.624 68.395 ;
     RECT  60.432 68.341 60.456 68.425 ;
     RECT  126 68.341 126.912 68.425 ;
     RECT  13.2 65.171 13.512 68.533 ;
     RECT  12.288 68.533 13.512 68.627 ;
     RECT  6.24 68.639 6.264 68.661 ;
     RECT  7.8 68.139 8.112 68.661 ;
     RECT  108.288 68.629 108.312 68.715 ;
     RECT  6.24 68.661 8.112 68.723 ;
     RECT  12 68.639 12.024 68.723 ;
     RECT  13.056 68.627 13.512 68.819 ;
     RECT  122.832 68.853 122.856 68.869 ;
     RECT  135.216 68.821 135.24 68.907 ;
     RECT  124.368 68.853 124.392 68.941 ;
     RECT  122.736 68.869 122.856 68.971 ;
     RECT  92.208 69.045 92.232 69.155 ;
     RECT  122.832 68.971 122.856 69.155 ;
     RECT  24 65.003 24.312 69.365 ;
     RECT  23.856 69.365 24.312 69.453 ;
     RECT  99.6 50.377 99.912 69.551 ;
     RECT  105 68.139 105.312 69.551 ;
     RECT  99.6 69.551 100.008 69.635 ;
     RECT  104.256 69.551 105.312 69.635 ;
     RECT  29.4 50.963 29.712 69.829 ;
     RECT  29.28 69.829 29.712 69.931 ;
     RECT  94.2 66.275 94.512 69.941 ;
     RECT  94.08 69.941 94.512 70.029 ;
     RECT  13.2 68.819 13.512 70.197 ;
     RECT  6.864 68.723 8.112 70.224 ;
     RECT  26.256 70.117 26.28 70.261 ;
     RECT  13.2 70.197 13.608 70.285 ;
     RECT  6.432 70.227 6.456 70.315 ;
     RECT  26.256 70.261 26.808 70.355 ;
     RECT  126.6 68.425 126.912 70.405 ;
     RECT  132 67.331 132.312 70.517 ;
     RECT  86.4 70.133 86.424 70.547 ;
     RECT  24 69.453 24.312 70.549 ;
     RECT  56.4 66.987 56.712 70.559 ;
     RECT  26.256 70.355 26.52 70.571 ;
     RECT  126.6 70.405 127.272 70.571 ;
     RECT  128.64 70.483 128.664 70.571 ;
     RECT  23.664 70.549 24.312 70.635 ;
     RECT  26.256 70.571 26.28 70.635 ;
     RECT  56.4 70.559 57.576 70.643 ;
     RECT  7.8 70.224 8.112 70.709 ;
     RECT  54.624 70.751 54.648 70.773 ;
     RECT  58.128 70.703 58.152 70.787 ;
     RECT  131.904 70.517 132.312 70.835 ;
     RECT  98.064 70.837 98.088 70.921 ;
     RECT  7.8 70.709 8.616 71.027 ;
     RECT  34.8 2.407 35.112 71.029 ;
     RECT  32.544 70.773 32.568 71.083 ;
     RECT  83.4 65.699 83.712 71.093 ;
     RECT  83.4 71.093 84.12 71.181 ;
     RECT  54.624 70.773 54.744 71.279 ;
     RECT  34.224 71.029 35.112 71.315 ;
     RECT  53.856 71.279 54.744 71.315 ;
     RECT  13.2 70.285 13.512 71.349 ;
     RECT  53.856 71.315 53.88 71.363 ;
     RECT  113.376 71.279 113.4 71.363 ;
     RECT  135.264 71.279 135.288 71.363 ;
     RECT  15.984 71.327 16.008 71.411 ;
     RECT  13.2 71.349 13.608 71.437 ;
     RECT  83.4 71.181 83.976 71.851 ;
     RECT  56.4 70.643 56.712 71.893 ;
     RECT  83.4 71.851 83.88 71.915 ;
     RECT  79.776 71.845 79.8 71.929 ;
     RECT  55.536 71.893 56.712 71.979 ;
     RECT  90.528 72.277 90.552 72.363 ;
     RECT  29.4 69.931 29.712 72.565 ;
     RECT  45.6 59.833 45.912 72.565 ;
     RECT  94.2 70.029 94.512 72.565 ;
     RECT  118.656 72.277 118.68 72.619 ;
     RECT  45.6 72.565 46.104 72.649 ;
     RECT  93.456 72.565 94.512 72.707 ;
     RECT  27.744 72.565 27.768 72.755 ;
     RECT  120.096 72.565 120.12 72.947 ;
     RECT  123.12 72.565 123.144 73.189 ;
     RECT  123.12 73.189 123.432 73.235 ;
     RECT  51 66.155 51.312 73.333 ;
     RECT  7.8 71.027 8.112 73.477 ;
     RECT  18.6 59.533 18.912 73.477 ;
     RECT  126.6 70.571 126.912 73.477 ;
     RECT  24 70.635 24.312 73.491 ;
     RECT  23.04 73.491 24.312 73.525 ;
     RECT  99.6 69.635 99.912 73.525 ;
     RECT  18.6 73.477 19.416 73.579 ;
     RECT  23.04 73.525 24.6 73.579 ;
     RECT  101.472 73.477 101.496 73.579 ;
     RECT  123.408 73.235 123.432 73.579 ;
     RECT  126.6 73.477 127.176 73.579 ;
     RECT  92.16 73.525 92.184 73.619 ;
     RECT  29.28 72.565 29.712 73.643 ;
     RECT  47.28 73.333 47.304 73.643 ;
     RECT  51 73.333 51.864 73.643 ;
     RECT  42.72 73.573 42.744 73.657 ;
     RECT  94.2 72.707 94.512 73.747 ;
     RECT  98.64 73.525 99.912 73.781 ;
     RECT  23.376 73.579 24.6 73.811 ;
     RECT  7.008 73.477 8.112 73.835 ;
     RECT  10.272 73.747 10.296 73.835 ;
     RECT  94.2 73.747 95.496 73.835 ;
     RECT  134.544 73.765 134.568 73.849 ;
     RECT  98.112 73.781 99.912 73.872 ;
     RECT  16.32 73.939 16.344 74.027 ;
     RECT  51 73.643 51.432 74.099 ;
     RECT  26.208 73.589 26.232 74.155 ;
     RECT  5.664 74.101 5.688 74.195 ;
     RECT  27.36 74.101 27.384 74.195 ;
     RECT  92.304 74.101 92.328 74.195 ;
     RECT  92.88 74.485 92.904 74.579 ;
     RECT  98.112 73.872 98.136 74.579 ;
     RECT  124.272 74.677 124.296 74.805 ;
     RECT  124.272 74.805 124.824 74.835 ;
     RECT  123.936 74.835 124.824 74.893 ;
     RECT  86.688 74.869 86.712 74.917 ;
     RECT  90.72 74.293 90.744 74.923 ;
     RECT  123.936 74.893 123.96 74.923 ;
     RECT  86.688 74.917 86.808 74.963 ;
     RECT  86.784 74.963 86.808 75.001 ;
     RECT  132 70.835 132.312 75.013 ;
     RECT  13.2 71.437 13.512 75.091 ;
     RECT  9.84 74.677 9.864 75.119 ;
     RECT  13.104 75.091 13.512 75.179 ;
     RECT  9.84 75.119 10.248 75.203 ;
     RECT  9.84 75.203 9.864 75.243 ;
     RECT  48 74.965 48.024 75.243 ;
     RECT  49.2 74.677 49.224 75.243 ;
     RECT  128.688 75.317 128.712 75.405 ;
     RECT  131.136 75.013 132.312 75.435 ;
     RECT  134.544 75.359 134.568 75.443 ;
     RECT  34.8 71.315 35.112 75.493 ;
     RECT  34.8 75.493 35.256 75.627 ;
     RECT  13.2 75.179 13.512 76.213 ;
     RECT  118.944 76.179 118.968 76.267 ;
     RECT  13.2 76.213 14.232 76.297 ;
     RECT  84.96 76.213 84.984 76.297 ;
     RECT  123.12 76.213 123.144 76.297 ;
     RECT  24 73.811 24.312 76.309 ;
     RECT  13.2 76.297 13.512 76.341 ;
     RECT  24 76.309 24.504 76.395 ;
     RECT  18.6 73.579 18.912 76.405 ;
     RECT  12.672 76.341 13.512 76.429 ;
     RECT  18.48 76.405 18.912 76.587 ;
     RECT  83.4 71.915 83.712 76.627 ;
     RECT  83.4 76.627 84.12 76.715 ;
     RECT  128.784 76.837 128.808 76.921 ;
     RECT  124.848 77.231 124.872 77.315 ;
     RECT  40.2 2.407 40.512 77.461 ;
     RECT  24 76.395 24.312 77.557 ;
     RECT  120 77.493 120.024 77.581 ;
     RECT  23.904 77.557 24.312 77.641 ;
     RECT  132 75.435 132.312 77.701 ;
     RECT  4.224 77.461 4.248 77.779 ;
     RECT  7.8 73.835 8.112 77.779 ;
     RECT  132 77.701 132.888 77.803 ;
     RECT  4.224 77.779 5.208 77.867 ;
     RECT  7.8 77.779 8.232 77.867 ;
     RECT  9.744 77.779 9.768 77.867 ;
     RECT  29.4 73.643 29.712 77.941 ;
     RECT  51 74.099 51.312 77.941 ;
     RECT  29.28 77.941 29.712 78.059 ;
     RECT  50.592 77.941 51.312 78.059 ;
     RECT  130.464 78.005 130.488 78.093 ;
     RECT  16.512 78.005 16.536 78.131 ;
     RECT  47.904 78.005 47.928 78.131 ;
     RECT  33.408 78.005 33.432 78.371 ;
     RECT  123.648 78.005 123.672 78.659 ;
     RECT  44.544 78.867 44.568 78.954 ;
     RECT  37.008 78.517 37.032 79.019 ;
     RECT  44.496 78.954 44.568 79.029 ;
     RECT  45.6 72.649 45.912 79.029 ;
     RECT  44.496 79.029 45.912 79.139 ;
     RECT  134.64 79.045 134.664 79.147 ;
     RECT  29.4 78.059 29.712 79.189 ;
     RECT  9.216 79.157 9.24 79.245 ;
     RECT  29.28 79.189 29.712 79.467 ;
     RECT  25.968 79.413 25.992 79.501 ;
     RECT  132 77.803 132.312 79.605 ;
     RECT  129.984 79.669 130.008 79.753 ;
     RECT  39.792 77.461 40.512 79.775 ;
     RECT  131.904 79.605 132.312 79.851 ;
     RECT  39.456 79.775 40.512 79.859 ;
     RECT  128.208 79.775 128.232 79.859 ;
     RECT  13.2 76.429 13.512 79.925 ;
     RECT  43.584 79.861 43.608 79.955 ;
     RECT  13.2 79.925 13.608 80.013 ;
     RECT  21.072 80.351 21.096 80.435 ;
     RECT  18.6 76.587 18.912 80.735 ;
     RECT  17.664 80.735 18.912 80.819 ;
     RECT  47.088 80.927 47.832 81.011 ;
     RECT  135.12 81.171 135.144 81.259 ;
     RECT  5.76 81.269 5.784 81.301 ;
     RECT  7.8 77.867 8.112 81.311 ;
     RECT  3.936 80.917 3.96 81.323 ;
     RECT  5.76 81.301 6.264 81.357 ;
     RECT  6.24 81.357 6.264 81.387 ;
     RECT  7.8 81.311 8.568 81.395 ;
     RECT  124.992 81.555 125.016 81.643 ;
     RECT  123.072 81.589 123.096 81.673 ;
     RECT  126.6 73.579 126.912 81.909 ;
     RECT  128.544 81.781 128.568 81.963 ;
     RECT  36.48 81.973 36.504 82.057 ;
     RECT  31.296 82.021 31.32 82.079 ;
     RECT  125.952 81.909 126.912 82.115 ;
     RECT  13.2 80.013 13.512 82.131 ;
     RECT  31.056 82.079 31.32 82.163 ;
     RECT  85.104 82.079 85.128 82.163 ;
     RECT  32.832 82.101 32.856 82.189 ;
     RECT  13.2 82.131 13.656 82.219 ;
     RECT  29.4 79.467 29.712 82.357 ;
     RECT  31.296 82.163 31.32 82.411 ;
     RECT  29.4 82.357 30.072 82.451 ;
     RECT  134.688 82.655 134.712 82.739 ;
     RECT  24 77.641 24.312 83.231 ;
     RECT  34.8 75.627 35.112 83.231 ;
     RECT  24 83.231 25.128 83.315 ;
     RECT  34.8 83.231 35.256 83.315 ;
     RECT  40.2 79.859 40.512 83.381 ;
     RECT  39.552 83.381 40.512 83.469 ;
     RECT  13.2 82.219 13.512 84.341 ;
     RECT  15.408 84.335 15.432 84.419 ;
     RECT  7.8 81.395 8.112 84.469 ;
     RECT  12.576 84.341 13.512 84.523 ;
     RECT  7.8 84.469 8.616 84.553 ;
     RECT  7.8 84.553 8.52 84.601 ;
     RECT  7.8 84.601 8.328 84.709 ;
     RECT  20.16 84.691 20.184 84.779 ;
     RECT  4.032 84.805 4.056 84.907 ;
     RECT  7.152 84.709 8.328 84.907 ;
     RECT  22.704 85.173 22.728 85.261 ;
     RECT  29.4 82.451 29.712 86.005 ;
     RECT  14.88 85.909 14.904 86.059 ;
     RECT  29.28 86.005 29.712 86.089 ;
     RECT  7.8 84.907 8.112 86.133 ;
     RECT  7.584 86.133 8.112 86.443 ;
     RECT  37.584 87.157 37.608 87.241 ;
     RECT  31.632 87.157 31.656 87.251 ;
     RECT  38.928 87.157 38.952 87.299 ;
     RECT  11.952 87.507 11.976 87.595 ;
     RECT  24 83.315 24.312 88.723 ;
     RECT  7.8 86.443 8.112 88.757 ;
     RECT  23.376 88.723 24.312 88.811 ;
     RECT  17.088 88.757 17.112 88.979 ;
     RECT  19.92 88.757 19.944 88.979 ;
     RECT  7.632 88.757 8.112 89.027 ;
     RECT  25.68 89.701 25.704 89.785 ;
     RECT  6.528 89.845 6.552 89.909 ;
     RECT  4.512 89.893 4.536 89.977 ;
     RECT  6.432 89.909 6.552 89.987 ;
     RECT  6.432 89.987 6.456 89.997 ;
     RECT  3.936 90.229 3.96 90.313 ;
     RECT  18.6 80.819 18.912 91.125 ;
     RECT  83.4 76.715 83.712 91.189 ;
     RECT  18.096 91.125 18.912 91.213 ;
     RECT  11.76 91.189 11.784 91.283 ;
     RECT  83.4 91.189 84.408 91.717 ;
     RECT  13.2 84.523 13.512 92.597 ;
     RECT  13.2 92.597 13.8 92.629 ;
     RECT  13.2 92.629 14.232 92.715 ;
     RECT  16.848 92.661 16.872 92.749 ;
     RECT  2.4 2.407 2.712 137.453 ;
     RECT  7.8 89.027 8.112 137.453 ;
     RECT  13.2 92.715 13.512 137.453 ;
     RECT  18.6 91.213 18.912 137.453 ;
     RECT  24 88.811 24.312 137.453 ;
     RECT  29.4 86.089 29.712 137.453 ;
     RECT  34.8 83.315 35.112 137.453 ;
     RECT  40.2 83.469 40.512 137.453 ;
     RECT  45.6 79.139 45.912 137.453 ;
     RECT  51 78.059 51.312 137.453 ;
     RECT  56.4 71.979 56.712 137.453 ;
     RECT  61.8 57.913 62.112 137.453 ;
     RECT  67.2 2.407 67.512 137.453 ;
     RECT  72.6 2.407 72.912 137.453 ;
     RECT  78 2.407 78.312 137.453 ;
     RECT  83.4 91.717 84.648 137.453 ;
     RECT  88.8 66.987 89.112 137.453 ;
     RECT  94.2 73.835 94.512 137.453 ;
     RECT  99.6 73.872 99.912 137.453 ;
     RECT  105 69.635 105.312 137.453 ;
     RECT  110.4 2.407 110.712 137.453 ;
     RECT  115.8 68.331 116.112 137.453 ;
     RECT  121.2 2.407 121.512 137.453 ;
     RECT  126.6 82.115 126.912 137.453 ;
     RECT  132 79.851 132.312 137.453 ;
     RECT  137.4 2.407 137.712 137.453 ;
     RECT  2.4 137.453 2.52 137.723 ;
     RECT  7.8 137.453 7.92 137.723 ;
     RECT  13.2 137.453 13.32 137.723 ;
     RECT  18.6 137.453 18.72 137.723 ;
     RECT  24 137.453 24.12 137.723 ;
     RECT  29.4 137.453 29.52 137.723 ;
     RECT  34.8 137.453 34.92 137.723 ;
     RECT  40.2 137.453 40.32 137.723 ;
     RECT  45.6 137.453 45.72 137.723 ;
     RECT  51 137.453 51.12 137.723 ;
     RECT  56.4 137.453 56.52 137.723 ;
     RECT  61.8 137.453 61.92 137.723 ;
     RECT  67.2 137.453 67.32 137.723 ;
     RECT  72.6 137.453 72.72 137.723 ;
     RECT  78 137.453 78.12 137.723 ;
     RECT  83.4 137.453 83.52 137.723 ;
     RECT  88.8 137.453 88.92 137.723 ;
     RECT  94.2 137.453 94.32 137.723 ;
     RECT  99.6 137.453 99.72 137.723 ;
     RECT  105 137.453 105.12 137.723 ;
     RECT  110.4 137.453 110.52 137.723 ;
     RECT  115.8 137.453 115.92 137.723 ;
     RECT  121.2 137.453 121.32 137.723 ;
     RECT  126.6 137.453 126.72 137.723 ;
     RECT  132 137.453 132.12 137.723 ;
     RECT  137.4 137.453 137.52 137.723 ;
     RECT  84.624 137.453 84.648 139.093 ;
     RECT  84.528 139.093 84.648 139.765 ;
     RECT  84.144 139.765 84.648 139.947 ;
     RECT  84.24 139.947 84.648 139.984 ;
    LAYER M6 ;
     RECT  2.16 88.929 3.925 89.601 ;
     RECT  2.16 83.529 4.021 84.201 ;
     RECT  2.16 78.129 4.213 78.801 ;
     RECT  2.16 56.529 5.557 57.201 ;
     RECT  2.16 72.729 5.653 73.401 ;
     RECT  3.925 81.28 5.795 81.312 ;
     RECT  2.16 61.929 6.005 62.601 ;
     RECT  6.005 61.568 6.037 62.601 ;
     RECT  6.037 61.568 6.083 63.904 ;
     RECT  6.083 61.824 6.123 63.904 ;
     RECT  2.16 67.329 6.229 68.001 ;
     RECT  4.213 77.824 6.453 78.801 ;
     RECT  6.421 70.272 6.507 70.304 ;
     RECT  6.229 67.329 6.899 68.704 ;
     RECT  5.653 72.729 7.019 74.144 ;
     RECT  4.021 83.529 7.573 84.896 ;
     RECT  3.925 88.929 7.605 90.272 ;
     RECT  7.573 83.529 7.659 86.432 ;
     RECT  7.605 88.768 7.678 90.272 ;
     RECT  7.659 83.529 7.723 86.176 ;
     RECT  5.077 59.52 8.243 59.552 ;
     RECT  7.723 83.529 8.339 84.896 ;
     RECT  6.853 70.144 8.558 70.176 ;
     RECT  6.899 67.329 8.565 68.001 ;
     RECT  6.229 81.344 8.579 81.376 ;
     RECT  8.558 70.144 8.619 70.752 ;
     RECT  8.619 70.72 8.627 70.752 ;
     RECT  8.773 59.776 8.875 59.808 ;
     RECT  5.557 55.424 8.915 57.201 ;
     RECT  6.123 61.824 9.107 62.601 ;
     RECT  2.16 51.129 9.637 51.801 ;
     RECT  7.019 72.729 9.829 73.824 ;
     RECT  9.781 75.2 9.829 75.232 ;
     RECT  6.453 77.824 9.835 79.2 ;
     RECT  9.829 72.729 9.875 75.232 ;
     RECT  9.875 72.729 9.899 75.168 ;
     RECT  8.915 55.808 10.293 57.201 ;
     RECT  10.213 59.264 10.293 59.744 ;
     RECT  10.293 55.808 10.307 57.568 ;
     RECT  9.899 72.729 10.307 73.824 ;
     RECT  10.293 59.264 10.347 60.064 ;
     RECT  10.307 56.384 10.795 57.568 ;
     RECT  10.347 59.712 11.317 60.064 ;
     RECT  9.107 61.929 11.317 62.601 ;
     RECT  11.317 61.929 11.386 62.752 ;
     RECT  7.678 88.929 11.749 90.272 ;
     RECT  11.749 88.929 11.819 91.232 ;
     RECT  11.893 48.704 11.962 49.632 ;
     RECT  11.317 59.712 12.331 60.384 ;
     RECT  8.339 83.529 12.597 84.576 ;
     RECT  9.899 75.136 12.642 75.168 ;
     RECT  12.277 70.144 12.661 70.176 ;
     RECT  12.661 70.144 12.715 70.56 ;
     RECT  12.642 75.136 12.715 76.384 ;
     RECT  11.765 87.552 12.789 87.584 ;
     RECT  11.819 88.929 12.789 89.601 ;
     RECT  12.597 83.529 12.843 84.768 ;
     RECT  9.637 51.129 13.045 52.192 ;
     RECT  10.795 56.529 13.045 57.568 ;
     RECT  8.565 67.329 13.045 68.704 ;
     RECT  13.045 55.296 13.114 57.568 ;
     RECT  13.114 56.529 13.139 57.568 ;
     RECT  12.715 75.136 13.139 75.168 ;
     RECT  12.715 70.208 13.573 70.56 ;
     RECT  9.835 78.129 13.573 79.2 ;
     RECT  13.045 67.329 13.621 68.768 ;
     RECT  13.621 67.136 13.675 68.768 ;
     RECT  13.573 70.208 13.675 71.392 ;
     RECT  13.573 78.129 13.675 79.968 ;
     RECT  11.765 92.608 13.811 92.64 ;
     RECT  10.789 65.408 14.178 65.44 ;
     RECT  11.386 61.929 14.197 62.601 ;
     RECT  13.045 51.129 14.245 52.96 ;
     RECT  14.178 65.088 14.251 65.44 ;
     RECT  14.197 61.929 14.261 63.52 ;
     RECT  12.331 60.352 14.315 60.384 ;
     RECT  13.621 82.176 14.315 82.208 ;
     RECT  12.789 87.552 14.891 89.601 ;
     RECT  14.837 86.016 14.915 86.048 ;
     RECT  12.843 83.529 15.443 84.384 ;
     RECT  14.261 61.824 16.019 63.52 ;
     RECT  13.675 67.136 16.019 68.001 ;
     RECT  13.675 70.528 16.019 71.392 ;
     RECT  14.245 51.129 16.117 53.024 ;
     RECT  16.117 51.008 16.171 53.024 ;
     RECT  16.171 51.008 16.211 51.801 ;
     RECT  10.307 72.729 16.29 73.401 ;
     RECT  16.29 72.729 16.363 74.016 ;
     RECT  14.197 76.224 16.501 76.256 ;
     RECT  13.675 78.129 16.501 78.944 ;
     RECT  16.501 76.224 16.555 76.576 ;
     RECT  16.501 78.016 16.57 78.944 ;
     RECT  14.891 88.768 17.123 89.601 ;
     RECT  16.117 54.464 17.411 54.496 ;
     RECT  14.261 80.768 17.699 80.8 ;
     RECT  14.197 92.672 18.091 92.704 ;
     RECT  18.037 91.136 18.131 91.168 ;
     RECT  16.555 76.544 18.469 76.576 ;
     RECT  18.469 76.416 18.515 76.576 ;
     RECT  16.363 72.729 19.381 73.401 ;
     RECT  19.381 72.729 19.45 73.568 ;
     RECT  18.515 76.416 19.829 76.448 ;
     RECT  16.57 78.129 19.829 78.944 ;
     RECT  19.829 76.416 19.883 78.944 ;
     RECT  17.123 88.929 19.909 89.601 ;
     RECT  16.019 61.929 20.003 63.52 ;
     RECT  18.997 59.456 20.149 59.488 ;
     RECT  15.443 83.529 20.149 84.201 ;
     RECT  20.149 58.56 20.213 59.488 ;
     RECT  20.213 58.56 20.245 60.448 ;
     RECT  17.605 54.336 20.277 54.432 ;
     RECT  20.245 58.496 20.331 60.448 ;
     RECT  20.149 83.529 20.469 84.768 ;
     RECT  21.038 80.384 21.107 80.416 ;
     RECT  20.331 60.416 21.155 60.448 ;
     RECT  20.003 61.929 22.165 62.601 ;
     RECT  22.165 61.929 22.197 63.264 ;
     RECT  22.197 61.929 22.251 64.096 ;
     RECT  20.469 83.529 22.739 85.216 ;
     RECT  19.45 72.729 23.029 73.401 ;
     RECT  23.029 72.729 23.365 73.568 ;
     RECT  19.909 88.768 23.413 89.601 ;
     RECT  23.413 88.768 23.467 89.76 ;
     RECT  16.019 70.528 23.653 70.56 ;
     RECT  23.365 72.729 23.723 73.76 ;
     RECT  23.653 70.528 23.845 70.624 ;
     RECT  23.845 69.376 23.915 70.624 ;
     RECT  20.277 54.336 23.925 54.688 ;
     RECT  11.962 48.704 23.939 48.736 ;
     RECT  19.883 77.568 23.939 78.944 ;
     RECT  22.251 64.064 24.309 64.096 ;
     RECT  24.181 48.96 24.419 48.992 ;
     RECT  24.309 64.064 24.419 64.992 ;
     RECT  24.437 76.352 24.515 76.384 ;
     RECT  24.419 64.064 24.563 64.096 ;
     RECT  23.723 72.729 24.611 73.568 ;
     RECT  22.739 83.529 25.07 84.201 ;
     RECT  23.939 78.129 25.077 78.944 ;
     RECT  25.07 83.264 25.139 84.201 ;
     RECT  23.467 88.929 25.715 89.76 ;
     RECT  16.211 51.129 25.909 51.801 ;
     RECT  23.925 54.144 25.963 54.688 ;
     RECT  25.909 50.432 26.099 51.801 ;
     RECT  24.611 72.729 26.197 73.401 ;
     RECT  23.915 70.528 26.245 70.624 ;
     RECT  26.245 70.272 26.291 70.624 ;
     RECT  26.197 72.729 27.395 74.144 ;
     RECT  27.395 72.729 27.733 73.632 ;
     RECT  27.733 72.576 27.819 73.632 ;
     RECT  26.099 50.88 28.547 51.801 ;
     RECT  26.291 70.272 29.269 70.56 ;
     RECT  27.819 72.729 29.269 73.632 ;
     RECT  25.077 78.129 29.269 79.456 ;
     RECT  29.269 69.888 29.301 70.56 ;
     RECT  29.301 69.888 29.355 70.816 ;
     RECT  29.269 72.576 29.355 73.632 ;
     RECT  25.139 83.529 29.557 84.201 ;
     RECT  29.269 78.016 29.611 79.456 ;
     RECT  25.717 47.808 30.851 47.84 ;
     RECT  29.557 82.368 31.022 84.201 ;
     RECT  29.611 78.016 31.029 78.801 ;
     RECT  29.355 70.528 31.083 70.816 ;
     RECT  31.022 82.112 31.331 84.201 ;
     RECT  29.269 86.016 31.598 86.048 ;
     RECT  31.598 86.016 31.659 87.2 ;
     RECT  31.659 87.168 31.667 87.2 ;
     RECT  31.083 70.784 32.533 70.816 ;
     RECT  32.533 70.784 32.579 71.072 ;
     RECT  31.029 78.016 33.451 78.944 ;
     RECT  32.579 71.04 34.259 71.072 ;
     RECT  31.331 82.112 35.221 82.144 ;
     RECT  31.331 83.529 35.221 84.201 ;
     RECT  35.221 82.112 35.253 84.201 ;
     RECT  33.397 75.584 35.267 75.616 ;
     RECT  35.253 81.984 35.307 84.201 ;
     RECT  35.307 81.984 36.515 82.016 ;
     RECT  33.451 78.129 36.997 78.944 ;
     RECT  36.997 78.129 39.445 79.008 ;
     RECT  35.307 83.529 39.522 84.201 ;
     RECT  39.445 78.129 39.531 79.84 ;
     RECT  39.522 83.392 39.595 84.201 ;
     RECT  37.573 87.168 39.595 87.2 ;
     RECT  39.531 78.129 40.069 79.008 ;
     RECT  40.069 77.504 40.491 79.008 ;
     RECT  40.491 78.129 43.509 79.008 ;
     RECT  43.509 78.129 43.619 79.904 ;
     RECT  43.619 78.129 44.965 79.008 ;
     RECT  13.139 56.529 45.013 57.201 ;
     RECT  2.16 45.729 45.493 46.401 ;
     RECT  25.963 54.144 45.493 54.176 ;
     RECT  45.493 53.504 45.562 54.176 ;
     RECT  29.355 72.729 46.069 73.632 ;
     RECT  46.069 72.576 46.138 73.824 ;
     RECT  22.251 61.929 46.958 62.601 ;
     RECT  46.693 59.776 46.965 59.808 ;
     RECT  46.965 59.776 47.019 60.32 ;
     RECT  46.958 61.929 47.027 62.752 ;
     RECT  45.493 45.729 47.363 47.52 ;
     RECT  44.965 78.129 47.797 79.072 ;
     RECT  47.797 78.016 47.851 79.072 ;
     RECT  47.077 80.96 47.866 80.992 ;
     RECT  28.547 51.129 48.997 51.801 ;
     RECT  45.013 56.384 49.045 57.201 ;
     RECT  46.138 72.729 49.189 73.824 ;
     RECT  47.093 75.2 49.189 75.232 ;
     RECT  49.189 72.729 49.259 75.232 ;
     RECT  48.997 51.008 49.269 51.801 ;
     RECT  49.259 72.729 49.323 74.72 ;
     RECT  45.562 54.144 49.461 54.176 ;
     RECT  49.045 56.384 49.525 57.312 ;
     RECT  49.461 54.016 49.534 54.176 ;
     RECT  49.534 54.144 49.579 54.176 ;
     RECT  47.019 60.288 49.579 60.32 ;
     RECT  48.805 58.944 50.274 58.976 ;
     RECT  47.269 64.832 50.293 64.864 ;
     RECT  50.274 58.944 50.347 59.104 ;
     RECT  50.293 64.832 50.435 65.952 ;
     RECT  47.851 78.016 50.475 78.944 ;
     RECT  50.475 78.016 50.627 78.801 ;
     RECT  49.525 55.488 50.771 57.312 ;
     RECT  49.323 72.729 51.443 74.08 ;
     RECT  47.027 61.929 51.445 62.601 ;
     RECT  50.435 64.896 51.493 65.952 ;
     RECT  16.019 67.329 51.493 68.001 ;
     RECT  51.493 64.896 51.499 68.001 ;
     RECT  51.445 61.929 51.539 62.752 ;
     RECT  50.771 56.529 51.893 57.312 ;
     RECT  50.347 58.944 51.893 58.976 ;
     RECT  51.893 56.529 51.971 58.976 ;
     RECT  47.363 45.729 52.741 47.392 ;
     RECT  51.499 65.728 53.877 68.001 ;
     RECT  53.845 71.296 53.931 71.328 ;
     RECT  53.877 65.728 53.95 68.128 ;
     RECT  49.269 49.984 55.285 51.801 ;
     RECT  53.95 65.728 55.331 68.001 ;
     RECT  54.613 70.784 55.339 70.816 ;
     RECT  52.741 45.729 55.377 47.584 ;
     RECT  51.443 72.729 55.525 73.632 ;
     RECT  51.539 61.929 55.527 62.601 ;
     RECT  55.285 49.92 55.541 51.801 ;
     RECT  55.541 49.92 55.595 52.512 ;
     RECT  55.331 65.728 55.595 65.76 ;
     RECT  55.525 71.936 55.595 73.632 ;
     RECT  55.595 50.752 55.667 52.512 ;
     RECT  55.541 54.4 56.339 54.432 ;
     RECT  51.971 56.529 57.059 57.632 ;
     RECT  56.965 65.856 57.57 65.888 ;
     RECT  55.331 67.329 57.57 68.001 ;
     RECT  55.527 61.929 57.589 62.752 ;
     RECT  57.57 65.856 57.589 68.001 ;
     RECT  57.541 70.592 57.589 70.624 ;
     RECT  57.589 70.592 57.643 70.752 ;
     RECT  57.589 61.929 57.875 63.84 ;
     RECT  57.589 65.856 57.899 68.384 ;
     RECT  57.643 70.72 58.163 70.752 ;
     RECT  58.914 49.408 58.987 49.44 ;
     RECT  55.667 50.752 58.987 51.801 ;
     RECT  55.813 60.608 59.315 60.64 ;
     RECT  57.875 61.929 59.315 63.264 ;
     RECT  57.899 67.329 60.467 68.384 ;
     RECT  57.059 56.529 61.525 57.201 ;
     RECT  51.971 58.944 61.525 58.976 ;
     RECT  58.987 51.008 61.621 51.801 ;
     RECT  61.621 51.008 61.675 52.64 ;
     RECT  60.373 54.72 61.675 54.752 ;
     RECT  61.675 51.129 61.715 52.64 ;
     RECT  61.715 51.129 69.349 51.801 ;
     RECT  69.349 50.112 69.419 51.801 ;
     RECT  69.419 51.129 70.933 51.801 ;
     RECT  70.933 50.112 71.019 51.801 ;
     RECT  61.525 56.529 71.019 58.976 ;
     RECT  55.595 72.729 79.765 73.401 ;
     RECT  59.315 61.929 83.797 62.601 ;
     RECT  71.019 56.529 83.883 57.888 ;
     RECT  83.797 61.929 83.883 63.712 ;
     RECT  79.765 71.872 83.941 73.401 ;
     RECT  83.941 71.808 84.066 73.401 ;
     RECT  55.541 76.224 84.066 76.256 ;
     RECT  83.829 65.6 84.085 65.632 ;
     RECT  60.467 67.329 84.085 68.001 ;
     RECT  69.365 139.904 84.133 139.936 ;
     RECT  84.066 71.104 84.139 73.401 ;
     RECT  84.066 76.224 84.139 76.704 ;
     RECT  84.133 139.776 84.179 139.936 ;
     RECT  71.019 50.304 84.325 51.801 ;
     RECT  84.179 139.776 84.371 139.808 ;
     RECT  84.085 91.2 84.419 91.232 ;
     RECT  84.325 50.176 84.517 51.801 ;
     RECT  55.377 45.729 84.805 46.401 ;
     RECT  84.805 45.729 84.853 46.56 ;
     RECT  84.853 42.688 84.922 42.72 ;
     RECT  84.139 76.224 84.995 76.256 ;
     RECT  2.16 40.329 85.109 41.001 ;
     RECT  84.853 44.8 85.109 46.56 ;
     RECT  85.093 43.008 85.163 43.04 ;
     RECT  84.139 71.808 85.163 73.401 ;
     RECT  85.093 82.112 85.163 82.144 ;
     RECT  85.109 44.8 85.235 46.816 ;
     RECT  85.235 44.8 85.523 46.401 ;
     RECT  84.517 50.048 85.867 51.801 ;
     RECT  85.794 59.712 85.867 59.744 ;
     RECT  86.389 70.144 86.458 70.176 ;
     RECT  84.085 65.6 86.571 68.001 ;
     RECT  85.109 40.329 86.627 41.248 ;
     RECT  2.16 24.129 86.677 24.801 ;
     RECT  85.109 74.944 86.677 74.976 ;
     RECT  86.677 74.88 86.819 74.976 ;
     RECT  86.677 24 86.965 24.801 ;
     RECT  86.197 27.392 87.019 27.424 ;
     RECT  2.16 18.729 87.061 19.401 ;
     RECT  87.061 17.6 87.147 19.401 ;
     RECT  86.965 24 87.147 25.056 ;
     RECT  2.16 34.929 87.253 35.601 ;
     RECT  2.16 13.329 88.021 14.001 ;
     RECT  87.253 34.929 88.053 36.192 ;
     RECT  86.627 40.329 88.069 41.001 ;
     RECT  88.053 33.024 88.107 36.192 ;
     RECT  88.069 40.329 88.171 41.12 ;
     RECT  88.107 33.024 88.309 35.601 ;
     RECT  88.117 38.72 88.363 38.752 ;
     RECT  88.117 11.904 89.205 11.936 ;
     RECT  88.021 13.329 89.205 14.368 ;
     RECT  89.205 11.904 89.259 14.368 ;
     RECT  86.571 66.24 89.267 68.001 ;
     RECT  89.259 11.904 89.315 14.001 ;
     RECT  89.267 66.368 89.363 68.001 ;
     RECT  88.171 40.329 89.653 41.001 ;
     RECT  85.523 44.864 90.027 46.401 ;
     RECT  85.163 72.729 90.517 73.401 ;
     RECT  90.517 72.32 90.549 73.401 ;
     RECT  86.819 74.88 90.549 74.912 ;
     RECT  90.549 72.32 90.603 74.912 ;
     RECT  87.147 24.129 90.609 25.056 ;
     RECT  90.549 28.032 90.622 28.064 ;
     RECT  90.027 45.056 90.659 46.401 ;
     RECT  90.603 72.729 90.755 74.912 ;
     RECT  85.867 50.304 90.805 51.801 ;
     RECT  88.309 32.96 90.933 35.601 ;
     RECT  90.933 31.872 90.987 35.601 ;
     RECT  90.659 45.312 90.987 46.401 ;
     RECT  90.549 26.432 91.043 26.464 ;
     RECT  91.093 26.368 91.118 26.4 ;
     RECT  88.693 17.088 91.141 17.12 ;
     RECT  87.147 18.729 91.141 19.401 ;
     RECT  90.805 49.6 91.179 51.801 ;
     RECT  91.141 17.088 91.187 19.401 ;
     RECT  90.987 34.929 91.573 35.601 ;
     RECT  2.16 7.929 91.717 8.601 ;
     RECT  89.363 66.496 92.149 68.001 ;
     RECT  92.149 66.176 92.197 68.001 ;
     RECT  92.197 66.176 92.213 69.088 ;
     RECT  92.213 66.048 92.514 69.984 ;
     RECT  92.514 65.344 92.587 69.984 ;
     RECT  90.755 72.729 92.869 74.336 ;
     RECT  90.987 31.872 92.963 32.992 ;
     RECT  92.869 72.729 92.971 74.528 ;
     RECT  92.587 66.048 93.251 69.984 ;
     RECT  93.251 66.176 93.395 69.984 ;
     RECT  92.971 72.729 93.429 73.824 ;
     RECT  92.917 0.512 93.445 0.544 ;
     RECT  89.653 40.329 93.445 41.12 ;
     RECT  93.429 72.576 93.502 73.824 ;
     RECT  91.187 17.536 93.557 19.401 ;
     RECT  89.315 12.8 93.587 14.001 ;
     RECT  93.541 11.328 93.611 11.36 ;
     RECT  91.118 26.24 93.803 26.4 ;
     RECT  93.445 0.512 93.877 1.184 ;
     RECT  2.16 2.529 93.877 3.201 ;
     RECT  93.877 10.816 93.946 10.848 ;
     RECT  93.557 17.024 94.021 19.401 ;
     RECT  90.609 24.129 94.069 24.801 ;
     RECT  93.877 0.512 94.117 3.201 ;
     RECT  93.803 26.368 94.123 26.4 ;
     RECT  94.069 24.129 94.138 25.056 ;
     RECT  93.395 67.329 94.581 69.984 ;
     RECT  94.581 67.329 94.635 70.88 ;
     RECT  93.733 28.16 94.643 28.192 ;
     RECT  94.021 16.128 94.691 19.401 ;
     RECT  94.138 24.129 94.885 24.801 ;
     RECT  93.587 12.928 94.891 14.001 ;
     RECT  94.691 16.128 95.275 17.12 ;
     RECT  94.117 0.064 95.653 3.201 ;
     RECT  94.691 18.729 95.653 19.401 ;
     RECT  91.573 34.929 95.701 36.832 ;
     RECT  95.275 17.088 95.723 17.12 ;
     RECT  95.653 18.729 95.733 19.552 ;
     RECT  90.853 21.184 95.733 21.216 ;
     RECT  95.701 34.929 95.747 37.6 ;
     RECT  95.733 18.729 95.787 21.216 ;
     RECT  95.787 18.729 95.806 20.512 ;
     RECT  95.653 0.064 96.275 3.488 ;
     RECT  92.963 31.872 96.853 31.968 ;
     RECT  96.853 31.744 96.939 31.968 ;
     RECT  96.939 31.936 96.947 31.968 ;
     RECT  93.445 40.329 97.122 41.376 ;
     RECT  94.635 67.329 97.141 68.96 ;
     RECT  94.635 70.848 97.141 70.88 ;
     RECT  97.122 40.329 97.195 41.568 ;
     RECT  95.747 34.929 97.381 35.872 ;
     RECT  96.275 0.064 97.427 3.201 ;
     RECT  97.381 34.816 97.427 35.872 ;
     RECT  97.427 34.816 97.451 35.601 ;
     RECT  97.397 32.128 97.523 32.16 ;
     RECT  91.717 7.929 97.698 8.736 ;
     RECT  97.698 7.929 97.771 9.952 ;
     RECT  97.427 1.728 97.786 3.201 ;
     RECT  94.885 23.872 98.003 24.801 ;
     RECT  97.786 1.856 98.027 3.201 ;
     RECT  97.771 7.929 98.099 8.736 ;
     RECT  94.741 27.968 98.099 28 ;
     RECT  97.141 67.329 98.099 70.88 ;
     RECT  97.427 0.064 98.17 0.096 ;
     RECT  94.891 13.329 98.581 14.001 ;
     RECT  95.747 37.568 98.675 37.6 ;
     RECT  93.502 72.729 98.675 73.824 ;
     RECT  91.179 49.984 98.723 51.801 ;
     RECT  98.581 13.184 98.741 14.001 ;
     RECT  97.189 16.192 98.795 16.224 ;
     RECT  98.741 12.48 98.819 14.001 ;
     RECT  98.723 50.304 99.059 51.801 ;
     RECT  98.099 67.329 100.019 69.6 ;
     RECT  98.675 72.729 101.507 73.568 ;
     RECT  100.019 67.329 104.245 68.96 ;
     RECT  104.245 67.329 105.643 69.6 ;
     RECT  113.365 71.296 113.451 71.328 ;
     RECT  101.507 72.729 118.645 73.401 ;
     RECT  105.643 67.329 119.477 68.96 ;
     RECT  118.933 76.224 119.97 76.256 ;
     RECT  50.627 78.129 119.97 78.801 ;
     RECT  119.97 76.224 120.043 78.801 ;
     RECT  119.477 67.008 122.821 68.96 ;
     RECT  118.645 72.576 123.155 73.401 ;
     RECT  122.821 67.008 123.253 69.088 ;
     RECT  123.155 72.729 123.374 73.401 ;
     RECT  123.374 72.729 123.381 73.568 ;
     RECT  123.381 72.729 123.443 74.72 ;
     RECT  120.043 78.129 123.618 78.801 ;
     RECT  120.043 76.224 123.637 76.256 ;
     RECT  123.618 78.016 123.637 78.801 ;
     RECT  123.637 76.224 123.691 78.801 ;
     RECT  123.443 74.688 123.925 74.72 ;
     RECT  123.691 77.248 123.957 78.801 ;
     RECT  123.925 74.688 124.011 74.912 ;
     RECT  124.011 74.688 124.307 74.848 ;
     RECT  123.253 66.944 124.395 69.088 ;
     RECT  124.395 66.944 124.414 68.896 ;
     RECT  124.414 66.944 124.789 68.384 ;
     RECT  124.789 66.048 124.858 68.384 ;
     RECT  123.957 77.248 124.883 79.712 ;
     RECT  123.061 81.6 125.027 81.632 ;
     RECT  123.443 72.729 127.093 73.401 ;
     RECT  124.307 74.816 127.093 74.848 ;
     RECT  127.093 72.729 127.147 75.36 ;
     RECT  124.858 66.944 127.486 68.384 ;
     RECT  124.883 78.129 128.197 79.712 ;
     RECT  125.941 81.92 128.501 81.952 ;
     RECT  128.501 81.792 128.579 81.952 ;
     RECT  127.147 75.328 128.723 75.36 ;
     RECT  128.197 78.129 128.773 79.84 ;
     RECT  127.486 67.329 129.061 68.384 ;
     RECT  129.061 66.048 129.131 68.384 ;
     RECT  128.773 76.864 130.539 79.84 ;
     RECT  127.237 70.528 131.939 70.56 ;
     RECT  130.539 78.129 131.939 79.84 ;
     RECT  131.939 78.129 132.789 79.648 ;
     RECT  132.789 77.76 132.843 79.648 ;
     RECT  132.843 77.76 132.899 79.136 ;
     RECT  129.131 67.136 132.949 68.001 ;
     RECT  127.147 72.729 134.579 73.824 ;
     RECT  130.485 75.392 134.579 75.424 ;
     RECT  39.595 83.529 134.645 84.201 ;
     RECT  132.899 78.129 134.699 79.136 ;
     RECT  134.645 82.688 134.723 84.201 ;
     RECT  134.645 81.216 135.155 81.248 ;
     RECT  132.949 66.112 135.205 68.001 ;
     RECT  135.205 66.112 135.275 68.896 ;
     RECT  135.221 71.296 135.299 71.328 ;
     RECT  98.027 2.529 137.808 3.201 ;
     RECT  98.099 7.929 137.808 8.601 ;
     RECT  98.819 13.329 137.808 14.001 ;
     RECT  95.806 18.729 137.808 19.401 ;
     RECT  98.003 24.129 137.808 24.801 ;
     RECT  2.16 29.529 137.808 30.201 ;
     RECT  97.451 34.929 137.808 35.601 ;
     RECT  97.195 40.329 137.808 41.001 ;
     RECT  90.987 45.729 137.808 46.401 ;
     RECT  99.059 51.129 137.808 51.801 ;
     RECT  83.883 56.529 137.808 57.201 ;
     RECT  83.883 61.929 137.808 62.601 ;
     RECT  135.275 67.329 137.808 68.001 ;
     RECT  134.579 72.729 137.808 73.401 ;
     RECT  134.699 78.129 137.808 78.801 ;
     RECT  134.723 83.529 137.808 84.201 ;
     RECT  25.715 88.929 137.808 89.601 ;
     RECT  2.16 94.329 137.808 95.001 ;
     RECT  2.16 99.729 137.808 100.401 ;
     RECT  2.16 105.129 137.808 105.801 ;
     RECT  2.16 110.529 137.808 111.201 ;
     RECT  2.16 115.929 137.808 116.601 ;
     RECT  2.16 121.329 137.808 122.001 ;
     RECT  2.16 126.729 137.808 127.401 ;
     RECT  2.16 132.129 137.808 132.801 ;
     RECT  2.16 137.529 137.808 137.817 ;
    LAYER M7 ;
     RECT  93.888 0.034 98.144 0.107 ;
     RECT  93.888 0.107 98.016 1.771 ;
     RECT  95.68 1.771 98.016 1.899 ;
     RECT  95.68 1.899 97.888 2.283 ;
     RECT  97.856 2.283 97.888 2.347 ;
     RECT  95.68 2.283 96.224 3.499 ;
     RECT  97.728 8.693 97.76 9.963 ;
     RECT  93.888 8.693 93.92 10.859 ;
     RECT  93.568 11.317 93.6 12.917 ;
     RECT  89.216 12.789 89.248 14.379 ;
     RECT  93.568 12.917 94.88 16.117 ;
     RECT  93.568 16.117 95.264 16.171 ;
     RECT  98.752 12.469 98.784 16.235 ;
     RECT  93.568 16.171 93.792 17.067 ;
     RECT  95.232 16.171 95.264 17.077 ;
     RECT  95.232 17.077 95.712 17.131 ;
     RECT  95.68 17.131 95.712 19.563 ;
     RECT  95.744 20.469 95.776 21.227 ;
     RECT  87.104 17.589 87.136 24.043 ;
     RECT  93.76 17.067 93.792 25.013 ;
     RECT  90.56 25.013 90.592 26.229 ;
     RECT  93.76 25.013 94.112 26.283 ;
     RECT  86.976 25.013 87.008 27.435 ;
     RECT  90.56 26.229 91.168 28.075 ;
     RECT  94.08 26.283 94.112 28.203 ;
     RECT  96.896 23.861 96.928 31.787 ;
     RECT  91.136 28.075 91.168 31.861 ;
     RECT  90.944 31.861 91.168 31.915 ;
     RECT  88.32 32.949 88.352 33.013 ;
     RECT  97.408 32.117 97.44 34.859 ;
     RECT  88.064 33.013 88.352 36.203 ;
     RECT  95.296 35.829 95.328 36.843 ;
     RECT  88.32 36.203 88.352 38.709 ;
     RECT  88.128 38.709 88.352 38.763 ;
     RECT  90.944 31.915 90.976 41.077 ;
     RECT  88.128 38.763 88.16 41.131 ;
     RECT  85.12 41.205 85.152 42.677 ;
     RECT  89.664 41.077 90.976 44.907 ;
     RECT  89.984 44.907 90.976 45.099 ;
     RECT  90.816 45.099 90.976 45.355 ;
     RECT  50.752 46.645 50.784 47.403 ;
     RECT  90.816 45.355 90.848 49.589 ;
     RECT  11.904 48.693 11.936 49.643 ;
     RECT  90.816 49.589 91.168 49.643 ;
     RECT  55.296 47.541 55.328 49.909 ;
     RECT  55.296 49.909 55.584 49.963 ;
     RECT  84.864 42.677 85.152 50.037 ;
     RECT  84.864 50.037 85.856 50.219 ;
     RECT  49.28 49.973 49.312 50.997 ;
     RECT  58.944 49.397 58.976 51.051 ;
     RECT  24.192 48.949 24.224 54.133 ;
     RECT  49.28 50.997 49.504 54.133 ;
     RECT  23.936 54.133 24.224 54.187 ;
     RECT  23.936 54.187 23.968 54.379 ;
     RECT  55.552 49.963 55.584 54.443 ;
     RECT  16.128 50.997 16.16 54.507 ;
     RECT  25.92 50.421 25.952 54.699 ;
     RECT  61.632 50.997 61.664 54.763 ;
     RECT  13.056 52.149 13.088 55.339 ;
     RECT  45.504 53.493 45.536 56.427 ;
     RECT  49.088 54.133 49.568 57.323 ;
     RECT  10.752 56.373 10.784 57.525 ;
     RECT  10.304 57.525 10.784 57.579 ;
     RECT  20.288 54.389 20.32 58.549 ;
     RECT  51.904 57.269 51.936 58.795 ;
     RECT  70.976 50.101 71.008 58.987 ;
     RECT  49.536 57.323 49.568 59.061 ;
     RECT  20.224 58.549 20.32 59.499 ;
     RECT  10.304 57.579 10.336 60.021 ;
     RECT  12.288 59.701 12.32 60.021 ;
     RECT  10.304 60.021 12.32 60.075 ;
     RECT  49.536 59.061 50.336 60.331 ;
     RECT  20.224 59.499 20.256 60.459 ;
     RECT  6.016 59.509 6.048 61.611 ;
     RECT  8.832 59.765 8.864 61.867 ;
     RECT  14.272 60.341 14.304 61.867 ;
     RECT  50.304 60.331 50.336 62.709 ;
     RECT  11.328 60.075 12.32 62.763 ;
     RECT  46.976 59.765 47.008 62.763 ;
     RECT  6.08 61.813 6.496 63.915 ;
     RECT  22.208 63.221 22.24 64.107 ;
     RECT  23.872 64.053 23.904 64.949 ;
     RECT  85.824 50.219 85.856 65.589 ;
     RECT  83.84 57.845 83.872 65.643 ;
     RECT  55.552 62.709 55.584 65.717 ;
     RECT  55.296 65.717 55.584 65.771 ;
     RECT  57.6 63.797 57.632 65.845 ;
     RECT  50.304 62.709 51.488 65.899 ;
     RECT  50.304 65.899 50.464 65.963 ;
     RECT  91.136 49.643 91.168 66.037 ;
     RECT  92.544 65.333 92.576 66.037 ;
     RECT  91.136 66.037 92.576 66.091 ;
     RECT  85.824 65.589 86.56 66.283 ;
     RECT  85.824 66.283 86.432 66.347 ;
     RECT  124.8 66.037 124.832 66.933 ;
     RECT  57.6 65.845 57.888 66.987 ;
     RECT  91.136 66.091 92.32 66.987 ;
     RECT  124.352 66.933 124.832 66.987 ;
     RECT  14.208 63.477 14.24 67.125 ;
     RECT  13.632 67.125 14.24 67.179 ;
     RECT  119.488 66.997 119.52 68.331 ;
     RECT  124.352 66.987 124.384 68.341 ;
     RECT  129.088 66.037 129.12 68.395 ;
     RECT  123.712 68.341 124.384 68.907 ;
     RECT  123.968 68.907 124.384 69.099 ;
     RECT  97.152 41.525 97.184 69.611 ;
     RECT  105.6 68.085 105.632 69.611 ;
     RECT  12.288 62.763 12.32 70.133 ;
     RECT  13.632 67.179 13.664 70.133 ;
     RECT  12.288 70.133 13.664 70.187 ;
     RECT  86.4 66.347 86.432 70.187 ;
     RECT  12.672 70.187 13.664 70.251 ;
     RECT  127.424 66.933 127.456 70.571 ;
     RECT  23.872 64.949 24.352 70.581 ;
     RECT  8.576 68.085 8.608 70.763 ;
     RECT  57.6 66.987 57.632 70.763 ;
     RECT  55.296 65.771 55.328 70.827 ;
     RECT  94.592 69.941 94.624 70.891 ;
     RECT  53.888 66.101 53.92 71.339 ;
     RECT  113.408 68.277 113.44 71.339 ;
     RECT  135.232 66.101 135.264 71.339 ;
     RECT  84.096 66.293 84.128 71.797 ;
     RECT  92.16 66.987 92.32 72.565 ;
     RECT  29.312 69.877 29.344 72.619 ;
     RECT  23.68 70.581 24.352 73.525 ;
     RECT  123.968 69.099 124 73.525 ;
     RECT  92.16 72.565 93.472 73.579 ;
     RECT  46.08 72.565 46.112 73.589 ;
     RECT  27.776 72.565 27.808 73.643 ;
     RECT  23.68 73.525 24.48 73.771 ;
     RECT  6.464 63.915 6.496 73.781 ;
     RECT  50.432 65.963 50.464 73.781 ;
     RECT  46.08 73.589 47.264 73.835 ;
     RECT  92.288 73.579 93.472 73.835 ;
     RECT  6.464 73.781 7.008 74.155 ;
     RECT  92.288 73.835 92.96 74.155 ;
     RECT  90.56 72.309 90.592 74.347 ;
     RECT  92.928 74.155 92.96 74.539 ;
     RECT  9.856 73.781 9.888 74.731 ;
     RECT  123.392 73.525 124 74.731 ;
     RECT  47.232 73.835 47.264 75.189 ;
     RECT  49.28 73.781 50.464 75.189 ;
     RECT  47.104 75.189 47.264 75.243 ;
     RECT  127.104 73.525 127.136 75.371 ;
     RECT  16.32 73.973 16.352 76.213 ;
     RECT  123.968 74.731 124 76.213 ;
     RECT  16.32 76.213 16.544 76.267 ;
     RECT  55.552 71.925 55.584 76.267 ;
     RECT  19.392 73.525 19.424 76.405 ;
     RECT  19.392 76.405 19.872 76.459 ;
     RECT  39.488 73.589 39.52 77.493 ;
     RECT  120 76.213 120.032 77.547 ;
     RECT  19.84 76.459 19.872 77.557 ;
     RECT  19.84 77.557 21.088 77.611 ;
     RECT  9.792 75.189 9.824 77.867 ;
     RECT  47.104 75.243 47.136 78.005 ;
     RECT  16.512 76.267 16.544 78.059 ;
     RECT  33.408 75.573 33.44 78.059 ;
     RECT  49.216 75.189 50.464 78.059 ;
     RECT  123.648 76.213 124 78.059 ;
     RECT  12.672 70.251 12.704 78.901 ;
     RECT  24.448 73.771 24.48 78.955 ;
     RECT  50.432 78.059 50.464 78.955 ;
     RECT  39.488 77.493 40.48 79.019 ;
     RECT  6.464 74.155 6.496 79.211 ;
     RECT  132.8 77.749 132.832 79.659 ;
     RECT  123.968 78.059 124 79.723 ;
     RECT  39.488 79.019 39.584 79.851 ;
     RECT  130.496 75.381 130.528 79.851 ;
     RECT  43.52 78.965 43.552 79.915 ;
     RECT  12.672 78.901 13.664 79.979 ;
     RECT  21.056 77.611 21.088 80.427 ;
     RECT  47.104 78.005 47.84 81.003 ;
     RECT  128.512 79.797 128.544 81.835 ;
     RECT  31.04 70.517 31.072 82.101 ;
     RECT  31.04 82.101 31.648 82.155 ;
     RECT  84.096 71.797 85.152 82.155 ;
     RECT  29.568 79.413 29.6 82.411 ;
     RECT  134.656 79.093 134.688 82.731 ;
     RECT  25.088 79.413 25.12 83.307 ;
     RECT  35.264 81.973 35.296 83.307 ;
     RECT  14.272 80.757 14.304 84.395 ;
     RECT  12.672 79.979 12.704 84.533 ;
     RECT  12.608 84.533 12.704 84.597 ;
     RECT  12.608 84.597 12.832 84.779 ;
     RECT  7.68 81.333 7.712 86.187 ;
     RECT  31.616 82.155 31.648 87.211 ;
     RECT  39.552 79.851 39.584 87.211 ;
     RECT  12.8 84.779 12.832 87.541 ;
     RECT  14.848 86.005 14.88 87.595 ;
     RECT  11.776 87.541 12.832 88.811 ;
     RECT  20.48 84.725 20.512 88.811 ;
     RECT  23.424 88.757 23.456 89.771 ;
     RECT  7.616 86.389 7.648 89.899 ;
     RECT  84.096 82.155 84.128 91.243 ;
     RECT  11.776 88.811 11.808 92.651 ;
     RECT  18.048 91.125 18.08 92.715 ;
     RECT  69.376 50.101 69.408 139.947 ;
  END
END ot_hgi_att_row_sources_p
END LIBRARY
